VERSION 5.7 ;
  NOWIREEXTENSIONATPIN ON ;
  DIVIDERCHAR "/" ;
  BUSBITCHARS "[]" ;
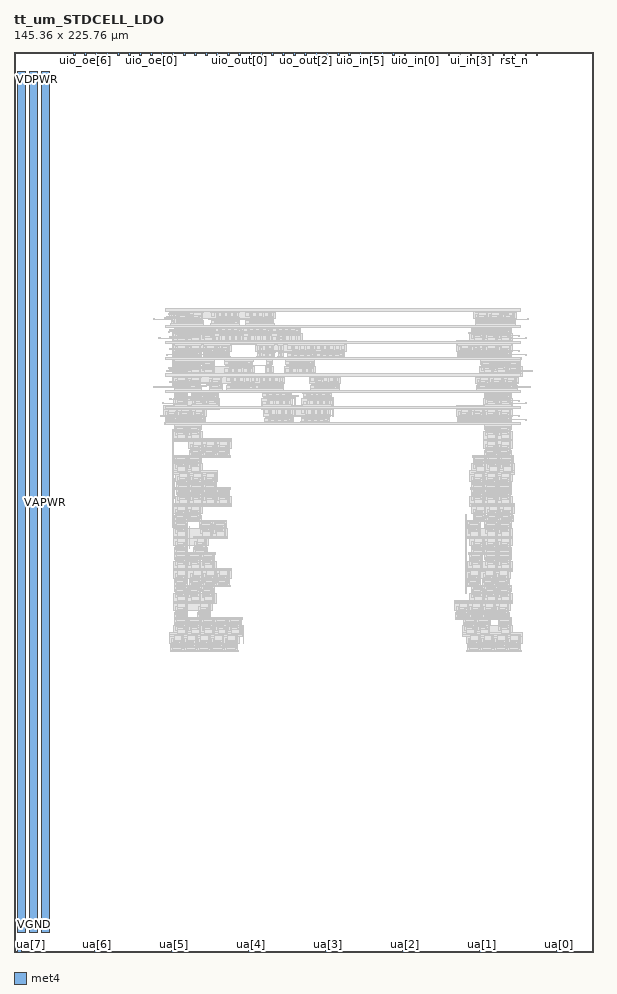
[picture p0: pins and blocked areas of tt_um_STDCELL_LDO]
MACRO tt_um_STDCELL_LDO
  CLASS BLOCK ;
  FOREIGN tt_um_STDCELL_LDO ;
  ORIGIN 0.000 0.000 ;
  SIZE 145.360 BY 225.760 ;
  PIN clk
    DIRECTION INPUT ;
    USE SIGNAL ;
    PORT
      LAYER met4 ;
        RECT 128.190 224.760 128.490 225.760 ;
    END
  END clk
  PIN ena
    DIRECTION INPUT ;
    USE SIGNAL ;
    PORT
      LAYER met4 ;
        RECT 130.950 224.760 131.250 225.760 ;
    END
  END ena
  PIN rst_n
    DIRECTION INPUT ;
    USE SIGNAL ;
    PORT
      LAYER met4 ;
        RECT 125.430 224.760 125.730 225.760 ;
    END
  END rst_n
  PIN ua[0]
    DIRECTION INOUT ;
    USE SIGNAL ;
    ANTENNAGATEAREA 9.000000 ;
    PORT
      LAYER met4 ;
        RECT 136.170 0.000 137.070 1.000 ;
    END
  END ua[0]
  PIN ua[1]
    DIRECTION INOUT ;
    USE SIGNAL ;
    ANTENNAGATEAREA 18.000000 ;
    ANTENNADIFFAREA 1.282500 ;
    PORT
      LAYER met4 ;
        RECT 116.850 0.000 117.750 1.000 ;
    END
  END ua[1]
  PIN ua[2]
    DIRECTION INOUT ;
    USE SIGNAL ;
    ANTENNAGATEAREA 1.125000 ;
    PORT
      LAYER met4 ;
        RECT 97.530 0.000 98.430 1.000 ;
    END
  END ua[2]
  PIN ua[3]
    DIRECTION INOUT ;
    USE SIGNAL ;
    ANTENNAGATEAREA 9.000000 ;
    ANTENNADIFFAREA 82.079994 ;
    PORT
      LAYER met4 ;
        RECT 78.210 0.000 79.110 1.000 ;
    END
  END ua[3]
  PIN ua[4]
    DIRECTION INOUT ;
    USE SIGNAL ;
    PORT
      LAYER met4 ;
        RECT 58.890 0.000 59.790 1.000 ;
    END
  END ua[4]
  PIN ua[5]
    DIRECTION INOUT ;
    USE SIGNAL ;
    PORT
      LAYER met4 ;
        RECT 39.570 0.000 40.470 1.000 ;
    END
  END ua[5]
  PIN ua[6]
    DIRECTION INOUT ;
    USE SIGNAL ;
    PORT
      LAYER met4 ;
        RECT 20.250 0.000 21.150 1.000 ;
    END
  END ua[6]
  PIN ua[7]
    DIRECTION INOUT ;
    USE SIGNAL ;
    PORT
      LAYER met4 ;
        RECT 0.930 0.000 1.830 1.000 ;
    END
  END ua[7]
  PIN ui_in[0]
    DIRECTION INPUT ;
    USE SIGNAL ;
    PORT
      LAYER met4 ;
        RECT 122.670 224.760 122.970 225.760 ;
    END
  END ui_in[0]
  PIN ui_in[1]
    DIRECTION INPUT ;
    USE SIGNAL ;
    PORT
      LAYER met4 ;
        RECT 119.910 224.760 120.210 225.760 ;
    END
  END ui_in[1]
  PIN ui_in[2]
    DIRECTION INPUT ;
    USE SIGNAL ;
    PORT
      LAYER met4 ;
        RECT 117.150 224.760 117.450 225.760 ;
    END
  END ui_in[2]
  PIN ui_in[3]
    DIRECTION INPUT ;
    USE SIGNAL ;
    PORT
      LAYER met4 ;
        RECT 114.390 224.760 114.690 225.760 ;
    END
  END ui_in[3]
  PIN ui_in[4]
    DIRECTION INPUT ;
    USE SIGNAL ;
    PORT
      LAYER met4 ;
        RECT 111.630 224.760 111.930 225.760 ;
    END
  END ui_in[4]
  PIN ui_in[5]
    DIRECTION INPUT ;
    USE SIGNAL ;
    PORT
      LAYER met4 ;
        RECT 108.870 224.760 109.170 225.760 ;
    END
  END ui_in[5]
  PIN ui_in[6]
    DIRECTION INPUT ;
    USE SIGNAL ;
    PORT
      LAYER met4 ;
        RECT 106.110 224.760 106.410 225.760 ;
    END
  END ui_in[6]
  PIN ui_in[7]
    DIRECTION INPUT ;
    USE SIGNAL ;
    PORT
      LAYER met4 ;
        RECT 103.350 224.760 103.650 225.760 ;
    END
  END ui_in[7]
  PIN uio_in[0]
    DIRECTION INPUT ;
    USE SIGNAL ;
    PORT
      LAYER met4 ;
        RECT 100.590 224.760 100.890 225.760 ;
    END
  END uio_in[0]
  PIN uio_in[1]
    DIRECTION INPUT ;
    USE SIGNAL ;
    PORT
      LAYER met4 ;
        RECT 97.830 224.760 98.130 225.760 ;
    END
  END uio_in[1]
  PIN uio_in[2]
    DIRECTION INPUT ;
    USE SIGNAL ;
    PORT
      LAYER met4 ;
        RECT 95.070 224.760 95.370 225.760 ;
    END
  END uio_in[2]
  PIN uio_in[3]
    DIRECTION INPUT ;
    USE SIGNAL ;
    PORT
      LAYER met4 ;
        RECT 92.310 224.760 92.610 225.760 ;
    END
  END uio_in[3]
  PIN uio_in[4]
    DIRECTION INPUT ;
    USE SIGNAL ;
    PORT
      LAYER met4 ;
        RECT 89.550 224.760 89.850 225.760 ;
    END
  END uio_in[4]
  PIN uio_in[5]
    DIRECTION INPUT ;
    USE SIGNAL ;
    PORT
      LAYER met4 ;
        RECT 86.790 224.760 87.090 225.760 ;
    END
  END uio_in[5]
  PIN uio_in[6]
    DIRECTION INPUT ;
    USE SIGNAL ;
    PORT
      LAYER met4 ;
        RECT 84.030 224.760 84.330 225.760 ;
    END
  END uio_in[6]
  PIN uio_in[7]
    DIRECTION INPUT ;
    USE SIGNAL ;
    PORT
      LAYER met4 ;
        RECT 81.270 224.760 81.570 225.760 ;
    END
  END uio_in[7]
  PIN uio_oe[0]
    DIRECTION OUTPUT ;
    USE SIGNAL ;
    PORT
      LAYER met4 ;
        RECT 34.350 224.760 34.650 225.760 ;
    END
  END uio_oe[0]
  PIN uio_oe[1]
    DIRECTION OUTPUT ;
    USE SIGNAL ;
    PORT
      LAYER met4 ;
        RECT 31.590 224.760 31.890 225.760 ;
    END
  END uio_oe[1]
  PIN uio_oe[2]
    DIRECTION OUTPUT ;
    USE SIGNAL ;
    PORT
      LAYER met4 ;
        RECT 28.830 224.760 29.130 225.760 ;
    END
  END uio_oe[2]
  PIN uio_oe[3]
    DIRECTION OUTPUT ;
    USE SIGNAL ;
    PORT
      LAYER met4 ;
        RECT 26.070 224.760 26.370 225.760 ;
    END
  END uio_oe[3]
  PIN uio_oe[4]
    DIRECTION OUTPUT ;
    USE SIGNAL ;
    PORT
      LAYER met4 ;
        RECT 23.310 224.760 23.610 225.760 ;
    END
  END uio_oe[4]
  PIN uio_oe[5]
    DIRECTION OUTPUT ;
    USE SIGNAL ;
    PORT
      LAYER met4 ;
        RECT 20.550 224.760 20.850 225.760 ;
    END
  END uio_oe[5]
  PIN uio_oe[6]
    DIRECTION OUTPUT ;
    USE SIGNAL ;
    PORT
      LAYER met4 ;
        RECT 17.790 224.760 18.090 225.760 ;
    END
  END uio_oe[6]
  PIN uio_oe[7]
    DIRECTION OUTPUT ;
    USE SIGNAL ;
    PORT
      LAYER met4 ;
        RECT 15.030 224.760 15.330 225.760 ;
    END
  END uio_oe[7]
  PIN uio_out[0]
    DIRECTION OUTPUT ;
    USE SIGNAL ;
    PORT
      LAYER met4 ;
        RECT 56.430 224.760 56.730 225.760 ;
    END
  END uio_out[0]
  PIN uio_out[1]
    DIRECTION OUTPUT ;
    USE SIGNAL ;
    PORT
      LAYER met4 ;
        RECT 53.670 224.760 53.970 225.760 ;
    END
  END uio_out[1]
  PIN uio_out[2]
    DIRECTION OUTPUT ;
    USE SIGNAL ;
    PORT
      LAYER met4 ;
        RECT 50.910 224.760 51.210 225.760 ;
    END
  END uio_out[2]
  PIN uio_out[3]
    DIRECTION OUTPUT ;
    USE SIGNAL ;
    PORT
      LAYER met4 ;
        RECT 48.150 224.760 48.450 225.760 ;
    END
  END uio_out[3]
  PIN uio_out[4]
    DIRECTION OUTPUT ;
    USE SIGNAL ;
    PORT
      LAYER met4 ;
        RECT 45.390 224.760 45.690 225.760 ;
    END
  END uio_out[4]
  PIN uio_out[5]
    DIRECTION OUTPUT ;
    USE SIGNAL ;
    PORT
      LAYER met4 ;
        RECT 42.630 224.760 42.930 225.760 ;
    END
  END uio_out[5]
  PIN uio_out[6]
    DIRECTION OUTPUT ;
    USE SIGNAL ;
    PORT
      LAYER met4 ;
        RECT 39.870 224.760 40.170 225.760 ;
    END
  END uio_out[6]
  PIN uio_out[7]
    DIRECTION OUTPUT ;
    USE SIGNAL ;
    PORT
      LAYER met4 ;
        RECT 37.110 224.760 37.410 225.760 ;
    END
  END uio_out[7]
  PIN uo_out[0]
    DIRECTION OUTPUT ;
    USE SIGNAL ;
    PORT
      LAYER met4 ;
        RECT 78.510 224.760 78.810 225.760 ;
    END
  END uo_out[0]
  PIN uo_out[1]
    DIRECTION OUTPUT ;
    USE SIGNAL ;
    PORT
      LAYER met4 ;
        RECT 75.750 224.760 76.050 225.760 ;
    END
  END uo_out[1]
  PIN uo_out[2]
    DIRECTION OUTPUT ;
    USE SIGNAL ;
    PORT
      LAYER met4 ;
        RECT 72.990 224.760 73.290 225.760 ;
    END
  END uo_out[2]
  PIN uo_out[3]
    DIRECTION OUTPUT ;
    USE SIGNAL ;
    PORT
      LAYER met4 ;
        RECT 70.230 224.760 70.530 225.760 ;
    END
  END uo_out[3]
  PIN uo_out[4]
    DIRECTION OUTPUT ;
    USE SIGNAL ;
    PORT
      LAYER met4 ;
        RECT 67.470 224.760 67.770 225.760 ;
    END
  END uo_out[4]
  PIN uo_out[5]
    DIRECTION OUTPUT ;
    USE SIGNAL ;
    PORT
      LAYER met4 ;
        RECT 64.710 224.760 65.010 225.760 ;
    END
  END uo_out[5]
  PIN uo_out[6]
    DIRECTION OUTPUT ;
    USE SIGNAL ;
    PORT
      LAYER met4 ;
        RECT 61.950 224.760 62.250 225.760 ;
    END
  END uo_out[6]
  PIN uo_out[7]
    DIRECTION OUTPUT ;
    USE SIGNAL ;
    PORT
      LAYER met4 ;
        RECT 59.190 224.760 59.490 225.760 ;
    END
  END uo_out[7]
  PIN VDPWR
    DIRECTION INOUT ;
    USE POWER ;
    PORT
      LAYER met4 ;
        RECT 1.000 5.000 3.000 220.760 ;
    END
  END VDPWR
  PIN VGND
    DIRECTION INOUT ;
    USE GROUND ;
    PORT
      LAYER met4 ;
        RECT 4.000 5.000 6.000 220.760 ;
    END
  END VGND
  PIN VAPWR
    DIRECTION INOUT ;
    USE POWER ;
    PORT
      LAYER met4 ;
        RECT 7.000 5.000 9.000 220.760 ;
    END
  END VAPWR
  OBS
      LAYER nwell ;
        RECT 38.990 158.825 65.570 161.425 ;
        RECT 115.310 158.825 126.050 161.425 ;
      LAYER pwell ;
        RECT 39.410 157.155 40.740 158.355 ;
        RECT 40.780 157.155 44.100 158.435 ;
        RECT 44.140 157.155 47.460 158.435 ;
        RECT 49.665 157.155 56.565 158.525 ;
        RECT 58.305 157.155 65.205 158.525 ;
        RECT 115.660 157.155 118.980 158.435 ;
        RECT 119.020 157.155 122.340 158.435 ;
        RECT 122.380 157.155 125.700 158.435 ;
        RECT 39.190 156.725 72.090 157.155 ;
        RECT 114.550 156.725 125.850 157.155 ;
        RECT 40.300 155.445 43.620 156.725 ;
        RECT 43.660 155.445 46.980 156.725 ;
        RECT 47.020 155.445 50.340 156.725 ;
        RECT 50.625 155.355 57.525 156.725 ;
        RECT 57.825 155.355 64.725 156.725 ;
        RECT 65.025 155.355 71.925 156.725 ;
        RECT 114.700 155.445 118.020 156.725 ;
        RECT 118.060 155.445 121.380 156.725 ;
        RECT 121.420 155.445 124.740 156.725 ;
      LAYER nwell ;
        RECT 39.950 153.285 72.290 155.055 ;
        RECT 114.350 153.285 125.090 155.055 ;
        RECT 39.950 152.455 83.330 153.285 ;
        RECT 39.950 150.685 54.530 152.455 ;
        RECT 60.590 150.685 83.330 152.455 ;
        RECT 110.990 150.685 125.090 153.285 ;
      LAYER pwell ;
        RECT 40.300 149.015 43.620 150.295 ;
        RECT 43.660 149.015 46.980 150.295 ;
        RECT 47.500 149.015 50.820 150.295 ;
        RECT 50.860 149.015 54.180 150.295 ;
        RECT 61.010 149.015 62.340 150.215 ;
        RECT 62.450 149.015 63.780 150.215 ;
        RECT 63.890 149.015 65.220 150.215 ;
        RECT 66.290 149.015 67.620 150.215 ;
        RECT 68.865 149.015 75.765 150.385 ;
        RECT 76.065 149.015 82.965 150.385 ;
        RECT 111.340 149.015 114.660 150.295 ;
        RECT 114.700 149.015 118.020 150.295 ;
        RECT 118.060 149.015 121.380 150.295 ;
        RECT 121.420 149.015 124.740 150.295 ;
        RECT 40.150 148.585 60.090 149.015 ;
        RECT 60.790 148.585 65.370 149.015 ;
        RECT 66.070 148.585 67.770 149.015 ;
        RECT 67.990 148.585 83.130 149.015 ;
        RECT 111.190 148.585 127.290 149.015 ;
        RECT 40.300 147.305 43.620 148.585 ;
        RECT 43.660 147.305 46.980 148.585 ;
        RECT 47.020 147.305 50.340 148.585 ;
        RECT 53.025 147.215 59.925 148.585 ;
        RECT 63.410 147.385 64.740 148.585 ;
        RECT 68.385 147.215 75.285 148.585 ;
        RECT 117.100 147.305 120.420 148.585 ;
        RECT 120.460 147.305 123.780 148.585 ;
        RECT 123.820 147.305 127.140 148.585 ;
      LAYER nwell ;
        RECT 39.950 145.145 60.290 146.915 ;
        RECT 62.990 145.145 65.090 146.915 ;
        RECT 67.790 145.145 75.650 146.915 ;
        RECT 116.750 145.145 127.490 146.915 ;
        RECT 39.950 144.315 81.890 145.145 ;
        RECT 39.950 142.545 67.970 144.315 ;
        RECT 74.030 142.545 81.890 144.315 ;
        RECT 115.790 144.315 127.490 145.145 ;
        RECT 115.790 142.545 126.530 144.315 ;
      LAYER pwell ;
        RECT 40.300 140.875 43.620 142.155 ;
        RECT 43.660 140.875 46.980 142.155 ;
        RECT 48.940 140.875 52.260 142.155 ;
        RECT 53.505 140.875 60.405 142.245 ;
        RECT 60.705 140.875 67.605 142.245 ;
        RECT 74.625 140.875 81.525 142.245 ;
        RECT 116.140 140.875 119.460 142.155 ;
        RECT 119.500 140.875 122.820 142.155 ;
        RECT 122.860 140.875 126.180 142.155 ;
        RECT 40.150 140.445 52.410 140.875 ;
        RECT 53.110 140.445 69.690 140.875 ;
        RECT 72.310 140.445 81.690 140.875 ;
        RECT 115.990 140.445 126.330 140.875 ;
        RECT 40.300 139.165 43.620 140.445 ;
        RECT 44.620 139.165 47.940 140.445 ;
        RECT 47.980 139.165 51.300 140.445 ;
        RECT 62.625 139.075 69.525 140.445 ;
        RECT 72.705 139.075 79.605 140.445 ;
        RECT 118.060 139.165 121.380 140.445 ;
        RECT 121.420 139.165 124.740 140.445 ;
      LAYER nwell ;
        RECT 39.950 137.005 51.650 138.775 ;
        RECT 37.550 136.175 51.650 137.005 ;
        RECT 62.030 137.005 69.890 138.775 ;
        RECT 72.110 137.005 79.970 138.775 ;
        RECT 117.710 137.005 125.090 138.775 ;
        RECT 62.030 136.175 79.970 137.005 ;
        RECT 37.550 134.405 48.290 136.175 ;
        RECT 62.510 134.405 79.490 136.175 ;
        RECT 110.990 134.405 125.090 137.005 ;
      LAYER pwell ;
        RECT 37.900 132.735 41.220 134.015 ;
        RECT 41.260 132.735 44.580 134.015 ;
        RECT 44.620 132.735 47.940 134.015 ;
        RECT 63.105 132.735 70.005 134.105 ;
        RECT 72.225 132.735 79.125 134.105 ;
        RECT 111.340 132.735 114.660 134.015 ;
        RECT 114.700 132.735 118.020 134.015 ;
        RECT 118.060 132.735 121.380 134.015 ;
        RECT 121.420 132.735 124.740 134.015 ;
        RECT 37.750 132.305 48.090 132.735 ;
        RECT 62.710 132.305 70.170 132.735 ;
        RECT 71.830 132.305 79.290 132.735 ;
        RECT 111.190 132.305 124.890 132.735 ;
        RECT 40.300 131.025 43.620 132.305 ;
        RECT 43.660 131.025 46.980 132.305 ;
        RECT 118.060 131.025 121.380 132.305 ;
        RECT 121.420 131.025 124.740 132.305 ;
      LAYER nwell ;
        RECT 39.950 128.865 47.330 130.635 ;
        RECT 39.950 128.035 54.530 128.865 ;
        RECT 43.790 126.265 54.530 128.035 ;
        RECT 117.710 126.265 125.090 130.635 ;
      LAYER pwell ;
        RECT 44.140 124.595 47.460 125.875 ;
        RECT 47.500 124.595 50.820 125.875 ;
        RECT 50.860 124.595 54.180 125.875 ;
        RECT 118.060 124.595 121.380 125.875 ;
        RECT 121.420 124.595 124.740 125.875 ;
        RECT 40.150 124.165 54.330 124.595 ;
        RECT 115.030 124.165 125.370 124.595 ;
        RECT 40.300 122.885 43.620 124.165 ;
        RECT 43.660 122.885 46.980 124.165 ;
        RECT 115.180 122.885 118.500 124.165 ;
        RECT 118.540 122.885 121.860 124.165 ;
        RECT 121.900 122.885 125.220 124.165 ;
      LAYER nwell ;
        RECT 39.950 120.725 47.330 122.495 ;
        RECT 114.830 120.725 125.570 122.495 ;
        RECT 39.950 119.895 51.170 120.725 ;
        RECT 40.430 118.125 51.170 119.895 ;
        RECT 114.350 119.895 125.570 120.725 ;
        RECT 114.350 118.125 125.090 119.895 ;
      LAYER pwell ;
        RECT 40.780 116.455 44.100 117.735 ;
        RECT 44.140 116.455 47.460 117.735 ;
        RECT 47.500 116.455 50.820 117.735 ;
        RECT 114.700 116.455 118.020 117.735 ;
        RECT 118.060 116.455 121.380 117.735 ;
        RECT 121.420 116.455 124.740 117.735 ;
        RECT 40.630 116.025 54.330 116.455 ;
        RECT 114.550 116.025 124.890 116.455 ;
        RECT 40.780 114.745 44.100 116.025 ;
        RECT 44.140 114.745 47.460 116.025 ;
        RECT 47.500 114.745 50.820 116.025 ;
        RECT 50.860 114.745 54.180 116.025 ;
        RECT 114.700 114.745 118.020 116.025 ;
        RECT 118.060 114.745 121.380 116.025 ;
        RECT 121.420 114.745 124.740 116.025 ;
      LAYER nwell ;
        RECT 40.430 112.585 54.530 114.355 ;
        RECT 39.950 111.755 54.530 112.585 ;
        RECT 114.350 112.585 125.090 114.355 ;
        RECT 114.350 111.755 125.570 112.585 ;
        RECT 39.950 109.985 47.330 111.755 ;
        RECT 114.830 109.985 125.570 111.755 ;
      LAYER pwell ;
        RECT 40.300 108.315 43.620 109.595 ;
        RECT 43.660 108.315 46.980 109.595 ;
        RECT 115.180 108.315 118.500 109.595 ;
        RECT 118.540 108.315 121.860 109.595 ;
        RECT 121.900 108.315 125.220 109.595 ;
        RECT 40.150 107.885 53.370 108.315 ;
        RECT 113.590 107.885 125.370 108.315 ;
        RECT 40.300 106.605 43.620 107.885 ;
        RECT 46.540 106.605 49.860 107.885 ;
        RECT 49.900 106.605 53.220 107.885 ;
        RECT 113.740 106.605 117.060 107.885 ;
        RECT 118.060 106.605 121.380 107.885 ;
        RECT 121.420 106.605 124.740 107.885 ;
      LAYER nwell ;
        RECT 39.950 103.615 53.570 106.215 ;
        RECT 113.390 103.615 125.090 106.215 ;
        RECT 39.950 101.845 48.770 103.615 ;
        RECT 114.350 101.845 125.090 103.615 ;
      LAYER pwell ;
        RECT 40.300 100.175 43.620 101.455 ;
        RECT 45.100 100.175 48.420 101.455 ;
        RECT 114.700 100.175 118.020 101.455 ;
        RECT 118.060 100.175 121.380 101.455 ;
        RECT 121.420 100.175 124.740 101.455 ;
        RECT 40.150 99.745 50.490 100.175 ;
        RECT 114.070 99.745 124.890 100.175 ;
        RECT 40.300 98.465 43.620 99.745 ;
        RECT 43.660 98.465 46.980 99.745 ;
        RECT 47.020 98.465 50.340 99.745 ;
        RECT 114.220 98.465 117.540 99.745 ;
        RECT 118.060 98.465 121.380 99.745 ;
        RECT 121.420 98.465 124.740 99.745 ;
      LAYER nwell ;
        RECT 39.950 96.305 50.690 98.075 ;
        RECT 113.870 96.305 125.090 98.075 ;
        RECT 39.950 93.705 54.530 96.305 ;
        RECT 113.390 95.475 125.090 96.305 ;
        RECT 113.390 93.705 124.610 95.475 ;
      LAYER pwell ;
        RECT 40.300 92.035 43.620 93.315 ;
        RECT 44.140 92.035 47.460 93.315 ;
        RECT 47.500 92.035 50.820 93.315 ;
        RECT 50.860 92.035 54.180 93.315 ;
        RECT 113.740 92.035 117.060 93.315 ;
        RECT 117.580 92.035 120.900 93.315 ;
        RECT 120.940 92.035 124.260 93.315 ;
        RECT 40.150 91.605 54.330 92.035 ;
        RECT 113.590 91.605 124.890 92.035 ;
        RECT 40.300 90.325 43.620 91.605 ;
        RECT 43.660 90.325 46.980 91.605 ;
        RECT 47.020 90.325 50.340 91.605 ;
        RECT 114.700 90.325 118.020 91.605 ;
        RECT 118.060 90.325 121.380 91.605 ;
        RECT 121.420 90.325 124.740 91.605 ;
      LAYER nwell ;
        RECT 39.950 87.335 50.690 89.935 ;
        RECT 114.350 88.165 125.090 89.935 ;
        RECT 110.510 87.335 125.090 88.165 ;
        RECT 39.950 85.565 49.730 87.335 ;
        RECT 110.510 85.565 124.610 87.335 ;
      LAYER pwell ;
        RECT 40.300 83.895 43.620 85.175 ;
        RECT 46.060 83.895 49.380 85.175 ;
        RECT 110.860 83.895 114.180 85.175 ;
        RECT 114.220 83.895 117.540 85.175 ;
        RECT 117.580 83.895 120.900 85.175 ;
        RECT 120.940 83.895 124.260 85.175 ;
        RECT 40.150 83.465 57.210 83.895 ;
        RECT 110.710 83.465 124.890 83.895 ;
        RECT 40.300 82.185 43.620 83.465 ;
        RECT 43.660 82.185 46.980 83.465 ;
        RECT 47.020 82.185 50.340 83.465 ;
        RECT 50.380 82.185 53.700 83.465 ;
        RECT 53.740 82.185 57.060 83.465 ;
        RECT 112.780 82.185 116.100 83.465 ;
        RECT 116.140 82.185 119.460 83.465 ;
        RECT 121.420 82.185 124.740 83.465 ;
      LAYER nwell ;
        RECT 39.950 80.025 57.410 81.795 ;
        RECT 38.990 79.195 57.410 80.025 ;
        RECT 112.430 80.025 125.090 81.795 ;
        RECT 112.430 79.195 127.490 80.025 ;
        RECT 38.990 77.425 56.450 79.195 ;
        RECT 113.390 77.425 127.490 79.195 ;
      LAYER pwell ;
        RECT 39.340 75.755 42.660 77.035 ;
        RECT 42.700 75.755 46.020 77.035 ;
        RECT 46.060 75.755 49.380 77.035 ;
        RECT 49.420 75.755 52.740 77.035 ;
        RECT 52.780 75.755 56.100 77.035 ;
        RECT 113.740 75.755 117.060 77.035 ;
        RECT 117.100 75.755 120.420 77.035 ;
        RECT 120.460 75.755 123.780 77.035 ;
        RECT 123.820 75.755 127.140 77.035 ;
        RECT 39.190 75.325 56.250 75.755 ;
        RECT 113.590 75.325 127.290 75.755 ;
      LAYER li1 ;
        RECT 39.320 160.925 47.480 161.095 ;
        RECT 49.400 160.925 56.600 161.095 ;
        RECT 58.040 160.925 65.240 161.095 ;
        RECT 115.640 160.925 125.720 161.095 ;
        RECT 39.410 159.115 40.000 160.695 ;
        RECT 40.280 160.135 40.665 160.695 ;
        RECT 40.280 159.965 40.675 160.135 ;
        RECT 40.280 159.115 40.665 159.965 ;
        RECT 39.445 158.490 40.155 158.875 ;
        RECT 39.410 157.305 40.000 158.265 ;
        RECT 40.335 157.435 40.665 159.115 ;
        RECT 40.935 159.040 41.410 159.945 ;
        RECT 41.590 159.650 43.560 160.695 ;
        RECT 43.740 160.135 43.995 160.695 ;
        RECT 43.740 159.965 44.075 160.135 ;
        RECT 41.590 159.220 43.035 159.650 ;
        RECT 40.935 158.870 42.825 159.040 ;
        RECT 43.205 158.895 43.570 159.480 ;
        RECT 43.740 159.065 43.995 159.965 ;
        RECT 40.935 158.275 41.105 158.870 ;
        RECT 41.275 158.445 42.065 158.690 ;
        RECT 42.235 158.665 42.825 158.870 ;
        RECT 43.035 158.565 43.625 158.895 ;
        RECT 40.935 157.845 41.140 158.275 ;
        RECT 41.310 157.930 43.035 158.275 ;
        RECT 43.205 158.100 43.570 158.565 ;
        RECT 43.795 158.395 43.995 159.065 ;
        RECT 41.310 157.675 43.560 157.930 ;
        RECT 41.230 157.305 43.560 157.675 ;
        RECT 43.740 157.515 43.995 158.395 ;
        RECT 44.295 159.040 44.770 159.945 ;
        RECT 44.950 159.650 46.920 160.695 ;
        RECT 44.950 159.220 46.395 159.650 ;
        RECT 44.295 158.870 46.185 159.040 ;
        RECT 46.565 158.895 46.930 159.480 ;
        RECT 47.100 159.065 47.355 160.695 ;
        RECT 49.495 160.565 56.425 160.735 ;
        RECT 49.495 159.385 50.385 160.565 ;
        RECT 44.295 158.275 44.465 158.870 ;
        RECT 44.635 158.445 45.425 158.690 ;
        RECT 45.595 158.665 46.185 158.870 ;
        RECT 46.395 158.565 46.985 158.895 ;
        RECT 44.295 157.845 44.500 158.275 ;
        RECT 44.670 157.930 46.395 158.275 ;
        RECT 46.565 158.100 46.930 158.565 ;
        RECT 47.155 158.395 47.355 159.065 ;
        RECT 50.675 159.145 51.005 160.385 ;
        RECT 51.175 159.325 52.065 160.565 ;
        RECT 52.235 159.145 52.565 160.385 ;
        RECT 52.735 159.325 53.625 160.565 ;
        RECT 53.795 159.145 54.125 160.385 ;
        RECT 54.295 159.325 55.185 160.565 ;
        RECT 55.355 159.145 55.685 160.385 ;
        RECT 55.855 159.325 56.425 160.565 ;
        RECT 58.135 160.565 65.065 160.735 ;
        RECT 58.135 159.385 59.025 160.565 ;
        RECT 59.315 159.145 59.645 160.385 ;
        RECT 59.815 159.325 60.705 160.565 ;
        RECT 60.875 159.145 61.205 160.385 ;
        RECT 61.375 159.325 62.265 160.565 ;
        RECT 62.435 159.145 62.765 160.385 ;
        RECT 62.935 159.325 63.825 160.565 ;
        RECT 63.995 159.145 64.325 160.385 ;
        RECT 64.495 159.325 65.065 160.565 ;
        RECT 50.675 158.975 56.510 159.145 ;
        RECT 59.315 158.975 65.150 159.145 ;
        RECT 52.065 158.945 52.235 158.975 ;
        RECT 49.685 158.755 49.855 158.775 ;
        RECT 49.685 158.605 56.160 158.755 ;
        RECT 49.710 158.520 56.160 158.605 ;
        RECT 44.670 157.675 46.920 157.930 ;
        RECT 44.590 157.305 46.920 157.675 ;
        RECT 47.100 157.515 47.355 158.395 ;
        RECT 50.595 158.335 55.625 158.340 ;
        RECT 56.340 158.335 56.510 158.975 ;
        RECT 58.525 158.755 58.695 158.775 ;
        RECT 58.350 158.520 64.800 158.755 ;
        RECT 49.495 157.490 50.385 158.325 ;
        RECT 50.595 158.170 56.510 158.335 ;
        RECT 59.235 158.335 64.265 158.340 ;
        RECT 64.980 158.335 65.150 158.975 ;
        RECT 50.595 157.670 50.805 158.170 ;
        RECT 50.975 157.490 51.985 157.985 ;
        RECT 52.155 157.670 52.365 158.170 ;
        RECT 52.535 157.490 53.545 157.985 ;
        RECT 53.715 157.670 53.925 158.170 ;
        RECT 55.315 158.165 56.510 158.170 ;
        RECT 54.095 157.490 55.145 157.985 ;
        RECT 55.315 157.670 55.965 158.165 ;
        RECT 56.135 157.490 56.505 157.985 ;
        RECT 49.495 157.320 56.505 157.490 ;
        RECT 58.135 157.490 59.025 158.325 ;
        RECT 59.235 158.170 65.150 158.335 ;
        RECT 59.235 157.670 59.445 158.170 ;
        RECT 59.615 157.490 60.625 157.985 ;
        RECT 60.795 157.670 61.005 158.170 ;
        RECT 61.175 157.490 62.185 157.985 ;
        RECT 62.355 157.670 62.565 158.170 ;
        RECT 63.955 158.165 65.150 158.170 ;
        RECT 115.815 159.040 116.290 159.945 ;
        RECT 116.470 159.650 118.440 160.695 ;
        RECT 116.470 159.220 117.915 159.650 ;
        RECT 115.815 158.870 117.705 159.040 ;
        RECT 118.085 158.895 118.450 159.480 ;
        RECT 118.620 159.065 118.875 160.695 ;
        RECT 115.815 158.275 115.985 158.870 ;
        RECT 116.155 158.445 116.945 158.690 ;
        RECT 117.115 158.665 117.705 158.870 ;
        RECT 117.915 158.565 118.505 158.895 ;
        RECT 62.735 157.490 63.785 157.985 ;
        RECT 63.955 157.670 64.605 158.165 ;
        RECT 64.775 157.490 65.145 157.985 ;
        RECT 115.815 157.845 116.020 158.275 ;
        RECT 116.190 157.930 117.915 158.275 ;
        RECT 118.085 158.100 118.450 158.565 ;
        RECT 118.675 158.395 118.875 159.065 ;
        RECT 116.190 157.675 118.440 157.930 ;
        RECT 58.135 157.320 65.145 157.490 ;
        RECT 116.110 157.305 118.440 157.675 ;
        RECT 118.620 157.515 118.875 158.395 ;
        RECT 119.175 159.040 119.650 159.945 ;
        RECT 119.830 159.650 121.800 160.695 ;
        RECT 121.980 160.135 122.235 160.695 ;
        RECT 121.980 159.965 122.275 160.135 ;
        RECT 119.830 159.220 121.275 159.650 ;
        RECT 119.175 158.870 121.065 159.040 ;
        RECT 121.445 158.895 121.810 159.480 ;
        RECT 121.980 159.065 122.235 159.965 ;
        RECT 119.175 158.275 119.345 158.870 ;
        RECT 119.515 158.445 120.305 158.690 ;
        RECT 120.475 158.665 121.065 158.870 ;
        RECT 121.275 158.565 121.865 158.895 ;
        RECT 119.175 157.845 119.380 158.275 ;
        RECT 119.550 157.930 121.275 158.275 ;
        RECT 121.445 158.100 121.810 158.565 ;
        RECT 122.035 158.395 122.235 159.065 ;
        RECT 119.550 157.675 121.800 157.930 ;
        RECT 119.470 157.305 121.800 157.675 ;
        RECT 121.980 157.515 122.235 158.395 ;
        RECT 122.535 159.040 123.010 159.945 ;
        RECT 123.190 159.650 125.160 160.695 ;
        RECT 123.190 159.220 124.635 159.650 ;
        RECT 122.535 158.870 124.425 159.040 ;
        RECT 124.805 158.895 125.170 159.480 ;
        RECT 125.340 159.065 125.595 160.695 ;
        RECT 122.535 158.275 122.705 158.870 ;
        RECT 122.875 158.445 123.665 158.690 ;
        RECT 123.835 158.665 124.425 158.870 ;
        RECT 124.635 158.565 125.225 158.895 ;
        RECT 125.395 158.775 125.595 159.065 ;
        RECT 125.395 158.605 125.675 158.775 ;
        RECT 122.535 157.845 122.740 158.275 ;
        RECT 122.910 157.930 124.635 158.275 ;
        RECT 124.805 158.100 125.170 158.565 ;
        RECT 125.395 158.395 125.595 158.605 ;
        RECT 122.910 157.675 125.160 157.930 ;
        RECT 122.830 157.305 125.160 157.675 ;
        RECT 125.340 157.515 125.595 158.395 ;
        RECT 39.320 156.855 71.960 157.025 ;
        RECT 114.680 156.855 125.720 157.025 ;
        RECT 40.750 156.205 43.080 156.575 ;
        RECT 40.455 155.605 40.660 156.035 ;
        RECT 40.830 155.950 43.080 156.205 ;
        RECT 40.830 155.605 42.555 155.950 ;
        RECT 39.825 142.200 39.995 155.375 ;
        RECT 40.455 155.010 40.625 155.605 ;
        RECT 40.795 155.190 41.585 155.435 ;
        RECT 42.725 155.315 43.090 155.780 ;
        RECT 43.260 155.485 43.515 156.365 ;
        RECT 44.110 156.205 46.440 156.575 ;
        RECT 41.755 155.010 42.345 155.215 ;
        RECT 40.455 154.840 42.345 155.010 ;
        RECT 42.555 154.985 43.145 155.315 ;
        RECT 40.455 153.935 40.930 154.840 ;
        RECT 41.110 154.230 42.555 154.660 ;
        RECT 42.725 154.400 43.090 154.985 ;
        RECT 43.315 154.815 43.515 155.485 ;
        RECT 41.110 153.185 43.080 154.230 ;
        RECT 43.260 154.015 43.515 154.815 ;
        RECT 43.815 155.605 44.020 156.035 ;
        RECT 44.190 155.950 46.440 156.205 ;
        RECT 44.190 155.605 45.915 155.950 ;
        RECT 43.815 155.010 43.985 155.605 ;
        RECT 44.155 155.190 44.945 155.435 ;
        RECT 46.085 155.315 46.450 155.780 ;
        RECT 46.620 155.485 46.875 156.365 ;
        RECT 47.470 156.205 49.800 156.575 ;
        RECT 50.455 156.390 57.465 156.560 ;
        RECT 45.115 155.010 45.705 155.215 ;
        RECT 43.815 154.840 45.705 155.010 ;
        RECT 45.915 154.985 46.505 155.315 ;
        RECT 46.085 154.865 46.455 154.985 ;
        RECT 43.260 153.845 43.565 154.015 ;
        RECT 43.815 153.935 44.290 154.840 ;
        RECT 44.470 154.230 45.915 154.660 ;
        RECT 46.085 154.400 46.450 154.865 ;
        RECT 46.675 154.815 46.875 155.485 ;
        RECT 43.260 153.185 43.515 153.845 ;
        RECT 44.470 153.185 46.440 154.230 ;
        RECT 46.620 153.185 46.875 154.815 ;
        RECT 47.175 155.605 47.380 156.035 ;
        RECT 47.550 155.950 49.800 156.205 ;
        RECT 47.550 155.605 49.275 155.950 ;
        RECT 47.175 155.010 47.345 155.605 ;
        RECT 47.515 155.190 48.305 155.435 ;
        RECT 49.445 155.375 49.810 155.780 ;
        RECT 49.980 155.485 50.235 156.365 ;
        RECT 50.455 155.555 51.345 156.390 ;
        RECT 51.555 155.710 51.765 156.210 ;
        RECT 51.935 155.895 52.945 156.390 ;
        RECT 52.065 155.710 52.235 155.715 ;
        RECT 53.115 155.710 53.325 156.210 ;
        RECT 53.495 155.895 54.505 156.390 ;
        RECT 54.675 155.710 54.885 156.210 ;
        RECT 55.055 155.895 56.105 156.390 ;
        RECT 56.275 155.715 56.925 156.210 ;
        RECT 57.095 155.895 57.465 156.390 ;
        RECT 57.655 156.390 64.665 156.560 ;
        RECT 56.275 155.710 57.470 155.715 ;
        RECT 51.555 155.545 57.470 155.710 ;
        RECT 57.655 155.555 58.545 156.390 ;
        RECT 58.755 155.710 58.965 156.210 ;
        RECT 59.135 155.895 60.145 156.390 ;
        RECT 60.315 155.710 60.525 156.210 ;
        RECT 60.695 155.895 61.705 156.390 ;
        RECT 61.875 155.710 62.085 156.210 ;
        RECT 62.255 155.895 63.305 156.390 ;
        RECT 63.475 155.715 64.125 156.210 ;
        RECT 64.295 155.895 64.665 156.390 ;
        RECT 64.855 156.390 71.865 156.560 ;
        RECT 63.475 155.710 64.670 155.715 ;
        RECT 51.555 155.540 56.585 155.545 ;
        RECT 49.345 155.315 49.810 155.375 ;
        RECT 48.475 155.010 49.065 155.215 ;
        RECT 47.175 154.840 49.065 155.010 ;
        RECT 49.275 154.985 49.865 155.315 ;
        RECT 47.175 153.935 47.650 154.840 ;
        RECT 47.830 154.230 49.275 154.660 ;
        RECT 49.445 154.400 49.810 154.985 ;
        RECT 50.035 154.815 50.235 155.485 ;
        RECT 50.705 155.360 50.875 155.375 ;
        RECT 50.670 155.125 57.120 155.360 ;
        RECT 57.300 154.905 57.470 155.545 ;
        RECT 58.755 155.545 64.670 155.710 ;
        RECT 64.855 155.555 65.745 156.390 ;
        RECT 65.955 155.710 66.165 156.210 ;
        RECT 66.335 155.895 67.345 156.390 ;
        RECT 67.515 155.710 67.725 156.210 ;
        RECT 67.895 155.895 68.905 156.390 ;
        RECT 69.075 155.710 69.285 156.210 ;
        RECT 69.455 155.895 70.505 156.390 ;
        RECT 70.675 155.715 71.325 156.210 ;
        RECT 71.495 155.895 71.865 156.390 ;
        RECT 115.150 156.205 117.480 156.575 ;
        RECT 70.675 155.710 71.870 155.715 ;
        RECT 58.755 155.540 63.785 155.545 ;
        RECT 57.845 155.360 58.015 155.375 ;
        RECT 57.845 155.205 64.320 155.360 ;
        RECT 57.870 155.125 64.320 155.205 ;
        RECT 64.500 154.905 64.670 155.545 ;
        RECT 65.955 155.545 71.870 155.710 ;
        RECT 65.955 155.540 70.985 155.545 ;
        RECT 64.985 155.360 65.155 155.375 ;
        RECT 64.985 155.205 71.520 155.360 ;
        RECT 65.070 155.125 71.520 155.205 ;
        RECT 71.700 154.905 71.870 155.545 ;
        RECT 47.830 153.185 49.800 154.230 ;
        RECT 49.980 153.185 50.235 154.815 ;
        RECT 51.635 154.735 57.470 154.905 ;
        RECT 58.835 154.735 64.670 154.905 ;
        RECT 66.035 154.735 71.870 154.905 ;
        RECT 114.855 155.605 115.060 156.035 ;
        RECT 115.230 155.950 117.480 156.205 ;
        RECT 115.230 155.605 116.955 155.950 ;
        RECT 114.855 155.010 115.025 155.605 ;
        RECT 115.195 155.190 115.985 155.435 ;
        RECT 117.125 155.375 117.490 155.780 ;
        RECT 117.660 155.485 117.915 156.365 ;
        RECT 118.510 156.205 120.840 156.575 ;
        RECT 117.005 155.315 117.490 155.375 ;
        RECT 116.155 155.010 116.745 155.215 ;
        RECT 114.855 154.840 116.745 155.010 ;
        RECT 116.955 154.985 117.545 155.315 ;
        RECT 50.455 153.315 51.345 154.495 ;
        RECT 51.635 153.495 51.965 154.735 ;
        RECT 52.135 153.315 53.025 154.555 ;
        RECT 53.195 153.495 53.525 154.735 ;
        RECT 53.695 153.315 54.585 154.555 ;
        RECT 54.755 153.495 55.085 154.735 ;
        RECT 55.255 153.315 56.145 154.555 ;
        RECT 56.315 153.495 56.645 154.735 ;
        RECT 56.815 153.315 57.385 154.555 ;
        RECT 50.455 153.145 57.385 153.315 ;
        RECT 57.655 153.315 58.545 154.495 ;
        RECT 58.835 153.495 59.165 154.735 ;
        RECT 59.335 153.315 60.225 154.555 ;
        RECT 60.395 153.495 60.725 154.735 ;
        RECT 60.895 153.315 61.785 154.555 ;
        RECT 61.955 153.495 62.285 154.735 ;
        RECT 62.455 153.315 63.345 154.555 ;
        RECT 63.515 153.495 63.845 154.735 ;
        RECT 64.015 153.315 64.585 154.555 ;
        RECT 57.655 153.145 64.585 153.315 ;
        RECT 64.855 153.315 65.745 154.495 ;
        RECT 66.035 154.015 66.365 154.735 ;
        RECT 66.005 153.845 66.365 154.015 ;
        RECT 66.035 153.495 66.365 153.845 ;
        RECT 66.535 153.315 67.425 154.555 ;
        RECT 67.595 153.495 67.925 154.735 ;
        RECT 68.095 153.315 68.985 154.555 ;
        RECT 69.155 153.495 69.485 154.735 ;
        RECT 69.655 153.315 70.545 154.555 ;
        RECT 70.715 153.495 71.045 154.735 ;
        RECT 71.215 153.315 71.785 154.555 ;
        RECT 114.855 153.935 115.330 154.840 ;
        RECT 115.510 154.230 116.955 154.660 ;
        RECT 117.125 154.400 117.490 154.985 ;
        RECT 117.715 154.815 117.915 155.485 ;
        RECT 64.855 153.145 71.785 153.315 ;
        RECT 115.510 153.185 117.480 154.230 ;
        RECT 117.660 153.185 117.915 154.815 ;
        RECT 118.215 155.605 118.420 156.035 ;
        RECT 118.590 155.950 120.840 156.205 ;
        RECT 118.590 155.605 120.315 155.950 ;
        RECT 118.215 155.010 118.385 155.605 ;
        RECT 118.555 155.190 119.345 155.435 ;
        RECT 120.485 155.315 120.850 155.780 ;
        RECT 121.020 155.485 121.275 156.365 ;
        RECT 121.870 156.205 124.200 156.575 ;
        RECT 119.515 155.010 120.105 155.215 ;
        RECT 118.215 154.840 120.105 155.010 ;
        RECT 120.315 154.985 120.905 155.315 ;
        RECT 120.405 154.865 120.850 154.985 ;
        RECT 118.215 153.935 118.690 154.840 ;
        RECT 118.870 154.230 120.315 154.660 ;
        RECT 120.485 154.400 120.850 154.865 ;
        RECT 121.075 154.815 121.275 155.485 ;
        RECT 118.870 153.185 120.840 154.230 ;
        RECT 121.020 153.185 121.275 154.815 ;
        RECT 121.575 155.605 121.780 156.035 ;
        RECT 121.950 155.950 124.200 156.205 ;
        RECT 121.950 155.605 123.675 155.950 ;
        RECT 121.575 155.010 121.745 155.605 ;
        RECT 121.915 155.190 122.705 155.435 ;
        RECT 123.845 155.315 124.210 155.780 ;
        RECT 124.380 155.485 124.635 156.365 ;
        RECT 122.875 155.010 123.465 155.215 ;
        RECT 121.575 154.840 123.465 155.010 ;
        RECT 123.675 154.985 124.265 155.315 ;
        RECT 123.805 154.865 124.210 154.985 ;
        RECT 121.575 153.935 122.050 154.840 ;
        RECT 122.230 154.230 123.675 154.660 ;
        RECT 123.845 154.400 124.210 154.865 ;
        RECT 124.435 154.815 124.635 155.485 ;
        RECT 122.230 153.185 124.200 154.230 ;
        RECT 124.380 154.015 124.635 154.815 ;
        RECT 124.380 153.845 124.655 154.015 ;
        RECT 124.380 153.185 124.635 153.845 ;
        RECT 40.280 152.785 83.000 152.955 ;
        RECT 111.320 152.785 124.760 152.955 ;
        RECT 40.455 150.900 40.930 151.805 ;
        RECT 41.110 151.510 43.080 152.555 ;
        RECT 41.110 151.080 42.555 151.510 ;
        RECT 40.455 150.730 42.345 150.900 ;
        RECT 42.725 150.755 43.090 151.340 ;
        RECT 43.260 150.925 43.515 152.555 ;
        RECT 40.455 150.135 40.625 150.730 ;
        RECT 40.795 150.305 41.585 150.550 ;
        RECT 41.755 150.525 42.345 150.730 ;
        RECT 42.555 150.425 43.145 150.755 ;
        RECT 40.455 149.705 40.660 150.135 ;
        RECT 40.830 149.790 42.555 150.135 ;
        RECT 42.725 149.960 43.090 150.425 ;
        RECT 43.315 150.255 43.515 150.925 ;
        RECT 43.260 149.935 43.515 150.255 ;
        RECT 43.815 150.900 44.290 151.805 ;
        RECT 44.470 151.510 46.440 152.555 ;
        RECT 44.470 151.080 45.915 151.510 ;
        RECT 43.815 150.730 45.705 150.900 ;
        RECT 46.085 150.755 46.450 151.340 ;
        RECT 46.620 150.925 46.875 152.555 ;
        RECT 43.815 150.135 43.985 150.730 ;
        RECT 44.155 150.305 44.945 150.550 ;
        RECT 45.115 150.525 45.705 150.730 ;
        RECT 45.915 150.425 46.505 150.755 ;
        RECT 40.830 149.535 43.080 149.790 ;
        RECT 40.750 149.165 43.080 149.535 ;
        RECT 43.260 149.765 43.565 149.935 ;
        RECT 43.260 149.375 43.515 149.765 ;
        RECT 43.815 149.705 44.020 150.135 ;
        RECT 44.190 149.790 45.915 150.135 ;
        RECT 46.085 149.960 46.450 150.425 ;
        RECT 46.675 150.255 46.875 150.925 ;
        RECT 44.190 149.535 46.440 149.790 ;
        RECT 44.110 149.165 46.440 149.535 ;
        RECT 46.620 149.375 46.875 150.255 ;
        RECT 47.655 150.900 48.130 151.805 ;
        RECT 48.310 151.510 50.280 152.555 ;
        RECT 48.310 151.080 49.755 151.510 ;
        RECT 47.655 150.730 49.545 150.900 ;
        RECT 49.925 150.755 50.290 151.340 ;
        RECT 50.460 150.925 50.715 152.555 ;
        RECT 47.655 150.135 47.825 150.730 ;
        RECT 47.995 150.305 48.785 150.550 ;
        RECT 48.955 150.525 49.545 150.730 ;
        RECT 49.755 150.425 50.345 150.755 ;
        RECT 47.655 149.705 47.860 150.135 ;
        RECT 48.030 149.790 49.755 150.135 ;
        RECT 49.925 149.960 50.290 150.425 ;
        RECT 50.515 150.255 50.715 150.925 ;
        RECT 48.030 149.535 50.280 149.790 ;
        RECT 47.950 149.165 50.280 149.535 ;
        RECT 50.460 149.375 50.715 150.255 ;
        RECT 51.015 150.900 51.490 151.805 ;
        RECT 51.670 151.510 53.640 152.555 ;
        RECT 53.820 151.975 54.075 152.555 ;
        RECT 53.820 151.805 54.105 151.975 ;
        RECT 51.670 151.080 53.115 151.510 ;
        RECT 51.015 150.730 52.905 150.900 ;
        RECT 53.285 150.755 53.650 151.340 ;
        RECT 53.820 150.925 54.075 151.805 ;
        RECT 61.010 150.975 61.600 152.555 ;
        RECT 61.880 150.975 62.265 152.555 ;
        RECT 62.450 150.975 63.040 152.555 ;
        RECT 63.320 151.295 63.705 152.555 ;
        RECT 63.285 151.125 63.705 151.295 ;
        RECT 63.320 150.975 63.705 151.125 ;
        RECT 63.890 150.975 64.480 152.555 ;
        RECT 64.760 151.295 65.145 152.555 ;
        RECT 64.760 151.125 65.155 151.295 ;
        RECT 64.760 150.975 65.145 151.125 ;
        RECT 66.290 150.975 66.880 152.555 ;
        RECT 67.160 150.975 67.545 152.555 ;
        RECT 68.695 152.425 75.625 152.595 ;
        RECT 68.695 151.245 69.585 152.425 ;
        RECT 51.015 150.135 51.185 150.730 ;
        RECT 51.355 150.305 52.145 150.550 ;
        RECT 52.315 150.525 52.905 150.730 ;
        RECT 53.115 150.425 53.705 150.755 ;
        RECT 51.015 149.705 51.220 150.135 ;
        RECT 51.390 149.790 53.115 150.135 ;
        RECT 53.285 149.960 53.650 150.425 ;
        RECT 53.875 150.255 54.075 150.925 ;
        RECT 61.045 150.350 61.755 150.735 ;
        RECT 51.390 149.535 53.640 149.790 ;
        RECT 51.310 149.165 53.640 149.535 ;
        RECT 53.820 149.375 54.075 150.255 ;
        RECT 61.010 149.165 61.600 150.125 ;
        RECT 61.935 149.295 62.265 150.975 ;
        RECT 62.485 150.350 63.195 150.735 ;
        RECT 62.450 149.165 63.040 150.125 ;
        RECT 63.375 149.295 63.705 150.975 ;
        RECT 63.925 150.350 64.635 150.735 ;
        RECT 63.890 149.165 64.480 150.125 ;
        RECT 64.815 149.295 65.145 150.975 ;
        RECT 66.325 150.350 67.035 150.735 ;
        RECT 66.290 149.165 66.880 150.125 ;
        RECT 67.215 149.295 67.545 150.975 ;
        RECT 69.875 151.005 70.205 152.245 ;
        RECT 70.375 151.185 71.265 152.425 ;
        RECT 71.435 151.005 71.765 152.245 ;
        RECT 71.935 151.185 72.825 152.425 ;
        RECT 72.995 151.005 73.325 152.245 ;
        RECT 73.495 151.185 74.385 152.425 ;
        RECT 74.555 151.005 74.885 152.245 ;
        RECT 75.055 151.185 75.625 152.425 ;
        RECT 75.895 152.425 82.825 152.595 ;
        RECT 75.895 151.245 76.785 152.425 ;
        RECT 77.075 151.005 77.405 152.245 ;
        RECT 77.575 151.185 78.465 152.425 ;
        RECT 78.635 151.005 78.965 152.245 ;
        RECT 79.135 151.185 80.025 152.425 ;
        RECT 80.195 151.005 80.525 152.245 ;
        RECT 80.695 151.185 81.585 152.425 ;
        RECT 81.755 151.005 82.085 152.245 ;
        RECT 82.255 151.185 82.825 152.425 ;
        RECT 69.875 150.835 75.710 151.005 ;
        RECT 77.075 150.835 82.910 151.005 ;
        RECT 68.910 150.380 75.360 150.615 ;
        RECT 75.540 150.275 75.710 150.835 ;
        RECT 76.110 150.380 82.560 150.615 ;
        RECT 69.795 150.195 74.825 150.200 ;
        RECT 75.525 150.195 75.710 150.275 ;
        RECT 68.695 149.350 69.585 150.185 ;
        RECT 69.795 150.030 75.710 150.195 ;
        RECT 76.995 150.195 82.025 150.200 ;
        RECT 82.740 150.195 82.910 150.835 ;
        RECT 69.795 149.530 70.005 150.030 ;
        RECT 70.175 149.350 71.185 149.845 ;
        RECT 71.355 149.530 71.565 150.030 ;
        RECT 71.735 149.350 72.745 149.845 ;
        RECT 72.915 149.530 73.125 150.030 ;
        RECT 74.515 150.025 75.710 150.030 ;
        RECT 73.295 149.350 74.345 149.845 ;
        RECT 74.515 149.530 75.165 150.025 ;
        RECT 75.335 149.350 75.705 149.845 ;
        RECT 68.695 149.180 75.705 149.350 ;
        RECT 75.895 149.350 76.785 150.185 ;
        RECT 76.995 150.030 82.910 150.195 ;
        RECT 76.995 149.530 77.205 150.030 ;
        RECT 77.375 149.350 78.385 149.845 ;
        RECT 78.555 149.530 78.765 150.030 ;
        RECT 78.935 149.350 79.945 149.845 ;
        RECT 80.115 149.530 80.325 150.030 ;
        RECT 81.715 150.025 82.910 150.030 ;
        RECT 111.495 150.900 111.970 151.805 ;
        RECT 112.150 151.510 114.120 152.555 ;
        RECT 114.300 151.975 114.555 152.555 ;
        RECT 114.300 151.805 114.625 151.975 ;
        RECT 112.150 151.080 113.595 151.510 ;
        RECT 111.495 150.730 113.385 150.900 ;
        RECT 113.765 150.755 114.130 151.340 ;
        RECT 114.300 150.925 114.555 151.805 ;
        RECT 111.495 150.135 111.665 150.730 ;
        RECT 111.835 150.305 112.625 150.550 ;
        RECT 112.795 150.525 113.385 150.730 ;
        RECT 113.595 150.425 114.185 150.755 ;
        RECT 80.495 149.350 81.545 149.845 ;
        RECT 81.715 149.530 82.365 150.025 ;
        RECT 82.535 149.350 82.905 149.845 ;
        RECT 111.495 149.705 111.700 150.135 ;
        RECT 111.870 149.790 113.595 150.135 ;
        RECT 113.765 149.960 114.130 150.425 ;
        RECT 114.355 150.255 114.555 150.925 ;
        RECT 111.870 149.535 114.120 149.790 ;
        RECT 75.895 149.180 82.905 149.350 ;
        RECT 111.790 149.165 114.120 149.535 ;
        RECT 114.300 149.375 114.555 150.255 ;
        RECT 114.855 150.900 115.330 151.805 ;
        RECT 115.510 151.510 117.480 152.555 ;
        RECT 115.510 151.080 116.955 151.510 ;
        RECT 114.855 150.730 116.745 150.900 ;
        RECT 117.125 150.755 117.490 151.340 ;
        RECT 117.660 150.925 117.915 152.555 ;
        RECT 114.855 150.135 115.025 150.730 ;
        RECT 115.195 150.305 115.985 150.550 ;
        RECT 116.155 150.525 116.745 150.730 ;
        RECT 116.955 150.425 117.545 150.755 ;
        RECT 114.855 149.705 115.060 150.135 ;
        RECT 115.230 149.790 116.955 150.135 ;
        RECT 117.125 149.960 117.490 150.425 ;
        RECT 117.715 150.255 117.915 150.925 ;
        RECT 115.230 149.535 117.480 149.790 ;
        RECT 115.150 149.165 117.480 149.535 ;
        RECT 117.660 149.375 117.915 150.255 ;
        RECT 118.215 150.900 118.690 151.805 ;
        RECT 118.870 151.510 120.840 152.555 ;
        RECT 118.870 151.080 120.315 151.510 ;
        RECT 118.215 150.730 120.105 150.900 ;
        RECT 120.485 150.755 120.850 151.340 ;
        RECT 121.020 150.925 121.275 152.555 ;
        RECT 118.215 150.135 118.385 150.730 ;
        RECT 118.555 150.305 119.345 150.550 ;
        RECT 119.515 150.525 120.105 150.730 ;
        RECT 120.315 150.425 120.905 150.755 ;
        RECT 118.215 149.705 118.420 150.135 ;
        RECT 118.590 149.790 120.315 150.135 ;
        RECT 120.485 149.960 120.850 150.425 ;
        RECT 121.075 150.255 121.275 150.925 ;
        RECT 118.590 149.535 120.840 149.790 ;
        RECT 118.510 149.165 120.840 149.535 ;
        RECT 121.020 149.375 121.275 150.255 ;
        RECT 121.575 150.900 122.050 151.805 ;
        RECT 122.230 151.510 124.200 152.555 ;
        RECT 122.230 151.080 123.675 151.510 ;
        RECT 121.575 150.730 123.465 150.900 ;
        RECT 123.845 150.755 124.210 151.340 ;
        RECT 124.380 150.925 124.635 152.555 ;
        RECT 121.575 150.135 121.745 150.730 ;
        RECT 121.915 150.305 122.705 150.550 ;
        RECT 122.875 150.525 123.465 150.730 ;
        RECT 123.675 150.425 124.265 150.755 ;
        RECT 121.575 149.705 121.780 150.135 ;
        RECT 121.950 149.790 123.675 150.135 ;
        RECT 123.845 149.960 124.210 150.425 ;
        RECT 124.435 150.255 124.635 150.925 ;
        RECT 124.380 149.935 124.635 150.255 ;
        RECT 121.950 149.535 124.200 149.790 ;
        RECT 121.870 149.165 124.200 149.535 ;
        RECT 124.380 149.765 124.655 149.935 ;
        RECT 124.380 149.375 124.635 149.765 ;
        RECT 40.280 148.715 59.960 148.885 ;
        RECT 60.920 148.715 65.240 148.885 ;
        RECT 66.200 148.715 67.640 148.885 ;
        RECT 68.120 148.715 83.000 148.885 ;
        RECT 111.320 148.715 127.160 148.885 ;
        RECT 40.750 148.065 43.080 148.435 ;
        RECT 40.455 147.465 40.660 147.895 ;
        RECT 40.830 147.810 43.080 148.065 ;
        RECT 40.830 147.465 42.555 147.810 ;
        RECT 40.455 146.870 40.625 147.465 ;
        RECT 40.795 147.050 41.585 147.295 ;
        RECT 42.725 147.175 43.090 147.640 ;
        RECT 43.260 147.345 43.515 148.225 ;
        RECT 44.110 148.065 46.440 148.435 ;
        RECT 40.845 147.045 41.015 147.050 ;
        RECT 41.755 146.870 42.345 147.075 ;
        RECT 40.455 146.700 42.345 146.870 ;
        RECT 42.555 146.845 43.145 147.175 ;
        RECT 40.455 145.795 40.930 146.700 ;
        RECT 41.110 146.090 42.555 146.520 ;
        RECT 42.725 146.260 43.090 146.845 ;
        RECT 43.315 146.675 43.515 147.345 ;
        RECT 41.110 145.045 43.080 146.090 ;
        RECT 43.260 145.855 43.515 146.675 ;
        RECT 43.815 147.465 44.020 147.895 ;
        RECT 44.190 147.810 46.440 148.065 ;
        RECT 44.190 147.465 45.915 147.810 ;
        RECT 43.815 146.870 43.985 147.465 ;
        RECT 44.155 147.050 44.945 147.295 ;
        RECT 46.085 147.215 46.450 147.640 ;
        RECT 46.620 147.345 46.875 148.225 ;
        RECT 47.470 148.065 49.800 148.435 ;
        RECT 52.855 148.250 59.865 148.420 ;
        RECT 46.085 147.175 46.455 147.215 ;
        RECT 44.245 147.045 44.415 147.050 ;
        RECT 45.115 146.870 45.705 147.075 ;
        RECT 43.815 146.700 45.705 146.870 ;
        RECT 45.915 146.845 46.505 147.175 ;
        RECT 43.260 145.685 43.565 145.855 ;
        RECT 43.815 145.795 44.290 146.700 ;
        RECT 44.470 146.090 45.915 146.520 ;
        RECT 46.085 146.260 46.450 146.845 ;
        RECT 46.675 146.675 46.875 147.345 ;
        RECT 43.260 145.045 43.515 145.685 ;
        RECT 44.470 145.045 46.440 146.090 ;
        RECT 46.620 145.045 46.875 146.675 ;
        RECT 47.175 147.465 47.380 147.895 ;
        RECT 47.550 147.810 49.800 148.065 ;
        RECT 47.550 147.465 49.275 147.810 ;
        RECT 47.175 146.870 47.345 147.465 ;
        RECT 47.515 147.050 48.305 147.295 ;
        RECT 49.445 147.215 49.810 147.640 ;
        RECT 49.980 147.345 50.235 148.225 ;
        RECT 52.855 147.415 53.745 148.250 ;
        RECT 53.955 147.570 54.165 148.070 ;
        RECT 54.335 147.755 55.345 148.250 ;
        RECT 55.515 147.570 55.725 148.070 ;
        RECT 55.895 147.755 56.905 148.250 ;
        RECT 57.075 147.570 57.285 148.070 ;
        RECT 57.455 147.755 58.505 148.250 ;
        RECT 58.675 147.575 59.325 148.070 ;
        RECT 59.495 147.755 59.865 148.250 ;
        RECT 58.675 147.570 59.870 147.575 ;
        RECT 53.955 147.405 59.870 147.570 ;
        RECT 63.410 147.475 64.000 148.435 ;
        RECT 64.335 147.895 64.665 148.305 ;
        RECT 64.305 147.725 64.665 147.895 ;
        RECT 53.955 147.400 58.985 147.405 ;
        RECT 49.345 147.175 49.810 147.215 ;
        RECT 47.645 147.045 47.815 147.050 ;
        RECT 48.475 146.870 49.065 147.075 ;
        RECT 47.175 146.700 49.065 146.870 ;
        RECT 49.275 146.845 49.865 147.175 ;
        RECT 47.175 145.795 47.650 146.700 ;
        RECT 47.830 146.090 49.275 146.520 ;
        RECT 49.445 146.260 49.810 146.845 ;
        RECT 50.035 146.675 50.235 147.345 ;
        RECT 53.070 146.985 59.520 147.220 ;
        RECT 59.700 146.765 59.870 147.405 ;
        RECT 63.445 146.865 64.155 147.250 ;
        RECT 47.830 145.045 49.800 146.090 ;
        RECT 49.980 145.045 50.235 146.675 ;
        RECT 54.035 146.595 59.870 146.765 ;
        RECT 64.335 146.625 64.665 147.725 ;
        RECT 68.215 148.250 75.225 148.420 ;
        RECT 68.215 147.415 69.105 148.250 ;
        RECT 69.315 147.570 69.525 148.070 ;
        RECT 69.695 147.755 70.705 148.250 ;
        RECT 70.875 147.570 71.085 148.070 ;
        RECT 71.255 147.755 72.265 148.250 ;
        RECT 72.435 147.570 72.645 148.070 ;
        RECT 72.815 147.755 73.865 148.250 ;
        RECT 74.035 147.575 74.685 148.070 ;
        RECT 74.855 147.755 75.225 148.250 ;
        RECT 117.550 148.065 119.880 148.435 ;
        RECT 74.035 147.570 75.230 147.575 ;
        RECT 69.315 147.405 75.230 147.570 ;
        RECT 69.315 147.400 74.345 147.405 ;
        RECT 68.430 146.985 74.880 147.220 ;
        RECT 75.060 146.765 75.230 147.405 ;
        RECT 52.855 145.175 53.745 146.355 ;
        RECT 54.035 145.355 54.365 146.595 ;
        RECT 54.535 145.175 55.425 146.415 ;
        RECT 55.595 145.355 55.925 146.595 ;
        RECT 56.095 145.175 56.985 146.415 ;
        RECT 57.155 145.355 57.485 146.595 ;
        RECT 57.655 145.175 58.545 146.415 ;
        RECT 58.715 145.355 59.045 146.595 ;
        RECT 59.215 145.175 59.785 146.415 ;
        RECT 52.855 145.005 59.785 145.175 ;
        RECT 63.410 145.045 64.000 146.625 ;
        RECT 64.280 145.045 64.665 146.625 ;
        RECT 69.395 146.595 75.230 146.765 ;
        RECT 117.255 147.465 117.460 147.895 ;
        RECT 117.630 147.810 119.880 148.065 ;
        RECT 117.630 147.465 119.355 147.810 ;
        RECT 117.255 146.870 117.425 147.465 ;
        RECT 117.595 147.050 118.385 147.295 ;
        RECT 119.525 147.215 119.890 147.640 ;
        RECT 120.060 147.345 120.315 148.225 ;
        RECT 120.910 148.065 123.240 148.435 ;
        RECT 119.525 147.175 119.895 147.215 ;
        RECT 118.025 147.045 118.195 147.050 ;
        RECT 118.555 146.870 119.145 147.075 ;
        RECT 117.255 146.700 119.145 146.870 ;
        RECT 119.355 146.845 119.945 147.175 ;
        RECT 68.215 145.175 69.105 146.355 ;
        RECT 69.395 145.355 69.725 146.595 ;
        RECT 69.895 145.175 70.785 146.415 ;
        RECT 70.955 145.355 71.285 146.595 ;
        RECT 71.455 145.175 72.345 146.415 ;
        RECT 72.515 145.355 72.845 146.595 ;
        RECT 73.015 145.175 73.905 146.415 ;
        RECT 74.075 145.355 74.405 146.595 ;
        RECT 74.575 145.175 75.145 146.415 ;
        RECT 117.255 145.795 117.730 146.700 ;
        RECT 117.910 146.090 119.355 146.520 ;
        RECT 119.525 146.260 119.890 146.845 ;
        RECT 120.115 146.675 120.315 147.345 ;
        RECT 68.215 145.005 75.145 145.175 ;
        RECT 117.910 145.045 119.880 146.090 ;
        RECT 120.060 145.045 120.315 146.675 ;
        RECT 120.615 147.465 120.820 147.895 ;
        RECT 120.990 147.810 123.240 148.065 ;
        RECT 120.990 147.465 122.715 147.810 ;
        RECT 120.615 146.870 120.785 147.465 ;
        RECT 120.955 147.050 121.745 147.295 ;
        RECT 122.885 147.215 123.250 147.640 ;
        RECT 123.420 147.345 123.675 148.225 ;
        RECT 124.270 148.065 126.600 148.435 ;
        RECT 122.785 147.175 123.250 147.215 ;
        RECT 121.085 147.045 121.255 147.050 ;
        RECT 121.915 146.870 122.505 147.075 ;
        RECT 120.615 146.700 122.505 146.870 ;
        RECT 122.715 146.845 123.305 147.175 ;
        RECT 120.615 145.795 121.090 146.700 ;
        RECT 121.270 146.090 122.715 146.520 ;
        RECT 122.885 146.260 123.250 146.845 ;
        RECT 123.475 146.675 123.675 147.345 ;
        RECT 121.270 145.045 123.240 146.090 ;
        RECT 123.420 145.045 123.675 146.675 ;
        RECT 123.975 147.465 124.180 147.895 ;
        RECT 124.350 147.810 126.600 148.065 ;
        RECT 124.350 147.465 126.075 147.810 ;
        RECT 123.975 146.870 124.145 147.465 ;
        RECT 124.315 147.050 125.105 147.295 ;
        RECT 126.245 147.175 126.610 147.640 ;
        RECT 126.780 147.345 127.035 148.225 ;
        RECT 124.485 147.045 124.655 147.050 ;
        RECT 125.275 146.870 125.865 147.075 ;
        RECT 123.975 146.700 125.865 146.870 ;
        RECT 126.075 146.845 126.665 147.175 ;
        RECT 126.185 146.705 126.610 146.845 ;
        RECT 123.975 145.795 124.450 146.700 ;
        RECT 124.630 146.090 126.075 146.520 ;
        RECT 126.245 146.260 126.610 146.705 ;
        RECT 126.835 146.675 127.035 147.345 ;
        RECT 124.630 145.045 126.600 146.090 ;
        RECT 126.780 145.045 127.035 146.675 ;
        RECT 40.280 144.645 52.280 144.815 ;
        RECT 52.760 144.645 67.640 144.815 ;
        RECT 68.120 144.645 81.560 144.815 ;
        RECT 116.120 144.645 127.160 144.815 ;
        RECT 40.455 142.760 40.930 143.665 ;
        RECT 41.110 143.370 43.080 144.415 ;
        RECT 41.110 142.940 42.555 143.370 ;
        RECT 40.455 142.590 42.345 142.760 ;
        RECT 42.725 142.615 43.090 143.200 ;
        RECT 43.260 142.785 43.515 144.415 ;
        RECT 40.455 141.995 40.625 142.590 ;
        RECT 40.795 142.165 41.585 142.410 ;
        RECT 41.755 142.385 42.345 142.590 ;
        RECT 42.555 142.285 43.145 142.615 ;
        RECT 40.455 141.565 40.660 141.995 ;
        RECT 40.830 141.650 42.555 141.995 ;
        RECT 42.725 141.820 43.090 142.285 ;
        RECT 43.315 142.115 43.515 142.785 ;
        RECT 43.260 141.775 43.515 142.115 ;
        RECT 43.815 142.760 44.290 143.665 ;
        RECT 44.470 143.370 46.440 144.415 ;
        RECT 44.470 142.940 45.915 143.370 ;
        RECT 43.815 142.590 45.705 142.760 ;
        RECT 46.085 142.615 46.450 143.200 ;
        RECT 46.620 142.785 46.875 144.415 ;
        RECT 43.815 141.995 43.985 142.590 ;
        RECT 44.155 142.165 44.945 142.410 ;
        RECT 45.115 142.385 45.705 142.590 ;
        RECT 45.915 142.285 46.505 142.615 ;
        RECT 40.830 141.395 43.080 141.650 ;
        RECT 40.750 141.025 43.080 141.395 ;
        RECT 43.260 141.605 43.565 141.775 ;
        RECT 43.260 141.235 43.515 141.605 ;
        RECT 43.815 141.565 44.020 141.995 ;
        RECT 44.190 141.650 45.915 141.995 ;
        RECT 46.085 141.820 46.450 142.285 ;
        RECT 46.675 142.115 46.875 142.785 ;
        RECT 44.190 141.395 46.440 141.650 ;
        RECT 44.110 141.025 46.440 141.395 ;
        RECT 46.620 141.235 46.875 142.115 ;
        RECT 49.095 142.760 49.570 143.665 ;
        RECT 49.750 143.370 51.720 144.415 ;
        RECT 49.750 142.940 51.195 143.370 ;
        RECT 49.095 142.590 50.985 142.760 ;
        RECT 51.365 142.615 51.730 143.200 ;
        RECT 51.900 142.785 52.155 144.415 ;
        RECT 53.335 144.285 60.265 144.455 ;
        RECT 53.335 143.105 54.225 144.285 ;
        RECT 49.095 141.995 49.265 142.590 ;
        RECT 49.435 142.165 50.225 142.410 ;
        RECT 50.395 142.385 50.985 142.590 ;
        RECT 51.195 142.285 51.785 142.615 ;
        RECT 51.955 142.455 52.155 142.785 ;
        RECT 54.515 142.865 54.845 144.105 ;
        RECT 55.015 143.045 55.905 144.285 ;
        RECT 56.075 142.865 56.405 144.105 ;
        RECT 56.575 143.045 57.465 144.285 ;
        RECT 57.635 142.865 57.965 144.105 ;
        RECT 58.135 143.045 59.025 144.285 ;
        RECT 59.195 142.865 59.525 144.105 ;
        RECT 59.695 143.045 60.265 144.285 ;
        RECT 60.535 144.285 67.465 144.455 ;
        RECT 60.535 143.105 61.425 144.285 ;
        RECT 61.715 142.865 62.045 144.105 ;
        RECT 62.215 143.045 63.105 144.285 ;
        RECT 63.275 142.865 63.605 144.105 ;
        RECT 63.775 143.045 64.665 144.285 ;
        RECT 64.835 142.865 65.165 144.105 ;
        RECT 65.335 143.045 66.225 144.285 ;
        RECT 66.395 142.865 66.725 144.105 ;
        RECT 66.895 143.045 67.465 144.285 ;
        RECT 74.455 144.285 81.385 144.455 ;
        RECT 74.455 143.105 75.345 144.285 ;
        RECT 75.635 142.865 75.965 144.105 ;
        RECT 76.135 143.045 77.025 144.285 ;
        RECT 77.195 142.865 77.525 144.105 ;
        RECT 77.695 143.045 78.585 144.285 ;
        RECT 78.755 142.865 79.085 144.105 ;
        RECT 79.255 143.045 80.145 144.285 ;
        RECT 80.315 142.865 80.645 144.105 ;
        RECT 80.815 143.045 81.385 144.285 ;
        RECT 54.515 142.695 60.350 142.865 ;
        RECT 61.715 142.695 67.550 142.865 ;
        RECT 75.635 142.695 81.470 142.865 ;
        RECT 51.955 142.285 52.235 142.455 ;
        RECT 49.095 141.565 49.300 141.995 ;
        RECT 49.470 141.650 51.195 141.995 ;
        RECT 51.365 141.820 51.730 142.285 ;
        RECT 51.955 142.115 52.155 142.285 ;
        RECT 53.550 142.240 60.000 142.475 ;
        RECT 60.180 142.455 60.350 142.695 ;
        RECT 60.180 142.285 60.395 142.455 ;
        RECT 49.470 141.395 51.720 141.650 ;
        RECT 49.390 141.025 51.720 141.395 ;
        RECT 51.900 141.235 52.155 142.115 ;
        RECT 54.435 142.055 59.465 142.060 ;
        RECT 60.180 142.055 60.350 142.285 ;
        RECT 60.750 142.240 67.200 142.475 ;
        RECT 53.335 141.210 54.225 142.045 ;
        RECT 54.435 141.890 60.350 142.055 ;
        RECT 61.635 142.055 66.665 142.060 ;
        RECT 67.380 142.055 67.550 142.695 ;
        RECT 74.670 142.240 81.120 142.475 ;
        RECT 54.435 141.390 54.645 141.890 ;
        RECT 54.815 141.210 55.825 141.705 ;
        RECT 55.995 141.390 56.205 141.890 ;
        RECT 56.375 141.210 57.385 141.705 ;
        RECT 57.555 141.390 57.765 141.890 ;
        RECT 59.155 141.885 60.350 141.890 ;
        RECT 57.935 141.210 58.985 141.705 ;
        RECT 59.155 141.390 59.805 141.885 ;
        RECT 59.975 141.210 60.345 141.705 ;
        RECT 53.335 141.040 60.345 141.210 ;
        RECT 60.535 141.210 61.425 142.045 ;
        RECT 61.635 141.890 67.550 142.055 ;
        RECT 75.555 142.055 80.585 142.060 ;
        RECT 81.300 142.055 81.470 142.695 ;
        RECT 61.635 141.390 61.845 141.890 ;
        RECT 62.015 141.210 63.025 141.705 ;
        RECT 63.195 141.390 63.405 141.890 ;
        RECT 63.575 141.210 64.585 141.705 ;
        RECT 64.755 141.390 64.965 141.890 ;
        RECT 66.355 141.885 67.550 141.890 ;
        RECT 65.135 141.210 66.185 141.705 ;
        RECT 66.355 141.390 67.005 141.885 ;
        RECT 67.175 141.210 67.545 141.705 ;
        RECT 60.535 141.040 67.545 141.210 ;
        RECT 74.455 141.210 75.345 142.045 ;
        RECT 75.555 141.890 81.470 142.055 ;
        RECT 75.555 141.390 75.765 141.890 ;
        RECT 75.935 141.210 76.945 141.705 ;
        RECT 77.115 141.390 77.325 141.890 ;
        RECT 77.495 141.210 78.505 141.705 ;
        RECT 78.675 141.390 78.885 141.890 ;
        RECT 80.275 141.885 81.470 141.890 ;
        RECT 116.295 142.760 116.770 143.665 ;
        RECT 116.950 143.370 118.920 144.415 ;
        RECT 116.950 142.940 118.395 143.370 ;
        RECT 116.295 142.590 118.185 142.760 ;
        RECT 118.565 142.615 118.930 143.200 ;
        RECT 119.100 142.795 119.355 144.415 ;
        RECT 119.100 142.785 119.385 142.795 ;
        RECT 119.155 142.625 119.385 142.785 ;
        RECT 119.655 142.760 120.130 143.665 ;
        RECT 120.310 143.370 122.280 144.415 ;
        RECT 120.310 142.940 121.755 143.370 ;
        RECT 116.295 141.995 116.465 142.590 ;
        RECT 116.635 142.165 117.425 142.410 ;
        RECT 117.595 142.385 118.185 142.590 ;
        RECT 118.395 142.285 118.985 142.615 ;
        RECT 79.055 141.210 80.105 141.705 ;
        RECT 80.275 141.390 80.925 141.885 ;
        RECT 81.095 141.210 81.465 141.705 ;
        RECT 116.295 141.565 116.500 141.995 ;
        RECT 116.670 141.650 118.395 141.995 ;
        RECT 118.565 141.820 118.930 142.285 ;
        RECT 119.155 142.115 119.355 142.625 ;
        RECT 116.670 141.395 118.920 141.650 ;
        RECT 74.455 141.040 81.465 141.210 ;
        RECT 116.590 141.025 118.920 141.395 ;
        RECT 119.100 141.235 119.355 142.115 ;
        RECT 119.655 142.590 121.545 142.760 ;
        RECT 121.925 142.615 122.290 143.200 ;
        RECT 122.460 142.785 122.715 144.415 ;
        RECT 119.655 141.995 119.825 142.590 ;
        RECT 119.995 142.165 120.785 142.410 ;
        RECT 120.955 142.385 121.545 142.590 ;
        RECT 121.755 142.285 122.345 142.615 ;
        RECT 119.655 141.565 119.860 141.995 ;
        RECT 120.030 141.650 121.755 141.995 ;
        RECT 121.925 141.820 122.290 142.285 ;
        RECT 122.515 142.115 122.715 142.785 ;
        RECT 122.460 141.775 122.715 142.115 ;
        RECT 123.015 142.760 123.490 143.665 ;
        RECT 123.670 143.370 125.640 144.415 ;
        RECT 123.670 142.940 125.115 143.370 ;
        RECT 123.015 142.590 124.905 142.760 ;
        RECT 125.285 142.615 125.650 143.200 ;
        RECT 125.820 142.785 126.075 144.415 ;
        RECT 123.015 141.995 123.185 142.590 ;
        RECT 123.355 142.165 124.145 142.410 ;
        RECT 124.315 142.385 124.905 142.590 ;
        RECT 125.115 142.285 125.705 142.615 ;
        RECT 120.030 141.395 122.280 141.650 ;
        RECT 119.950 141.025 122.280 141.395 ;
        RECT 122.460 141.605 122.785 141.775 ;
        RECT 122.460 141.235 122.715 141.605 ;
        RECT 123.015 141.565 123.220 141.995 ;
        RECT 123.390 141.650 125.115 141.995 ;
        RECT 125.285 141.820 125.650 142.285 ;
        RECT 125.875 142.115 126.075 142.785 ;
        RECT 123.390 141.395 125.640 141.650 ;
        RECT 123.310 141.025 125.640 141.395 ;
        RECT 125.820 141.235 126.075 142.115 ;
        RECT 40.280 140.575 52.280 140.745 ;
        RECT 53.240 140.575 69.560 140.745 ;
        RECT 72.440 140.575 81.560 140.745 ;
        RECT 116.120 140.575 126.200 140.745 ;
        RECT 40.750 139.925 43.080 140.295 ;
        RECT 40.455 139.325 40.660 139.755 ;
        RECT 40.830 139.670 43.080 139.925 ;
        RECT 40.830 139.325 42.555 139.670 ;
        RECT 40.455 138.730 40.625 139.325 ;
        RECT 40.795 138.910 41.585 139.155 ;
        RECT 42.725 139.035 43.090 139.500 ;
        RECT 43.260 139.205 43.515 140.085 ;
        RECT 45.070 139.925 47.400 140.295 ;
        RECT 41.755 138.730 42.345 138.935 ;
        RECT 40.455 138.560 42.345 138.730 ;
        RECT 42.555 138.705 43.145 139.035 ;
        RECT 40.455 137.655 40.930 138.560 ;
        RECT 41.110 137.950 42.555 138.380 ;
        RECT 42.725 138.120 43.090 138.705 ;
        RECT 43.315 138.535 43.515 139.205 ;
        RECT 44.245 138.545 44.415 139.395 ;
        RECT 44.775 139.325 44.980 139.755 ;
        RECT 45.150 139.670 47.400 139.925 ;
        RECT 45.150 139.325 46.875 139.670 ;
        RECT 44.775 138.730 44.945 139.325 ;
        RECT 45.115 138.910 45.905 139.155 ;
        RECT 47.045 139.035 47.410 139.500 ;
        RECT 47.580 139.205 47.835 140.085 ;
        RECT 48.430 139.925 50.760 140.295 ;
        RECT 62.455 140.110 69.465 140.280 ;
        RECT 46.075 138.730 46.665 138.935 ;
        RECT 44.775 138.560 46.665 138.730 ;
        RECT 46.875 138.705 47.465 139.035 ;
        RECT 41.110 136.905 43.080 137.950 ;
        RECT 43.260 137.695 43.515 138.535 ;
        RECT 43.260 137.525 43.565 137.695 ;
        RECT 44.775 137.655 45.250 138.560 ;
        RECT 46.965 138.545 47.410 138.705 ;
        RECT 45.430 137.950 46.875 138.380 ;
        RECT 47.045 138.120 47.410 138.545 ;
        RECT 47.635 138.535 47.835 139.205 ;
        RECT 43.260 136.905 43.515 137.525 ;
        RECT 45.430 136.905 47.400 137.950 ;
        RECT 47.580 136.905 47.835 138.535 ;
        RECT 48.135 139.325 48.340 139.755 ;
        RECT 48.510 139.670 50.760 139.925 ;
        RECT 48.510 139.325 50.235 139.670 ;
        RECT 48.135 138.730 48.305 139.325 ;
        RECT 48.475 138.910 49.265 139.155 ;
        RECT 50.405 139.035 50.770 139.500 ;
        RECT 50.940 139.205 51.195 140.085 ;
        RECT 62.455 139.275 63.345 140.110 ;
        RECT 63.555 139.430 63.765 139.930 ;
        RECT 63.935 139.615 64.945 140.110 ;
        RECT 65.115 139.430 65.325 139.930 ;
        RECT 65.495 139.615 66.505 140.110 ;
        RECT 66.675 139.430 66.885 139.930 ;
        RECT 67.055 139.615 68.105 140.110 ;
        RECT 68.275 139.435 68.925 139.930 ;
        RECT 69.095 139.615 69.465 140.110 ;
        RECT 72.535 140.110 79.545 140.280 ;
        RECT 68.275 139.430 69.470 139.435 ;
        RECT 63.555 139.265 69.470 139.430 ;
        RECT 72.535 139.275 73.425 140.110 ;
        RECT 73.635 139.430 73.845 139.930 ;
        RECT 74.015 139.615 75.025 140.110 ;
        RECT 75.195 139.430 75.405 139.930 ;
        RECT 75.575 139.615 76.585 140.110 ;
        RECT 76.755 139.430 76.965 139.930 ;
        RECT 77.135 139.615 78.185 140.110 ;
        RECT 78.355 139.435 79.005 139.930 ;
        RECT 79.175 139.615 79.545 140.110 ;
        RECT 118.510 139.925 120.840 140.295 ;
        RECT 78.355 139.430 79.550 139.435 ;
        RECT 63.555 139.260 68.585 139.265 ;
        RECT 49.435 138.730 50.025 138.935 ;
        RECT 48.135 138.560 50.025 138.730 ;
        RECT 50.235 138.705 50.825 139.035 ;
        RECT 48.135 137.655 48.610 138.560 ;
        RECT 50.365 138.545 50.770 138.705 ;
        RECT 48.790 137.950 50.235 138.380 ;
        RECT 50.405 138.120 50.770 138.545 ;
        RECT 50.995 138.535 51.195 139.205 ;
        RECT 62.670 138.845 69.120 139.080 ;
        RECT 69.300 138.625 69.470 139.265 ;
        RECT 73.635 139.265 79.550 139.430 ;
        RECT 73.635 139.260 78.665 139.265 ;
        RECT 50.940 138.375 51.195 138.535 ;
        RECT 63.635 138.455 69.470 138.625 ;
        RECT 50.940 138.205 51.215 138.375 ;
        RECT 48.790 136.905 50.760 137.950 ;
        RECT 50.940 136.905 51.195 138.205 ;
        RECT 62.455 137.035 63.345 138.215 ;
        RECT 63.635 137.215 63.965 138.455 ;
        RECT 64.135 137.035 65.025 138.275 ;
        RECT 65.195 137.215 65.525 138.455 ;
        RECT 65.695 137.035 66.585 138.275 ;
        RECT 66.755 137.215 67.085 138.455 ;
        RECT 67.255 137.035 68.145 138.275 ;
        RECT 68.315 137.215 68.645 138.455 ;
        RECT 68.815 137.035 69.385 138.275 ;
        RECT 62.455 136.865 69.385 137.035 ;
        RECT 37.880 136.505 51.320 136.675 ;
        RECT 62.360 136.505 70.040 136.675 ;
        RECT 38.055 134.620 38.530 135.525 ;
        RECT 38.710 135.230 40.680 136.275 ;
        RECT 38.710 134.800 40.155 135.230 ;
        RECT 38.055 134.450 39.945 134.620 ;
        RECT 40.325 134.475 40.690 135.060 ;
        RECT 40.860 134.645 41.115 136.275 ;
        RECT 40.915 134.635 41.115 134.645 ;
        RECT 38.055 133.855 38.225 134.450 ;
        RECT 38.395 134.025 39.185 134.270 ;
        RECT 39.355 134.245 39.945 134.450 ;
        RECT 40.155 134.145 40.745 134.475 ;
        RECT 40.915 134.465 41.185 134.635 ;
        RECT 41.415 134.620 41.890 135.525 ;
        RECT 42.070 135.230 44.040 136.275 ;
        RECT 42.070 134.800 43.515 135.230 ;
        RECT 38.055 133.425 38.260 133.855 ;
        RECT 38.430 133.510 40.155 133.855 ;
        RECT 40.325 133.680 40.690 134.145 ;
        RECT 40.915 133.975 41.115 134.465 ;
        RECT 38.430 133.255 40.680 133.510 ;
        RECT 38.350 132.885 40.680 133.255 ;
        RECT 40.860 133.095 41.115 133.975 ;
        RECT 41.415 134.450 43.305 134.620 ;
        RECT 43.685 134.475 44.050 135.060 ;
        RECT 44.220 134.645 44.475 136.275 ;
        RECT 41.415 133.855 41.585 134.450 ;
        RECT 41.755 134.025 42.545 134.270 ;
        RECT 42.715 134.245 43.305 134.450 ;
        RECT 43.515 134.145 44.105 134.475 ;
        RECT 43.565 134.125 44.050 134.145 ;
        RECT 41.415 133.425 41.620 133.855 ;
        RECT 41.790 133.510 43.515 133.855 ;
        RECT 43.685 133.680 44.050 134.125 ;
        RECT 44.275 133.975 44.475 134.645 ;
        RECT 41.790 133.255 44.040 133.510 ;
        RECT 41.710 132.885 44.040 133.255 ;
        RECT 44.220 133.095 44.475 133.975 ;
        RECT 44.775 134.620 45.250 135.525 ;
        RECT 45.430 135.230 47.400 136.275 ;
        RECT 45.430 134.800 46.875 135.230 ;
        RECT 47.045 134.635 47.410 135.060 ;
        RECT 47.580 134.645 47.835 136.275 ;
        RECT 62.935 136.145 69.865 136.315 ;
        RECT 62.935 134.965 63.825 136.145 ;
        RECT 44.775 134.450 46.665 134.620 ;
        RECT 46.965 134.475 47.410 134.635 ;
        RECT 44.775 133.855 44.945 134.450 ;
        RECT 45.115 134.025 45.905 134.270 ;
        RECT 46.075 134.245 46.665 134.450 ;
        RECT 46.875 134.145 47.465 134.475 ;
        RECT 44.775 133.425 44.980 133.855 ;
        RECT 45.150 133.510 46.875 133.855 ;
        RECT 47.045 133.680 47.410 134.145 ;
        RECT 47.635 133.975 47.835 134.645 ;
        RECT 64.115 134.725 64.445 135.965 ;
        RECT 64.615 134.905 65.505 136.145 ;
        RECT 65.675 134.725 66.005 135.965 ;
        RECT 66.175 134.905 67.065 136.145 ;
        RECT 67.235 134.725 67.565 135.965 ;
        RECT 67.735 134.905 68.625 136.145 ;
        RECT 68.795 134.725 69.125 135.965 ;
        RECT 69.295 134.905 69.865 136.145 ;
        RECT 64.115 134.555 69.950 134.725 ;
        RECT 69.745 134.465 69.950 134.555 ;
        RECT 70.425 134.465 70.595 139.055 ;
        RECT 72.750 138.845 79.200 139.080 ;
        RECT 79.380 138.625 79.550 139.265 ;
        RECT 118.215 139.325 118.420 139.755 ;
        RECT 118.590 139.670 120.840 139.925 ;
        RECT 118.590 139.325 120.315 139.670 ;
        RECT 73.715 138.455 79.550 138.625 ;
        RECT 72.535 137.035 73.425 138.215 ;
        RECT 73.715 137.215 74.045 138.455 ;
        RECT 74.215 137.035 75.105 138.275 ;
        RECT 75.275 137.215 75.605 138.455 ;
        RECT 75.775 137.035 76.665 138.275 ;
        RECT 76.835 137.215 77.165 138.455 ;
        RECT 77.335 137.035 78.225 138.275 ;
        RECT 78.395 137.215 78.725 138.455 ;
        RECT 78.895 137.035 79.465 138.275 ;
        RECT 72.535 136.865 79.465 137.035 ;
        RECT 71.960 136.505 79.640 136.675 ;
        RECT 72.055 136.145 78.985 136.315 ;
        RECT 72.055 134.965 72.945 136.145 ;
        RECT 73.235 134.725 73.565 135.965 ;
        RECT 73.735 134.905 74.625 136.145 ;
        RECT 74.795 134.725 75.125 135.965 ;
        RECT 75.295 134.905 76.185 136.145 ;
        RECT 76.355 134.725 76.685 135.965 ;
        RECT 76.855 134.905 77.745 136.145 ;
        RECT 77.915 134.725 78.245 135.965 ;
        RECT 78.415 134.905 78.985 136.145 ;
        RECT 73.235 134.635 79.070 134.725 ;
        RECT 73.235 134.555 79.095 134.635 ;
        RECT 78.900 134.465 79.095 134.555 ;
        RECT 79.945 134.465 80.115 139.055 ;
        RECT 118.215 138.730 118.385 139.325 ;
        RECT 118.555 138.910 119.345 139.155 ;
        RECT 120.485 139.035 120.850 139.500 ;
        RECT 121.020 139.205 121.275 140.085 ;
        RECT 121.870 139.925 124.200 140.295 ;
        RECT 119.515 138.730 120.105 138.935 ;
        RECT 118.215 138.560 120.105 138.730 ;
        RECT 120.315 138.705 120.905 139.035 ;
        RECT 118.215 137.655 118.690 138.560 ;
        RECT 120.405 138.545 120.850 138.705 ;
        RECT 118.870 137.950 120.315 138.380 ;
        RECT 120.485 138.120 120.850 138.545 ;
        RECT 121.075 138.535 121.275 139.205 ;
        RECT 118.870 136.905 120.840 137.950 ;
        RECT 121.020 136.905 121.275 138.535 ;
        RECT 121.575 139.325 121.780 139.755 ;
        RECT 121.950 139.670 124.200 139.925 ;
        RECT 121.950 139.325 123.675 139.670 ;
        RECT 121.575 138.730 121.745 139.325 ;
        RECT 121.915 138.910 122.705 139.155 ;
        RECT 123.845 139.035 124.210 139.500 ;
        RECT 124.380 139.205 124.635 140.085 ;
        RECT 122.875 138.730 123.465 138.935 ;
        RECT 121.575 138.560 123.465 138.730 ;
        RECT 123.675 138.705 124.265 139.035 ;
        RECT 121.575 137.655 122.050 138.560 ;
        RECT 123.805 138.545 124.210 138.705 ;
        RECT 122.230 137.950 123.675 138.380 ;
        RECT 123.845 138.120 124.210 138.545 ;
        RECT 124.435 138.535 124.635 139.205 ;
        RECT 122.230 136.905 124.200 137.950 ;
        RECT 124.380 137.695 124.635 138.535 ;
        RECT 124.380 137.525 124.655 137.695 ;
        RECT 124.380 136.905 124.635 137.525 ;
        RECT 111.320 136.505 124.760 136.675 ;
        RECT 111.495 134.620 111.970 135.525 ;
        RECT 112.150 135.230 114.120 136.275 ;
        RECT 114.300 135.655 114.555 136.275 ;
        RECT 114.300 135.485 114.625 135.655 ;
        RECT 112.150 134.800 113.595 135.230 ;
        RECT 63.150 134.100 69.600 134.335 ;
        RECT 45.150 133.255 47.400 133.510 ;
        RECT 45.070 132.885 47.400 133.255 ;
        RECT 47.580 133.095 47.835 133.975 ;
        RECT 64.035 133.915 69.065 133.920 ;
        RECT 69.780 133.915 69.950 134.465 ;
        RECT 72.270 134.100 78.720 134.335 ;
        RECT 62.935 133.070 63.825 133.905 ;
        RECT 64.035 133.750 69.950 133.915 ;
        RECT 73.155 133.915 78.185 133.920 ;
        RECT 78.900 133.915 79.070 134.465 ;
        RECT 64.035 133.250 64.245 133.750 ;
        RECT 64.415 133.070 65.425 133.565 ;
        RECT 65.595 133.250 65.805 133.750 ;
        RECT 65.975 133.070 66.985 133.565 ;
        RECT 67.155 133.250 67.365 133.750 ;
        RECT 68.755 133.745 69.950 133.750 ;
        RECT 67.535 133.070 68.585 133.565 ;
        RECT 68.755 133.250 69.405 133.745 ;
        RECT 69.575 133.070 69.945 133.565 ;
        RECT 62.935 132.900 69.945 133.070 ;
        RECT 72.055 133.070 72.945 133.905 ;
        RECT 73.155 133.750 79.070 133.915 ;
        RECT 73.155 133.250 73.365 133.750 ;
        RECT 73.535 133.070 74.545 133.565 ;
        RECT 74.715 133.250 74.925 133.750 ;
        RECT 75.095 133.070 76.105 133.565 ;
        RECT 76.275 133.250 76.485 133.750 ;
        RECT 77.875 133.745 79.070 133.750 ;
        RECT 111.495 134.450 113.385 134.620 ;
        RECT 113.765 134.475 114.130 135.060 ;
        RECT 114.300 134.645 114.555 135.485 ;
        RECT 111.495 133.855 111.665 134.450 ;
        RECT 111.835 134.025 112.625 134.270 ;
        RECT 112.795 134.245 113.385 134.450 ;
        RECT 113.595 134.145 114.185 134.475 ;
        RECT 76.655 133.070 77.705 133.565 ;
        RECT 77.875 133.250 78.525 133.745 ;
        RECT 78.695 133.070 79.065 133.565 ;
        RECT 111.495 133.425 111.700 133.855 ;
        RECT 111.870 133.510 113.595 133.855 ;
        RECT 113.765 133.680 114.130 134.145 ;
        RECT 114.355 133.975 114.555 134.645 ;
        RECT 111.870 133.255 114.120 133.510 ;
        RECT 72.055 132.900 79.065 133.070 ;
        RECT 111.790 132.885 114.120 133.255 ;
        RECT 114.300 133.095 114.555 133.975 ;
        RECT 114.855 134.620 115.330 135.525 ;
        RECT 115.510 135.230 117.480 136.275 ;
        RECT 115.510 134.800 116.955 135.230 ;
        RECT 114.855 134.450 116.745 134.620 ;
        RECT 117.125 134.475 117.490 135.060 ;
        RECT 117.660 134.645 117.915 136.275 ;
        RECT 114.855 133.855 115.025 134.450 ;
        RECT 115.195 134.025 115.985 134.270 ;
        RECT 116.155 134.245 116.745 134.450 ;
        RECT 116.955 134.145 117.545 134.475 ;
        RECT 117.005 134.125 117.490 134.145 ;
        RECT 114.855 133.425 115.060 133.855 ;
        RECT 115.230 133.510 116.955 133.855 ;
        RECT 117.125 133.680 117.490 134.125 ;
        RECT 117.715 133.975 117.915 134.645 ;
        RECT 115.230 133.255 117.480 133.510 ;
        RECT 115.150 132.885 117.480 133.255 ;
        RECT 117.660 133.095 117.915 133.975 ;
        RECT 118.215 134.620 118.690 135.525 ;
        RECT 118.870 135.230 120.840 136.275 ;
        RECT 118.870 134.800 120.315 135.230 ;
        RECT 120.485 134.635 120.850 135.060 ;
        RECT 121.020 134.645 121.275 136.275 ;
        RECT 118.215 134.450 120.105 134.620 ;
        RECT 120.405 134.475 120.850 134.635 ;
        RECT 118.215 133.855 118.385 134.450 ;
        RECT 118.555 134.025 119.345 134.270 ;
        RECT 119.515 134.245 120.105 134.450 ;
        RECT 120.315 134.145 120.905 134.475 ;
        RECT 118.215 133.425 118.420 133.855 ;
        RECT 118.590 133.510 120.315 133.855 ;
        RECT 120.485 133.680 120.850 134.145 ;
        RECT 121.075 133.975 121.275 134.645 ;
        RECT 118.590 133.255 120.840 133.510 ;
        RECT 118.510 132.885 120.840 133.255 ;
        RECT 121.020 133.095 121.275 133.975 ;
        RECT 121.575 134.620 122.050 135.525 ;
        RECT 122.230 135.230 124.200 136.275 ;
        RECT 122.230 134.800 123.675 135.230 ;
        RECT 121.575 134.450 123.465 134.620 ;
        RECT 123.845 134.475 124.210 135.060 ;
        RECT 124.380 134.645 124.635 136.275 ;
        RECT 121.575 133.855 121.745 134.450 ;
        RECT 121.915 134.025 122.705 134.270 ;
        RECT 122.875 134.245 123.465 134.450 ;
        RECT 123.675 134.145 124.265 134.475 ;
        RECT 123.805 134.125 124.210 134.145 ;
        RECT 121.575 133.425 121.780 133.855 ;
        RECT 121.950 133.510 123.675 133.855 ;
        RECT 123.845 133.680 124.210 134.125 ;
        RECT 124.435 133.975 124.635 134.645 ;
        RECT 124.380 133.615 124.635 133.975 ;
        RECT 121.950 133.255 124.200 133.510 ;
        RECT 121.870 132.885 124.200 133.255 ;
        RECT 124.380 133.445 124.655 133.615 ;
        RECT 124.380 133.095 124.635 133.445 ;
        RECT 37.880 132.435 47.960 132.605 ;
        RECT 62.840 132.435 70.040 132.605 ;
        RECT 71.960 132.435 79.160 132.605 ;
        RECT 111.320 132.435 124.760 132.605 ;
        RECT 40.750 131.785 43.080 132.155 ;
        RECT 40.455 131.185 40.660 131.615 ;
        RECT 40.830 131.530 43.080 131.785 ;
        RECT 40.830 131.185 42.555 131.530 ;
        RECT 39.825 106.415 39.995 130.975 ;
        RECT 40.455 130.590 40.625 131.185 ;
        RECT 40.795 130.770 41.585 131.015 ;
        RECT 42.725 130.895 43.090 131.360 ;
        RECT 43.260 131.065 43.515 131.945 ;
        RECT 44.110 131.785 46.440 132.155 ;
        RECT 41.755 130.590 42.345 130.795 ;
        RECT 40.455 130.420 42.345 130.590 ;
        RECT 42.555 130.565 43.145 130.895 ;
        RECT 40.455 129.515 40.930 130.420 ;
        RECT 41.110 129.810 42.555 130.240 ;
        RECT 42.725 129.980 43.090 130.565 ;
        RECT 43.315 130.395 43.515 131.065 ;
        RECT 41.110 128.765 43.080 129.810 ;
        RECT 43.260 129.535 43.515 130.395 ;
        RECT 43.815 131.185 44.020 131.615 ;
        RECT 44.190 131.530 46.440 131.785 ;
        RECT 44.190 131.185 45.915 131.530 ;
        RECT 43.815 130.590 43.985 131.185 ;
        RECT 44.155 130.770 44.945 131.015 ;
        RECT 46.085 130.895 46.450 131.360 ;
        RECT 46.620 131.065 46.875 131.945 ;
        RECT 118.510 131.785 120.840 132.155 ;
        RECT 45.115 130.590 45.705 130.795 ;
        RECT 43.815 130.420 45.705 130.590 ;
        RECT 45.915 130.565 46.505 130.895 ;
        RECT 43.260 129.365 43.565 129.535 ;
        RECT 43.815 129.515 44.290 130.420 ;
        RECT 44.470 129.810 45.915 130.240 ;
        RECT 46.085 129.980 46.450 130.565 ;
        RECT 46.675 130.395 46.875 131.065 ;
        RECT 43.260 128.765 43.515 129.365 ;
        RECT 44.470 128.765 46.440 129.810 ;
        RECT 46.620 128.765 46.875 130.395 ;
        RECT 118.215 131.185 118.420 131.615 ;
        RECT 118.590 131.530 120.840 131.785 ;
        RECT 118.590 131.185 120.315 131.530 ;
        RECT 118.215 130.590 118.385 131.185 ;
        RECT 118.555 130.770 119.345 131.015 ;
        RECT 120.485 130.895 120.850 131.360 ;
        RECT 121.020 131.065 121.275 131.945 ;
        RECT 121.870 131.785 124.200 132.155 ;
        RECT 119.515 130.590 120.105 130.795 ;
        RECT 118.215 130.420 120.105 130.590 ;
        RECT 120.315 130.565 120.905 130.895 ;
        RECT 118.215 129.515 118.690 130.420 ;
        RECT 118.870 129.810 120.315 130.240 ;
        RECT 120.485 129.980 120.850 130.565 ;
        RECT 121.075 130.395 121.275 131.065 ;
        RECT 118.870 128.765 120.840 129.810 ;
        RECT 121.020 128.765 121.275 130.395 ;
        RECT 121.575 131.185 121.780 131.615 ;
        RECT 121.950 131.530 124.200 131.785 ;
        RECT 121.950 131.185 123.675 131.530 ;
        RECT 121.575 130.590 121.745 131.185 ;
        RECT 121.915 130.770 122.705 131.015 ;
        RECT 123.845 130.895 124.210 131.360 ;
        RECT 124.380 131.065 124.635 131.945 ;
        RECT 122.875 130.590 123.465 130.795 ;
        RECT 121.575 130.420 123.465 130.590 ;
        RECT 123.675 130.565 124.265 130.895 ;
        RECT 121.575 129.515 122.050 130.420 ;
        RECT 122.230 129.810 123.675 130.240 ;
        RECT 123.845 129.980 124.210 130.565 ;
        RECT 124.435 130.395 124.635 131.065 ;
        RECT 122.230 128.765 124.200 129.810 ;
        RECT 124.380 129.535 124.635 130.395 ;
        RECT 124.380 129.365 124.655 129.535 ;
        RECT 124.380 128.765 124.635 129.365 ;
        RECT 40.280 128.365 54.200 128.535 ;
        RECT 118.040 128.365 124.760 128.535 ;
        RECT 44.295 126.480 44.770 127.385 ;
        RECT 44.950 127.090 46.920 128.135 ;
        RECT 44.950 126.660 46.395 127.090 ;
        RECT 44.295 126.310 46.185 126.480 ;
        RECT 46.565 126.335 46.930 126.920 ;
        RECT 47.100 126.505 47.355 128.135 ;
        RECT 44.295 125.715 44.465 126.310 ;
        RECT 44.925 126.130 45.095 126.135 ;
        RECT 44.635 125.885 45.425 126.130 ;
        RECT 45.595 126.105 46.185 126.310 ;
        RECT 46.395 126.005 46.985 126.335 ;
        RECT 44.295 125.285 44.500 125.715 ;
        RECT 44.670 125.370 46.395 125.715 ;
        RECT 46.565 125.540 46.930 126.005 ;
        RECT 47.155 125.835 47.355 126.505 ;
        RECT 44.670 125.115 46.920 125.370 ;
        RECT 44.590 124.745 46.920 125.115 ;
        RECT 47.100 124.955 47.355 125.835 ;
        RECT 47.655 126.480 48.130 127.385 ;
        RECT 48.310 127.090 50.280 128.135 ;
        RECT 48.310 126.660 49.755 127.090 ;
        RECT 47.655 126.310 49.545 126.480 ;
        RECT 49.925 126.335 50.290 126.920 ;
        RECT 50.460 126.505 50.715 128.135 ;
        RECT 47.655 125.715 47.825 126.310 ;
        RECT 48.325 126.130 48.495 126.135 ;
        RECT 47.995 125.885 48.785 126.130 ;
        RECT 48.955 126.105 49.545 126.310 ;
        RECT 49.755 126.005 50.345 126.335 ;
        RECT 47.655 125.285 47.860 125.715 ;
        RECT 48.030 125.370 49.755 125.715 ;
        RECT 49.925 125.540 50.290 126.005 ;
        RECT 50.515 125.835 50.715 126.505 ;
        RECT 48.030 125.115 50.280 125.370 ;
        RECT 47.950 124.745 50.280 125.115 ;
        RECT 50.460 124.955 50.715 125.835 ;
        RECT 51.015 126.480 51.490 127.385 ;
        RECT 51.670 127.090 53.640 128.135 ;
        RECT 51.670 126.660 53.115 127.090 ;
        RECT 51.015 126.310 52.905 126.480 ;
        RECT 53.285 126.335 53.650 126.920 ;
        RECT 53.820 126.505 54.075 128.135 ;
        RECT 53.875 126.475 54.075 126.505 ;
        RECT 118.215 126.480 118.690 127.385 ;
        RECT 118.870 127.090 120.840 128.135 ;
        RECT 118.870 126.660 120.315 127.090 ;
        RECT 51.015 125.715 51.185 126.310 ;
        RECT 51.385 126.130 51.555 126.135 ;
        RECT 51.355 125.885 52.145 126.130 ;
        RECT 52.315 126.105 52.905 126.310 ;
        RECT 53.115 126.005 53.705 126.335 ;
        RECT 53.875 126.305 54.105 126.475 ;
        RECT 118.215 126.310 120.105 126.480 ;
        RECT 120.485 126.335 120.850 126.920 ;
        RECT 121.020 126.505 121.275 128.135 ;
        RECT 51.015 125.285 51.220 125.715 ;
        RECT 51.390 125.370 53.115 125.715 ;
        RECT 53.285 125.540 53.650 126.005 ;
        RECT 53.875 125.835 54.075 126.305 ;
        RECT 51.390 125.115 53.640 125.370 ;
        RECT 51.310 124.745 53.640 125.115 ;
        RECT 53.820 124.955 54.075 125.835 ;
        RECT 118.215 125.715 118.385 126.310 ;
        RECT 118.705 126.130 118.875 126.135 ;
        RECT 118.555 125.885 119.345 126.130 ;
        RECT 119.515 126.105 120.105 126.310 ;
        RECT 120.315 126.005 120.905 126.335 ;
        RECT 120.405 125.965 120.850 126.005 ;
        RECT 118.215 125.285 118.420 125.715 ;
        RECT 118.590 125.370 120.315 125.715 ;
        RECT 120.485 125.540 120.850 125.965 ;
        RECT 121.075 125.835 121.275 126.505 ;
        RECT 118.590 125.115 120.840 125.370 ;
        RECT 118.510 124.745 120.840 125.115 ;
        RECT 121.020 124.955 121.275 125.835 ;
        RECT 121.575 126.480 122.050 127.385 ;
        RECT 122.230 127.090 124.200 128.135 ;
        RECT 124.380 127.495 124.635 128.135 ;
        RECT 124.380 127.325 124.655 127.495 ;
        RECT 122.230 126.660 123.675 127.090 ;
        RECT 121.575 126.310 123.465 126.480 ;
        RECT 123.845 126.335 124.210 126.920 ;
        RECT 124.380 126.505 124.635 127.325 ;
        RECT 121.575 125.715 121.745 126.310 ;
        RECT 122.105 126.130 122.275 126.135 ;
        RECT 121.915 125.885 122.705 126.130 ;
        RECT 122.875 126.105 123.465 126.310 ;
        RECT 123.675 126.005 124.265 126.335 ;
        RECT 123.805 125.965 124.210 126.005 ;
        RECT 121.575 125.285 121.780 125.715 ;
        RECT 121.950 125.370 123.675 125.715 ;
        RECT 123.845 125.540 124.210 125.965 ;
        RECT 124.435 125.835 124.635 126.505 ;
        RECT 121.950 125.115 124.200 125.370 ;
        RECT 121.870 124.745 124.200 125.115 ;
        RECT 124.380 124.955 124.635 125.835 ;
        RECT 40.280 124.295 54.200 124.465 ;
        RECT 115.160 124.295 125.240 124.465 ;
        RECT 40.750 123.645 43.080 124.015 ;
        RECT 40.455 123.045 40.660 123.475 ;
        RECT 40.830 123.390 43.080 123.645 ;
        RECT 43.260 123.415 43.515 123.805 ;
        RECT 44.110 123.645 46.440 124.015 ;
        RECT 40.830 123.045 42.555 123.390 ;
        RECT 43.260 123.245 43.565 123.415 ;
        RECT 40.455 122.450 40.625 123.045 ;
        RECT 40.795 122.630 41.585 122.875 ;
        RECT 42.725 122.755 43.090 123.220 ;
        RECT 43.260 122.925 43.515 123.245 ;
        RECT 41.755 122.450 42.345 122.655 ;
        RECT 40.455 122.280 42.345 122.450 ;
        RECT 42.555 122.425 43.145 122.755 ;
        RECT 40.455 121.375 40.930 122.280 ;
        RECT 41.110 121.670 42.555 122.100 ;
        RECT 42.725 121.840 43.090 122.425 ;
        RECT 43.315 122.255 43.515 122.925 ;
        RECT 41.110 120.625 43.080 121.670 ;
        RECT 43.260 120.625 43.515 122.255 ;
        RECT 43.815 123.045 44.020 123.475 ;
        RECT 44.190 123.390 46.440 123.645 ;
        RECT 44.190 123.045 45.915 123.390 ;
        RECT 43.815 122.450 43.985 123.045 ;
        RECT 44.155 122.630 44.945 122.875 ;
        RECT 46.085 122.755 46.450 123.220 ;
        RECT 46.620 122.925 46.875 123.805 ;
        RECT 115.630 123.645 117.960 124.015 ;
        RECT 45.115 122.450 45.705 122.655 ;
        RECT 43.815 122.280 45.705 122.450 ;
        RECT 45.915 122.425 46.505 122.755 ;
        RECT 43.815 121.375 44.290 122.280 ;
        RECT 44.470 121.670 45.915 122.100 ;
        RECT 46.085 121.840 46.450 122.425 ;
        RECT 46.675 122.255 46.875 122.925 ;
        RECT 44.470 120.625 46.440 121.670 ;
        RECT 46.620 120.625 46.875 122.255 ;
        RECT 115.335 123.045 115.540 123.475 ;
        RECT 115.710 123.390 117.960 123.645 ;
        RECT 115.710 123.045 117.435 123.390 ;
        RECT 115.335 122.450 115.505 123.045 ;
        RECT 115.675 122.630 116.465 122.875 ;
        RECT 117.605 122.755 117.970 123.220 ;
        RECT 118.140 122.925 118.395 123.805 ;
        RECT 118.990 123.645 121.320 124.015 ;
        RECT 116.635 122.450 117.225 122.655 ;
        RECT 115.335 122.280 117.225 122.450 ;
        RECT 117.435 122.425 118.025 122.755 ;
        RECT 115.335 121.375 115.810 122.280 ;
        RECT 115.990 121.670 117.435 122.100 ;
        RECT 117.605 121.840 117.970 122.425 ;
        RECT 118.195 122.255 118.395 122.925 ;
        RECT 115.990 120.625 117.960 121.670 ;
        RECT 118.140 120.625 118.395 122.255 ;
        RECT 118.695 123.045 118.900 123.475 ;
        RECT 119.070 123.390 121.320 123.645 ;
        RECT 119.070 123.045 120.795 123.390 ;
        RECT 118.695 122.450 118.865 123.045 ;
        RECT 119.035 122.630 119.825 122.875 ;
        RECT 120.965 122.755 121.330 123.220 ;
        RECT 121.500 122.925 121.755 123.805 ;
        RECT 122.350 123.645 124.680 124.015 ;
        RECT 119.995 122.450 120.585 122.655 ;
        RECT 118.695 122.280 120.585 122.450 ;
        RECT 120.795 122.425 121.385 122.755 ;
        RECT 118.695 121.375 119.170 122.280 ;
        RECT 119.350 121.670 120.795 122.100 ;
        RECT 120.965 121.840 121.330 122.425 ;
        RECT 121.555 122.255 121.755 122.925 ;
        RECT 119.350 120.625 121.320 121.670 ;
        RECT 121.500 121.375 121.755 122.255 ;
        RECT 122.055 123.045 122.260 123.475 ;
        RECT 122.430 123.390 124.680 123.645 ;
        RECT 124.860 123.415 125.115 123.805 ;
        RECT 122.430 123.045 124.155 123.390 ;
        RECT 124.860 123.245 125.165 123.415 ;
        RECT 122.055 122.450 122.225 123.045 ;
        RECT 122.395 122.630 123.185 122.875 ;
        RECT 124.325 122.755 124.690 123.220 ;
        RECT 124.860 122.925 125.115 123.245 ;
        RECT 123.355 122.450 123.945 122.655 ;
        RECT 122.055 122.280 123.945 122.450 ;
        RECT 124.155 122.425 124.745 122.755 ;
        RECT 122.055 121.375 122.530 122.280 ;
        RECT 122.710 121.670 124.155 122.100 ;
        RECT 124.325 121.840 124.690 122.425 ;
        RECT 124.915 122.255 125.115 122.925 ;
        RECT 121.500 121.205 121.765 121.375 ;
        RECT 121.500 120.625 121.755 121.205 ;
        RECT 122.710 120.625 124.680 121.670 ;
        RECT 124.860 120.625 125.115 122.255 ;
        RECT 40.280 120.225 50.840 120.395 ;
        RECT 114.680 120.225 125.240 120.395 ;
        RECT 40.165 113.725 40.335 118.655 ;
        RECT 40.935 118.340 41.410 119.245 ;
        RECT 41.590 118.950 43.560 119.995 ;
        RECT 41.590 118.520 43.035 118.950 ;
        RECT 40.935 118.170 42.825 118.340 ;
        RECT 43.205 118.195 43.570 118.780 ;
        RECT 43.740 118.365 43.995 119.995 ;
        RECT 40.935 117.575 41.105 118.170 ;
        RECT 41.275 117.745 42.065 117.990 ;
        RECT 42.235 117.965 42.825 118.170 ;
        RECT 43.035 117.865 43.625 118.195 ;
        RECT 40.935 117.145 41.140 117.575 ;
        RECT 41.310 117.230 43.035 117.575 ;
        RECT 43.205 117.400 43.570 117.865 ;
        RECT 43.795 117.695 43.995 118.365 ;
        RECT 43.740 117.295 43.995 117.695 ;
        RECT 44.295 118.340 44.770 119.245 ;
        RECT 44.950 118.950 46.920 119.995 ;
        RECT 44.950 118.520 46.395 118.950 ;
        RECT 44.295 118.170 46.185 118.340 ;
        RECT 46.565 118.195 46.930 118.780 ;
        RECT 47.100 118.365 47.355 119.995 ;
        RECT 44.295 117.575 44.465 118.170 ;
        RECT 44.635 117.745 45.425 117.990 ;
        RECT 45.595 117.965 46.185 118.170 ;
        RECT 46.395 117.865 46.985 118.195 ;
        RECT 41.310 116.975 43.560 117.230 ;
        RECT 41.230 116.605 43.560 116.975 ;
        RECT 43.740 117.125 44.075 117.295 ;
        RECT 44.295 117.145 44.500 117.575 ;
        RECT 44.670 117.230 46.395 117.575 ;
        RECT 46.565 117.400 46.930 117.865 ;
        RECT 47.155 117.695 47.355 118.365 ;
        RECT 43.740 116.815 43.995 117.125 ;
        RECT 44.670 116.975 46.920 117.230 ;
        RECT 44.590 116.605 46.920 116.975 ;
        RECT 47.100 116.815 47.355 117.695 ;
        RECT 47.655 118.340 48.130 119.245 ;
        RECT 48.310 118.950 50.280 119.995 ;
        RECT 48.310 118.520 49.755 118.950 ;
        RECT 47.655 118.170 49.545 118.340 ;
        RECT 49.925 118.195 50.290 118.780 ;
        RECT 50.460 118.365 50.715 119.995 ;
        RECT 47.655 117.575 47.825 118.170 ;
        RECT 47.995 117.745 48.785 117.990 ;
        RECT 48.955 117.965 49.545 118.170 ;
        RECT 49.755 117.865 50.345 118.195 ;
        RECT 47.655 117.145 47.860 117.575 ;
        RECT 48.030 117.230 49.755 117.575 ;
        RECT 49.925 117.400 50.290 117.865 ;
        RECT 50.515 117.695 50.715 118.365 ;
        RECT 48.030 116.975 50.280 117.230 ;
        RECT 47.950 116.605 50.280 116.975 ;
        RECT 50.460 116.815 50.715 117.695 ;
        RECT 114.855 118.340 115.330 119.245 ;
        RECT 115.510 118.950 117.480 119.995 ;
        RECT 115.510 118.520 116.955 118.950 ;
        RECT 114.855 118.170 116.745 118.340 ;
        RECT 117.125 118.195 117.490 118.780 ;
        RECT 117.660 118.365 117.915 119.995 ;
        RECT 114.855 117.575 115.025 118.170 ;
        RECT 115.195 117.745 115.985 117.990 ;
        RECT 116.155 117.965 116.745 118.170 ;
        RECT 116.955 117.865 117.545 118.195 ;
        RECT 117.005 117.805 117.490 117.865 ;
        RECT 114.855 117.145 115.060 117.575 ;
        RECT 115.230 117.230 116.955 117.575 ;
        RECT 117.125 117.400 117.490 117.805 ;
        RECT 117.715 117.695 117.915 118.365 ;
        RECT 115.230 116.975 117.480 117.230 ;
        RECT 115.150 116.605 117.480 116.975 ;
        RECT 117.660 116.815 117.915 117.695 ;
        RECT 118.215 118.340 118.690 119.245 ;
        RECT 118.870 118.950 120.840 119.995 ;
        RECT 118.870 118.520 120.315 118.950 ;
        RECT 118.215 118.170 120.105 118.340 ;
        RECT 120.485 118.195 120.850 118.780 ;
        RECT 121.020 118.365 121.275 119.995 ;
        RECT 118.215 117.575 118.385 118.170 ;
        RECT 118.555 117.745 119.345 117.990 ;
        RECT 119.515 117.965 120.105 118.170 ;
        RECT 120.315 117.865 120.905 118.195 ;
        RECT 118.215 117.145 118.420 117.575 ;
        RECT 118.590 117.230 120.315 117.575 ;
        RECT 120.485 117.400 120.850 117.865 ;
        RECT 121.075 117.695 121.275 118.365 ;
        RECT 118.590 116.975 120.840 117.230 ;
        RECT 118.510 116.605 120.840 116.975 ;
        RECT 121.020 116.815 121.275 117.695 ;
        RECT 121.575 118.340 122.050 119.245 ;
        RECT 122.230 118.950 124.200 119.995 ;
        RECT 122.230 118.520 123.675 118.950 ;
        RECT 121.575 118.170 123.465 118.340 ;
        RECT 123.845 118.195 124.210 118.780 ;
        RECT 124.380 118.365 124.635 119.995 ;
        RECT 121.575 117.575 121.745 118.170 ;
        RECT 121.915 117.745 122.705 117.990 ;
        RECT 122.875 117.965 123.465 118.170 ;
        RECT 123.675 117.865 124.265 118.195 ;
        RECT 123.805 117.805 124.210 117.865 ;
        RECT 121.575 117.145 121.780 117.575 ;
        RECT 121.950 117.230 123.675 117.575 ;
        RECT 123.845 117.400 124.210 117.805 ;
        RECT 124.435 117.695 124.635 118.365 ;
        RECT 124.380 117.295 124.635 117.695 ;
        RECT 121.950 116.975 124.200 117.230 ;
        RECT 121.870 116.605 124.200 116.975 ;
        RECT 124.380 117.125 124.655 117.295 ;
        RECT 124.380 116.815 124.635 117.125 ;
        RECT 40.760 116.155 54.200 116.325 ;
        RECT 114.680 116.155 124.760 116.325 ;
        RECT 41.230 115.505 43.560 115.875 ;
        RECT 40.935 114.905 41.140 115.335 ;
        RECT 41.310 115.250 43.560 115.505 ;
        RECT 43.740 115.255 43.995 115.665 ;
        RECT 44.590 115.505 46.920 115.875 ;
        RECT 41.310 114.905 43.035 115.250 ;
        RECT 43.740 115.085 44.075 115.255 ;
        RECT 40.935 114.310 41.105 114.905 ;
        RECT 41.275 114.490 42.065 114.735 ;
        RECT 43.205 114.615 43.570 115.080 ;
        RECT 43.740 114.785 43.995 115.085 ;
        RECT 42.235 114.310 42.825 114.515 ;
        RECT 40.935 114.140 42.825 114.310 ;
        RECT 43.035 114.285 43.625 114.615 ;
        RECT 40.935 113.235 41.410 114.140 ;
        RECT 41.590 113.530 43.035 113.960 ;
        RECT 43.205 113.700 43.570 114.285 ;
        RECT 43.795 114.115 43.995 114.785 ;
        RECT 41.590 112.485 43.560 113.530 ;
        RECT 43.740 112.485 43.995 114.115 ;
        RECT 44.295 114.905 44.500 115.335 ;
        RECT 44.670 115.250 46.920 115.505 ;
        RECT 44.670 114.905 46.395 115.250 ;
        RECT 44.295 114.310 44.465 114.905 ;
        RECT 44.635 114.490 45.425 114.735 ;
        RECT 46.565 114.615 46.930 115.080 ;
        RECT 47.100 114.785 47.355 115.665 ;
        RECT 47.950 115.505 50.280 115.875 ;
        RECT 45.595 114.310 46.185 114.515 ;
        RECT 44.295 114.140 46.185 114.310 ;
        RECT 46.395 114.285 46.985 114.615 ;
        RECT 44.295 113.235 44.770 114.140 ;
        RECT 44.950 113.530 46.395 113.960 ;
        RECT 46.565 113.700 46.930 114.285 ;
        RECT 47.155 114.115 47.355 114.785 ;
        RECT 44.950 112.485 46.920 113.530 ;
        RECT 47.100 112.485 47.355 114.115 ;
        RECT 47.655 114.905 47.860 115.335 ;
        RECT 48.030 115.250 50.280 115.505 ;
        RECT 48.030 114.905 49.755 115.250 ;
        RECT 47.655 114.310 47.825 114.905 ;
        RECT 47.995 114.490 48.785 114.735 ;
        RECT 49.925 114.615 50.290 115.080 ;
        RECT 50.460 114.785 50.715 115.665 ;
        RECT 51.310 115.505 53.640 115.875 ;
        RECT 48.955 114.310 49.545 114.515 ;
        RECT 47.655 114.140 49.545 114.310 ;
        RECT 49.755 114.285 50.345 114.615 ;
        RECT 47.655 113.235 48.130 114.140 ;
        RECT 48.310 113.530 49.755 113.960 ;
        RECT 49.925 113.700 50.290 114.285 ;
        RECT 50.515 114.115 50.715 114.785 ;
        RECT 48.310 112.485 50.280 113.530 ;
        RECT 50.460 112.485 50.715 114.115 ;
        RECT 51.015 114.905 51.220 115.335 ;
        RECT 51.390 115.250 53.640 115.505 ;
        RECT 51.390 114.905 53.115 115.250 ;
        RECT 51.015 114.310 51.185 114.905 ;
        RECT 51.355 114.490 52.145 114.735 ;
        RECT 53.285 114.615 53.650 115.080 ;
        RECT 53.820 114.785 54.075 115.665 ;
        RECT 115.150 115.505 117.480 115.875 ;
        RECT 52.315 114.310 52.905 114.515 ;
        RECT 51.015 114.140 52.905 114.310 ;
        RECT 53.115 114.285 53.705 114.615 ;
        RECT 51.015 113.235 51.490 114.140 ;
        RECT 51.670 113.530 53.115 113.960 ;
        RECT 53.285 113.700 53.650 114.285 ;
        RECT 53.875 114.235 54.075 114.785 ;
        RECT 114.855 114.905 115.060 115.335 ;
        RECT 115.230 115.250 117.480 115.505 ;
        RECT 115.230 114.905 116.955 115.250 ;
        RECT 114.855 114.310 115.025 114.905 ;
        RECT 115.195 114.490 115.985 114.735 ;
        RECT 117.125 114.615 117.490 115.080 ;
        RECT 117.660 114.785 117.915 115.665 ;
        RECT 118.510 115.505 120.840 115.875 ;
        RECT 116.155 114.310 116.745 114.515 ;
        RECT 53.875 114.115 54.105 114.235 ;
        RECT 53.820 114.065 54.105 114.115 ;
        RECT 114.855 114.140 116.745 114.310 ;
        RECT 116.955 114.285 117.545 114.615 ;
        RECT 51.670 112.485 53.640 113.530 ;
        RECT 53.820 112.485 54.075 114.065 ;
        RECT 114.855 113.235 115.330 114.140 ;
        RECT 115.510 113.530 116.955 113.960 ;
        RECT 117.125 113.700 117.490 114.285 ;
        RECT 117.715 114.115 117.915 114.785 ;
        RECT 115.510 112.485 117.480 113.530 ;
        RECT 117.660 112.485 117.915 114.115 ;
        RECT 118.215 114.905 118.420 115.335 ;
        RECT 118.590 115.250 120.840 115.505 ;
        RECT 118.590 114.905 120.315 115.250 ;
        RECT 118.215 114.310 118.385 114.905 ;
        RECT 118.555 114.490 119.345 114.735 ;
        RECT 120.485 114.615 120.850 115.080 ;
        RECT 121.020 114.785 121.275 115.665 ;
        RECT 121.870 115.505 124.200 115.875 ;
        RECT 119.515 114.310 120.105 114.515 ;
        RECT 118.215 114.140 120.105 114.310 ;
        RECT 120.315 114.285 120.905 114.615 ;
        RECT 118.215 113.235 118.690 114.140 ;
        RECT 118.870 113.530 120.315 113.960 ;
        RECT 120.485 113.700 120.850 114.285 ;
        RECT 121.075 114.115 121.275 114.785 ;
        RECT 118.870 112.485 120.840 113.530 ;
        RECT 121.020 112.485 121.275 114.115 ;
        RECT 121.575 114.905 121.780 115.335 ;
        RECT 121.950 115.250 124.200 115.505 ;
        RECT 124.380 115.255 124.635 115.665 ;
        RECT 121.950 114.905 123.675 115.250 ;
        RECT 124.380 115.085 124.655 115.255 ;
        RECT 121.575 114.310 121.745 114.905 ;
        RECT 121.915 114.490 122.705 114.735 ;
        RECT 123.845 114.615 124.210 115.080 ;
        RECT 124.380 114.785 124.635 115.085 ;
        RECT 122.875 114.310 123.465 114.515 ;
        RECT 121.575 114.140 123.465 114.310 ;
        RECT 123.675 114.285 124.265 114.615 ;
        RECT 121.575 113.235 122.050 114.140 ;
        RECT 122.230 113.530 123.675 113.960 ;
        RECT 123.845 113.700 124.210 114.285 ;
        RECT 124.435 114.115 124.635 114.785 ;
        RECT 122.230 112.485 124.200 113.530 ;
        RECT 124.380 112.485 124.635 114.115 ;
        RECT 40.280 112.085 54.200 112.255 ;
        RECT 114.680 112.085 125.240 112.255 ;
        RECT 40.455 110.200 40.930 111.105 ;
        RECT 41.110 110.810 43.080 111.855 ;
        RECT 41.110 110.380 42.555 110.810 ;
        RECT 40.455 110.030 42.345 110.200 ;
        RECT 42.725 110.055 43.090 110.640 ;
        RECT 43.260 110.495 43.515 111.855 ;
        RECT 43.260 110.325 43.565 110.495 ;
        RECT 43.260 110.225 43.515 110.325 ;
        RECT 40.455 109.435 40.625 110.030 ;
        RECT 40.795 109.605 41.585 109.850 ;
        RECT 41.755 109.825 42.345 110.030 ;
        RECT 42.555 109.725 43.145 110.055 ;
        RECT 40.455 109.005 40.660 109.435 ;
        RECT 40.830 109.090 42.555 109.435 ;
        RECT 42.725 109.260 43.090 109.725 ;
        RECT 43.315 109.555 43.515 110.225 ;
        RECT 40.830 108.835 43.080 109.090 ;
        RECT 40.750 108.465 43.080 108.835 ;
        RECT 43.260 108.675 43.515 109.555 ;
        RECT 43.815 110.200 44.290 111.105 ;
        RECT 44.470 110.810 46.440 111.855 ;
        RECT 44.470 110.380 45.915 110.810 ;
        RECT 43.815 110.030 45.705 110.200 ;
        RECT 46.085 110.155 46.450 110.640 ;
        RECT 46.620 110.225 46.875 111.855 ;
        RECT 46.085 110.055 46.455 110.155 ;
        RECT 43.815 109.435 43.985 110.030 ;
        RECT 44.155 109.605 44.945 109.850 ;
        RECT 45.115 109.825 45.705 110.030 ;
        RECT 45.915 109.725 46.505 110.055 ;
        RECT 43.815 109.005 44.020 109.435 ;
        RECT 44.190 109.090 45.915 109.435 ;
        RECT 46.085 109.260 46.450 109.725 ;
        RECT 46.675 109.555 46.875 110.225 ;
        RECT 115.335 110.200 115.810 111.105 ;
        RECT 115.990 110.810 117.960 111.855 ;
        RECT 115.990 110.380 117.435 110.810 ;
        RECT 115.335 110.030 117.225 110.200 ;
        RECT 117.605 110.055 117.970 110.640 ;
        RECT 118.140 110.225 118.395 111.855 ;
        RECT 44.190 108.835 46.440 109.090 ;
        RECT 44.110 108.465 46.440 108.835 ;
        RECT 46.620 108.675 46.875 109.555 ;
        RECT 40.280 108.015 53.240 108.185 ;
        RECT 40.750 107.365 43.080 107.735 ;
        RECT 40.455 106.765 40.660 107.195 ;
        RECT 40.830 107.110 43.080 107.365 ;
        RECT 40.830 106.765 42.555 107.110 ;
        RECT 43.260 107.095 43.515 107.525 ;
        RECT 46.990 107.365 49.320 107.735 ;
        RECT 40.455 106.170 40.625 106.765 ;
        RECT 40.795 106.350 41.585 106.595 ;
        RECT 42.725 106.475 43.090 106.940 ;
        RECT 43.260 106.925 43.565 107.095 ;
        RECT 43.260 106.645 43.515 106.925 ;
        RECT 46.695 106.765 46.900 107.195 ;
        RECT 47.070 107.110 49.320 107.365 ;
        RECT 47.070 106.765 48.795 107.110 ;
        RECT 41.755 106.170 42.345 106.375 ;
        RECT 40.455 106.000 42.345 106.170 ;
        RECT 42.555 106.145 43.145 106.475 ;
        RECT 40.455 105.095 40.930 106.000 ;
        RECT 41.110 105.390 42.555 105.820 ;
        RECT 42.725 105.560 43.090 106.145 ;
        RECT 43.315 105.975 43.515 106.645 ;
        RECT 41.110 104.345 43.080 105.390 ;
        RECT 43.260 104.345 43.515 105.975 ;
        RECT 40.280 103.945 43.640 104.115 ;
        RECT 40.455 102.060 40.930 102.965 ;
        RECT 41.110 102.670 43.080 103.715 ;
        RECT 43.260 103.015 43.515 103.715 ;
        RECT 43.260 102.845 43.565 103.015 ;
        RECT 41.110 102.240 42.555 102.670 ;
        RECT 40.455 101.890 42.345 102.060 ;
        RECT 42.725 101.915 43.090 102.500 ;
        RECT 43.260 102.085 43.515 102.845 ;
        RECT 40.455 101.295 40.625 101.890 ;
        RECT 40.795 101.465 41.585 101.710 ;
        RECT 41.755 101.685 42.345 101.890 ;
        RECT 42.555 101.585 43.145 101.915 ;
        RECT 40.455 100.865 40.660 101.295 ;
        RECT 40.830 100.950 42.555 101.295 ;
        RECT 42.725 101.120 43.090 101.585 ;
        RECT 43.315 101.415 43.515 102.085 ;
        RECT 40.830 100.695 43.080 100.950 ;
        RECT 40.750 100.325 43.080 100.695 ;
        RECT 43.260 100.535 43.515 101.415 ;
        RECT 43.905 101.145 44.075 106.755 ;
        RECT 46.695 106.170 46.865 106.765 ;
        RECT 47.035 106.350 47.825 106.595 ;
        RECT 48.965 106.475 49.330 106.940 ;
        RECT 49.500 106.645 49.755 107.525 ;
        RECT 50.350 107.365 52.680 107.735 ;
        RECT 47.995 106.170 48.585 106.375 ;
        RECT 46.695 106.000 48.585 106.170 ;
        RECT 48.795 106.145 49.385 106.475 ;
        RECT 46.695 105.095 47.170 106.000 ;
        RECT 47.350 105.390 48.795 105.820 ;
        RECT 48.965 105.560 49.330 106.145 ;
        RECT 49.555 105.975 49.755 106.645 ;
        RECT 47.350 104.345 49.320 105.390 ;
        RECT 49.500 104.345 49.755 105.975 ;
        RECT 50.055 106.765 50.260 107.195 ;
        RECT 50.430 107.110 52.680 107.365 ;
        RECT 50.430 106.765 52.155 107.110 ;
        RECT 50.055 106.170 50.225 106.765 ;
        RECT 50.395 106.350 51.185 106.595 ;
        RECT 52.325 106.475 52.690 106.940 ;
        RECT 52.860 106.645 53.115 107.525 ;
        RECT 51.355 106.170 51.945 106.375 ;
        RECT 50.055 106.000 51.945 106.170 ;
        RECT 52.155 106.145 52.745 106.475 ;
        RECT 50.055 105.095 50.530 106.000 ;
        RECT 50.710 105.390 52.155 105.820 ;
        RECT 52.325 105.560 52.690 106.145 ;
        RECT 52.915 105.975 53.115 106.645 ;
        RECT 50.710 104.345 52.680 105.390 ;
        RECT 52.860 104.345 53.115 105.975 ;
        RECT 45.080 103.945 53.240 104.115 ;
        RECT 45.255 102.060 45.730 102.965 ;
        RECT 45.910 102.670 47.880 103.715 ;
        RECT 45.910 102.240 47.355 102.670 ;
        RECT 45.255 101.890 47.145 102.060 ;
        RECT 47.525 101.915 47.890 102.500 ;
        RECT 48.060 102.085 48.315 103.715 ;
        RECT 48.115 101.995 48.315 102.085 ;
        RECT 45.255 101.295 45.425 101.890 ;
        RECT 45.595 101.465 46.385 101.710 ;
        RECT 46.555 101.685 47.145 101.890 ;
        RECT 47.355 101.585 47.945 101.915 ;
        RECT 48.115 101.825 48.325 101.995 ;
        RECT 45.255 100.865 45.460 101.295 ;
        RECT 45.630 100.950 47.355 101.295 ;
        RECT 47.525 101.120 47.890 101.585 ;
        RECT 48.115 101.415 48.315 101.825 ;
        RECT 45.630 100.695 47.880 100.950 ;
        RECT 45.550 100.325 47.880 100.695 ;
        RECT 48.060 100.535 48.315 101.415 ;
        RECT 40.280 99.875 50.360 100.045 ;
        RECT 40.750 99.225 43.080 99.595 ;
        RECT 40.455 98.625 40.660 99.055 ;
        RECT 40.830 98.970 43.080 99.225 ;
        RECT 40.830 98.625 42.555 98.970 ;
        RECT 43.260 98.935 43.515 99.385 ;
        RECT 44.110 99.225 46.440 99.595 ;
        RECT 40.455 98.030 40.625 98.625 ;
        RECT 40.795 98.210 41.585 98.455 ;
        RECT 42.725 98.335 43.090 98.800 ;
        RECT 43.260 98.765 43.565 98.935 ;
        RECT 43.260 98.505 43.515 98.765 ;
        RECT 41.755 98.030 42.345 98.235 ;
        RECT 40.455 97.860 42.345 98.030 ;
        RECT 42.555 98.005 43.145 98.335 ;
        RECT 40.455 96.955 40.930 97.860 ;
        RECT 41.110 97.250 42.555 97.680 ;
        RECT 42.725 97.420 43.090 98.005 ;
        RECT 43.315 97.835 43.515 98.505 ;
        RECT 41.110 96.205 43.080 97.250 ;
        RECT 43.260 96.205 43.515 97.835 ;
        RECT 43.815 98.625 44.020 99.055 ;
        RECT 44.190 98.970 46.440 99.225 ;
        RECT 44.190 98.625 45.915 98.970 ;
        RECT 43.815 98.030 43.985 98.625 ;
        RECT 44.155 98.210 44.945 98.455 ;
        RECT 46.085 98.335 46.450 98.800 ;
        RECT 46.620 98.505 46.875 99.385 ;
        RECT 47.470 99.225 49.800 99.595 ;
        RECT 45.115 98.030 45.705 98.235 ;
        RECT 43.815 97.860 45.705 98.030 ;
        RECT 45.915 98.005 46.505 98.335 ;
        RECT 43.815 96.955 44.290 97.860 ;
        RECT 44.470 97.250 45.915 97.680 ;
        RECT 46.085 97.420 46.450 98.005 ;
        RECT 46.675 97.835 46.875 98.505 ;
        RECT 44.470 96.205 46.440 97.250 ;
        RECT 46.620 96.205 46.875 97.835 ;
        RECT 47.175 98.625 47.380 99.055 ;
        RECT 47.550 98.970 49.800 99.225 ;
        RECT 47.550 98.625 49.275 98.970 ;
        RECT 47.175 98.030 47.345 98.625 ;
        RECT 47.515 98.210 48.305 98.455 ;
        RECT 49.445 98.335 49.810 98.800 ;
        RECT 49.980 98.505 50.235 99.385 ;
        RECT 48.475 98.030 49.065 98.235 ;
        RECT 47.175 97.860 49.065 98.030 ;
        RECT 49.275 98.005 49.865 98.335 ;
        RECT 47.175 96.955 47.650 97.860 ;
        RECT 47.830 97.250 49.275 97.680 ;
        RECT 49.445 97.420 49.810 98.005 ;
        RECT 50.035 97.835 50.235 98.505 ;
        RECT 47.830 96.205 49.800 97.250 ;
        RECT 49.980 96.205 50.235 97.835 ;
        RECT 40.280 95.805 54.200 95.975 ;
        RECT 40.455 93.920 40.930 94.825 ;
        RECT 41.110 94.530 43.080 95.575 ;
        RECT 43.260 94.855 43.515 95.575 ;
        RECT 43.260 94.685 43.565 94.855 ;
        RECT 41.110 94.100 42.555 94.530 ;
        RECT 40.455 93.750 42.345 93.920 ;
        RECT 42.725 93.775 43.090 94.360 ;
        RECT 43.260 93.945 43.515 94.685 ;
        RECT 40.455 93.155 40.625 93.750 ;
        RECT 40.795 93.325 41.585 93.570 ;
        RECT 41.755 93.545 42.345 93.750 ;
        RECT 42.555 93.445 43.145 93.775 ;
        RECT 40.455 92.725 40.660 93.155 ;
        RECT 40.830 92.810 42.555 93.155 ;
        RECT 42.725 92.980 43.090 93.445 ;
        RECT 43.315 93.275 43.515 93.945 ;
        RECT 40.830 92.555 43.080 92.810 ;
        RECT 40.750 92.185 43.080 92.555 ;
        RECT 43.260 92.395 43.515 93.275 ;
        RECT 44.295 93.920 44.770 94.825 ;
        RECT 44.950 94.530 46.920 95.575 ;
        RECT 44.950 94.100 46.395 94.530 ;
        RECT 44.295 93.750 46.185 93.920 ;
        RECT 46.565 93.775 46.930 94.360 ;
        RECT 47.100 93.945 47.355 95.575 ;
        RECT 44.295 93.155 44.465 93.750 ;
        RECT 44.635 93.325 45.425 93.570 ;
        RECT 45.595 93.545 46.185 93.750 ;
        RECT 46.395 93.445 46.985 93.775 ;
        RECT 44.295 92.725 44.500 93.155 ;
        RECT 44.670 92.810 46.395 93.155 ;
        RECT 46.565 92.980 46.930 93.445 ;
        RECT 47.155 93.275 47.355 93.945 ;
        RECT 44.670 92.555 46.920 92.810 ;
        RECT 44.590 92.185 46.920 92.555 ;
        RECT 47.100 92.395 47.355 93.275 ;
        RECT 47.655 93.920 48.130 94.825 ;
        RECT 48.310 94.530 50.280 95.575 ;
        RECT 48.310 94.100 49.755 94.530 ;
        RECT 47.655 93.750 49.545 93.920 ;
        RECT 49.925 93.775 50.290 94.360 ;
        RECT 50.460 93.945 50.715 95.575 ;
        RECT 47.655 93.155 47.825 93.750 ;
        RECT 47.995 93.325 48.785 93.570 ;
        RECT 48.955 93.545 49.545 93.750 ;
        RECT 49.755 93.445 50.345 93.775 ;
        RECT 47.655 92.725 47.860 93.155 ;
        RECT 48.030 92.810 49.755 93.155 ;
        RECT 49.925 92.980 50.290 93.445 ;
        RECT 50.515 93.275 50.715 93.945 ;
        RECT 48.030 92.555 50.280 92.810 ;
        RECT 47.950 92.185 50.280 92.555 ;
        RECT 50.460 92.395 50.715 93.275 ;
        RECT 51.015 93.920 51.490 94.825 ;
        RECT 51.670 94.530 53.640 95.575 ;
        RECT 51.670 94.100 53.115 94.530 ;
        RECT 51.015 93.750 52.905 93.920 ;
        RECT 53.285 93.775 53.650 94.360 ;
        RECT 53.820 93.945 54.075 95.575 ;
        RECT 53.875 93.835 54.075 93.945 ;
        RECT 51.015 93.155 51.185 93.750 ;
        RECT 51.355 93.325 52.145 93.570 ;
        RECT 52.315 93.545 52.905 93.750 ;
        RECT 53.115 93.445 53.705 93.775 ;
        RECT 53.875 93.665 54.105 93.835 ;
        RECT 51.015 92.725 51.220 93.155 ;
        RECT 51.390 92.810 53.115 93.155 ;
        RECT 53.285 92.980 53.650 93.445 ;
        RECT 53.875 93.275 54.075 93.665 ;
        RECT 51.390 92.555 53.640 92.810 ;
        RECT 51.310 92.185 53.640 92.555 ;
        RECT 53.820 92.395 54.075 93.275 ;
        RECT 40.280 91.735 54.200 91.905 ;
        RECT 40.750 91.085 43.080 91.455 ;
        RECT 40.455 90.485 40.660 90.915 ;
        RECT 40.830 90.830 43.080 91.085 ;
        RECT 40.830 90.485 42.555 90.830 ;
        RECT 40.455 89.890 40.625 90.485 ;
        RECT 40.795 90.070 41.585 90.315 ;
        RECT 42.725 90.195 43.090 90.660 ;
        RECT 43.260 90.365 43.515 91.245 ;
        RECT 44.110 91.085 46.440 91.455 ;
        RECT 41.755 89.890 42.345 90.095 ;
        RECT 40.455 89.720 42.345 89.890 ;
        RECT 42.555 89.865 43.145 90.195 ;
        RECT 40.455 88.815 40.930 89.720 ;
        RECT 41.110 89.110 42.555 89.540 ;
        RECT 42.725 89.280 43.090 89.865 ;
        RECT 43.315 89.695 43.515 90.365 ;
        RECT 41.110 88.065 43.080 89.110 ;
        RECT 43.260 88.735 43.515 89.695 ;
        RECT 43.815 90.485 44.020 90.915 ;
        RECT 44.190 90.830 46.440 91.085 ;
        RECT 44.190 90.485 45.915 90.830 ;
        RECT 43.815 89.890 43.985 90.485 ;
        RECT 44.155 90.070 44.945 90.315 ;
        RECT 46.085 90.195 46.450 90.660 ;
        RECT 46.620 90.365 46.875 91.245 ;
        RECT 47.470 91.085 49.800 91.455 ;
        RECT 45.115 89.890 45.705 90.095 ;
        RECT 43.815 89.720 45.705 89.890 ;
        RECT 45.915 89.865 46.505 90.195 ;
        RECT 43.815 88.815 44.290 89.720 ;
        RECT 44.470 89.110 45.915 89.540 ;
        RECT 46.085 89.280 46.450 89.865 ;
        RECT 46.675 89.695 46.875 90.365 ;
        RECT 43.260 88.565 43.565 88.735 ;
        RECT 43.260 88.065 43.515 88.565 ;
        RECT 44.470 88.065 46.440 89.110 ;
        RECT 46.620 88.065 46.875 89.695 ;
        RECT 47.175 90.485 47.380 90.915 ;
        RECT 47.550 90.830 49.800 91.085 ;
        RECT 47.550 90.485 49.275 90.830 ;
        RECT 47.175 89.890 47.345 90.485 ;
        RECT 47.515 90.070 48.305 90.315 ;
        RECT 49.445 90.195 49.810 90.660 ;
        RECT 49.980 90.365 50.235 91.245 ;
        RECT 48.475 89.890 49.065 90.095 ;
        RECT 47.175 89.720 49.065 89.890 ;
        RECT 49.275 89.865 49.865 90.195 ;
        RECT 47.175 88.815 47.650 89.720 ;
        RECT 47.830 89.110 49.275 89.540 ;
        RECT 49.445 89.280 49.810 89.865 ;
        RECT 50.035 89.695 50.235 90.365 ;
        RECT 113.265 89.925 113.435 109.815 ;
        RECT 115.335 109.435 115.505 110.030 ;
        RECT 115.675 109.605 116.465 109.850 ;
        RECT 116.635 109.825 117.225 110.030 ;
        RECT 117.435 109.725 118.025 110.055 ;
        RECT 115.335 109.005 115.540 109.435 ;
        RECT 115.710 109.090 117.435 109.435 ;
        RECT 117.605 109.260 117.970 109.725 ;
        RECT 118.195 109.555 118.395 110.225 ;
        RECT 115.710 108.835 117.960 109.090 ;
        RECT 115.630 108.465 117.960 108.835 ;
        RECT 118.140 108.675 118.395 109.555 ;
        RECT 118.695 110.200 119.170 111.105 ;
        RECT 119.350 110.810 121.320 111.855 ;
        RECT 119.350 110.380 120.795 110.810 ;
        RECT 118.695 110.030 120.585 110.200 ;
        RECT 120.965 110.055 121.330 110.640 ;
        RECT 121.500 110.225 121.755 111.855 ;
        RECT 118.695 109.435 118.865 110.030 ;
        RECT 119.035 109.605 119.825 109.850 ;
        RECT 119.995 109.825 120.585 110.030 ;
        RECT 120.795 109.725 121.385 110.055 ;
        RECT 118.695 109.005 118.900 109.435 ;
        RECT 119.070 109.090 120.795 109.435 ;
        RECT 120.965 109.260 121.330 109.725 ;
        RECT 121.555 109.555 121.755 110.225 ;
        RECT 121.500 109.135 121.755 109.555 ;
        RECT 122.055 110.200 122.530 111.105 ;
        RECT 122.710 110.810 124.680 111.855 ;
        RECT 122.710 110.380 124.155 110.810 ;
        RECT 122.055 110.030 123.945 110.200 ;
        RECT 124.325 110.055 124.690 110.640 ;
        RECT 124.860 110.495 125.115 111.855 ;
        RECT 124.860 110.325 125.165 110.495 ;
        RECT 124.860 110.225 125.115 110.325 ;
        RECT 122.055 109.435 122.225 110.030 ;
        RECT 122.395 109.605 123.185 109.850 ;
        RECT 123.355 109.825 123.945 110.030 ;
        RECT 124.155 109.725 124.745 110.055 ;
        RECT 119.070 108.835 121.320 109.090 ;
        RECT 118.990 108.465 121.320 108.835 ;
        RECT 121.500 108.965 121.765 109.135 ;
        RECT 122.055 109.005 122.260 109.435 ;
        RECT 122.430 109.090 124.155 109.435 ;
        RECT 124.325 109.260 124.690 109.725 ;
        RECT 124.915 109.555 125.115 110.225 ;
        RECT 121.500 108.675 121.755 108.965 ;
        RECT 122.430 108.835 124.680 109.090 ;
        RECT 122.350 108.465 124.680 108.835 ;
        RECT 124.860 108.675 125.115 109.555 ;
        RECT 113.720 108.015 125.240 108.185 ;
        RECT 114.190 107.365 116.520 107.735 ;
        RECT 113.895 106.765 114.100 107.195 ;
        RECT 114.270 107.110 116.520 107.365 ;
        RECT 114.270 106.765 115.995 107.110 ;
        RECT 116.700 107.095 116.955 107.525 ;
        RECT 118.510 107.365 120.840 107.735 ;
        RECT 113.895 106.170 114.065 106.765 ;
        RECT 114.235 106.350 115.025 106.595 ;
        RECT 116.165 106.475 116.530 106.940 ;
        RECT 116.700 106.925 117.005 107.095 ;
        RECT 116.700 106.645 116.955 106.925 ;
        RECT 115.195 106.170 115.785 106.375 ;
        RECT 113.895 106.000 115.785 106.170 ;
        RECT 115.995 106.145 116.585 106.475 ;
        RECT 113.895 105.095 114.370 106.000 ;
        RECT 114.550 105.390 115.995 105.820 ;
        RECT 116.165 105.560 116.530 106.145 ;
        RECT 116.755 105.975 116.955 106.645 ;
        RECT 114.550 104.345 116.520 105.390 ;
        RECT 116.700 104.345 116.955 105.975 ;
        RECT 118.215 106.765 118.420 107.195 ;
        RECT 118.590 107.110 120.840 107.365 ;
        RECT 118.590 106.765 120.315 107.110 ;
        RECT 118.215 106.170 118.385 106.765 ;
        RECT 118.555 106.350 119.345 106.595 ;
        RECT 120.485 106.475 120.850 106.940 ;
        RECT 121.020 106.645 121.275 107.525 ;
        RECT 121.870 107.365 124.200 107.735 ;
        RECT 119.515 106.170 120.105 106.375 ;
        RECT 118.215 106.000 120.105 106.170 ;
        RECT 120.315 106.145 120.905 106.475 ;
        RECT 118.215 105.095 118.690 106.000 ;
        RECT 118.870 105.390 120.315 105.820 ;
        RECT 120.485 105.560 120.850 106.145 ;
        RECT 121.075 105.975 121.275 106.645 ;
        RECT 118.870 104.345 120.840 105.390 ;
        RECT 121.020 104.345 121.275 105.975 ;
        RECT 121.575 106.765 121.780 107.195 ;
        RECT 121.950 107.110 124.200 107.365 ;
        RECT 121.950 106.765 123.675 107.110 ;
        RECT 124.380 107.095 124.635 107.525 ;
        RECT 121.575 106.170 121.745 106.765 ;
        RECT 121.915 106.350 122.705 106.595 ;
        RECT 123.845 106.475 124.210 106.940 ;
        RECT 124.380 106.925 124.655 107.095 ;
        RECT 124.380 106.645 124.635 106.925 ;
        RECT 122.875 106.170 123.465 106.375 ;
        RECT 121.575 106.000 123.465 106.170 ;
        RECT 123.675 106.145 124.265 106.475 ;
        RECT 121.575 105.095 122.050 106.000 ;
        RECT 122.230 105.390 123.675 105.820 ;
        RECT 123.845 105.560 124.210 106.145 ;
        RECT 124.435 105.975 124.635 106.645 ;
        RECT 122.230 104.345 124.200 105.390 ;
        RECT 124.380 104.345 124.635 105.975 ;
        RECT 113.720 103.945 124.760 104.115 ;
        RECT 114.855 102.060 115.330 102.965 ;
        RECT 115.510 102.670 117.480 103.715 ;
        RECT 115.510 102.240 116.955 102.670 ;
        RECT 114.855 101.890 116.745 102.060 ;
        RECT 117.125 101.995 117.490 102.500 ;
        RECT 117.660 102.085 117.915 103.715 ;
        RECT 117.005 101.915 117.490 101.995 ;
        RECT 114.855 101.295 115.025 101.890 ;
        RECT 115.195 101.465 115.985 101.710 ;
        RECT 116.155 101.685 116.745 101.890 ;
        RECT 116.955 101.585 117.545 101.915 ;
        RECT 114.855 100.865 115.060 101.295 ;
        RECT 115.230 100.950 116.955 101.295 ;
        RECT 117.125 101.120 117.490 101.585 ;
        RECT 117.715 101.415 117.915 102.085 ;
        RECT 115.230 100.695 117.480 100.950 ;
        RECT 115.150 100.325 117.480 100.695 ;
        RECT 117.660 100.535 117.915 101.415 ;
        RECT 118.215 102.060 118.690 102.965 ;
        RECT 118.870 102.670 120.840 103.715 ;
        RECT 118.870 102.240 120.315 102.670 ;
        RECT 118.215 101.890 120.105 102.060 ;
        RECT 120.485 101.995 120.850 102.500 ;
        RECT 121.020 102.085 121.275 103.715 ;
        RECT 120.405 101.915 120.850 101.995 ;
        RECT 118.215 101.295 118.385 101.890 ;
        RECT 118.555 101.465 119.345 101.710 ;
        RECT 119.515 101.685 120.105 101.890 ;
        RECT 120.315 101.585 120.905 101.915 ;
        RECT 118.215 100.865 118.420 101.295 ;
        RECT 118.590 100.950 120.315 101.295 ;
        RECT 120.485 101.120 120.850 101.585 ;
        RECT 121.075 101.415 121.275 102.085 ;
        RECT 118.590 100.695 120.840 100.950 ;
        RECT 118.510 100.325 120.840 100.695 ;
        RECT 121.020 100.535 121.275 101.415 ;
        RECT 121.575 102.060 122.050 102.965 ;
        RECT 122.230 102.670 124.200 103.715 ;
        RECT 124.380 103.015 124.635 103.715 ;
        RECT 124.380 102.845 124.655 103.015 ;
        RECT 122.230 102.240 123.675 102.670 ;
        RECT 121.575 101.890 123.465 102.060 ;
        RECT 123.845 101.995 124.210 102.500 ;
        RECT 124.380 102.085 124.635 102.845 ;
        RECT 123.805 101.915 124.210 101.995 ;
        RECT 121.575 101.295 121.745 101.890 ;
        RECT 121.915 101.465 122.705 101.710 ;
        RECT 122.875 101.685 123.465 101.890 ;
        RECT 123.675 101.585 124.265 101.915 ;
        RECT 121.575 100.865 121.780 101.295 ;
        RECT 121.950 100.950 123.675 101.295 ;
        RECT 123.845 101.120 124.210 101.585 ;
        RECT 124.435 101.415 124.635 102.085 ;
        RECT 121.950 100.695 124.200 100.950 ;
        RECT 121.870 100.325 124.200 100.695 ;
        RECT 124.380 100.535 124.635 101.415 ;
        RECT 114.200 99.875 124.760 100.045 ;
        RECT 114.670 99.225 117.000 99.595 ;
        RECT 114.375 98.625 114.580 99.055 ;
        RECT 114.750 98.970 117.000 99.225 ;
        RECT 114.750 98.625 116.475 98.970 ;
        RECT 114.375 98.030 114.545 98.625 ;
        RECT 114.715 98.210 115.505 98.455 ;
        RECT 116.645 98.335 117.010 98.800 ;
        RECT 117.180 98.505 117.435 99.385 ;
        RECT 118.510 99.225 120.840 99.595 ;
        RECT 115.675 98.030 116.265 98.235 ;
        RECT 114.375 97.860 116.265 98.030 ;
        RECT 116.475 98.005 117.065 98.335 ;
        RECT 114.375 96.955 114.850 97.860 ;
        RECT 115.030 97.250 116.475 97.680 ;
        RECT 116.645 97.420 117.010 98.005 ;
        RECT 117.235 97.835 117.435 98.505 ;
        RECT 115.030 96.205 117.000 97.250 ;
        RECT 117.180 96.895 117.435 97.835 ;
        RECT 118.215 98.625 118.420 99.055 ;
        RECT 118.590 98.970 120.840 99.225 ;
        RECT 118.590 98.625 120.315 98.970 ;
        RECT 118.215 98.030 118.385 98.625 ;
        RECT 118.555 98.210 119.345 98.455 ;
        RECT 120.485 98.335 120.850 98.800 ;
        RECT 121.020 98.505 121.275 99.385 ;
        RECT 121.870 99.225 124.200 99.595 ;
        RECT 119.515 98.030 120.105 98.235 ;
        RECT 118.215 97.860 120.105 98.030 ;
        RECT 120.315 98.005 120.905 98.335 ;
        RECT 118.215 96.955 118.690 97.860 ;
        RECT 118.870 97.250 120.315 97.680 ;
        RECT 120.485 97.420 120.850 98.005 ;
        RECT 121.075 97.835 121.275 98.505 ;
        RECT 117.180 96.725 117.515 96.895 ;
        RECT 117.180 96.205 117.435 96.725 ;
        RECT 118.870 96.205 120.840 97.250 ;
        RECT 121.020 96.205 121.275 97.835 ;
        RECT 121.575 98.625 121.780 99.055 ;
        RECT 121.950 98.970 124.200 99.225 ;
        RECT 121.950 98.625 123.675 98.970 ;
        RECT 124.380 98.935 124.635 99.385 ;
        RECT 121.575 98.030 121.745 98.625 ;
        RECT 121.915 98.210 122.705 98.455 ;
        RECT 123.845 98.335 124.210 98.800 ;
        RECT 124.380 98.765 124.655 98.935 ;
        RECT 124.380 98.505 124.635 98.765 ;
        RECT 122.875 98.030 123.465 98.235 ;
        RECT 121.575 97.860 123.465 98.030 ;
        RECT 123.675 98.005 124.265 98.335 ;
        RECT 121.575 96.955 122.050 97.860 ;
        RECT 122.230 97.250 123.675 97.680 ;
        RECT 123.845 97.420 124.210 98.005 ;
        RECT 124.435 97.835 124.635 98.505 ;
        RECT 122.230 96.205 124.200 97.250 ;
        RECT 124.380 96.205 124.635 97.835 ;
        RECT 113.720 95.805 124.760 95.975 ;
        RECT 113.895 93.920 114.370 94.825 ;
        RECT 114.550 94.530 116.520 95.575 ;
        RECT 116.700 94.855 116.955 95.575 ;
        RECT 116.700 94.685 117.005 94.855 ;
        RECT 114.550 94.100 115.995 94.530 ;
        RECT 113.895 93.750 115.785 93.920 ;
        RECT 116.165 93.775 116.530 94.360 ;
        RECT 116.700 93.945 116.955 94.685 ;
        RECT 113.895 93.155 114.065 93.750 ;
        RECT 114.235 93.325 115.025 93.570 ;
        RECT 115.195 93.545 115.785 93.750 ;
        RECT 115.995 93.445 116.585 93.775 ;
        RECT 113.895 92.725 114.100 93.155 ;
        RECT 114.270 92.810 115.995 93.155 ;
        RECT 116.165 92.980 116.530 93.445 ;
        RECT 116.755 93.275 116.955 93.945 ;
        RECT 114.270 92.555 116.520 92.810 ;
        RECT 114.190 92.185 116.520 92.555 ;
        RECT 116.700 92.395 116.955 93.275 ;
        RECT 117.735 93.920 118.210 94.825 ;
        RECT 118.390 94.530 120.360 95.575 ;
        RECT 118.390 94.100 119.835 94.530 ;
        RECT 117.735 93.750 119.625 93.920 ;
        RECT 120.005 93.775 120.370 94.360 ;
        RECT 120.540 93.945 120.795 95.575 ;
        RECT 117.735 93.155 117.905 93.750 ;
        RECT 118.075 93.325 118.865 93.570 ;
        RECT 119.035 93.545 119.625 93.750 ;
        RECT 119.835 93.445 120.425 93.775 ;
        RECT 117.735 92.725 117.940 93.155 ;
        RECT 118.110 92.810 119.835 93.155 ;
        RECT 120.005 92.980 120.370 93.445 ;
        RECT 120.595 93.275 120.795 93.945 ;
        RECT 118.110 92.555 120.360 92.810 ;
        RECT 118.030 92.185 120.360 92.555 ;
        RECT 120.540 92.395 120.795 93.275 ;
        RECT 121.095 93.920 121.570 94.825 ;
        RECT 121.750 94.530 123.720 95.575 ;
        RECT 121.750 94.100 123.195 94.530 ;
        RECT 121.095 93.750 122.985 93.920 ;
        RECT 123.365 93.775 123.730 94.360 ;
        RECT 123.900 93.945 124.155 95.575 ;
        RECT 121.095 93.155 121.265 93.750 ;
        RECT 121.435 93.325 122.225 93.570 ;
        RECT 122.395 93.545 122.985 93.750 ;
        RECT 123.195 93.445 123.785 93.775 ;
        RECT 121.095 92.725 121.300 93.155 ;
        RECT 121.470 92.810 123.195 93.155 ;
        RECT 123.365 92.980 123.730 93.445 ;
        RECT 123.955 93.275 124.155 93.945 ;
        RECT 121.470 92.555 123.720 92.810 ;
        RECT 121.390 92.185 123.720 92.555 ;
        RECT 123.900 92.395 124.155 93.275 ;
        RECT 113.720 91.735 124.760 91.905 ;
        RECT 115.150 91.085 117.480 91.455 ;
        RECT 114.855 90.485 115.060 90.915 ;
        RECT 115.230 90.830 117.480 91.085 ;
        RECT 115.230 90.485 116.955 90.830 ;
        RECT 47.830 88.065 49.800 89.110 ;
        RECT 49.980 88.065 50.235 89.695 ;
        RECT 114.855 89.890 115.025 90.485 ;
        RECT 115.195 90.070 115.985 90.315 ;
        RECT 117.125 90.195 117.490 90.660 ;
        RECT 117.660 90.365 117.915 91.245 ;
        RECT 118.510 91.085 120.840 91.455 ;
        RECT 116.155 89.890 116.745 90.095 ;
        RECT 114.855 89.720 116.745 89.890 ;
        RECT 116.955 89.865 117.545 90.195 ;
        RECT 114.855 88.815 115.330 89.720 ;
        RECT 115.510 89.110 116.955 89.540 ;
        RECT 117.125 89.280 117.490 89.865 ;
        RECT 117.715 89.695 117.915 90.365 ;
        RECT 115.510 88.065 117.480 89.110 ;
        RECT 117.660 88.065 117.915 89.695 ;
        RECT 118.215 90.485 118.420 90.915 ;
        RECT 118.590 90.830 120.840 91.085 ;
        RECT 118.590 90.485 120.315 90.830 ;
        RECT 118.215 89.890 118.385 90.485 ;
        RECT 118.555 90.070 119.345 90.315 ;
        RECT 120.485 90.195 120.850 90.660 ;
        RECT 121.020 90.365 121.275 91.245 ;
        RECT 121.870 91.085 124.200 91.455 ;
        RECT 119.515 89.890 120.105 90.095 ;
        RECT 118.215 89.720 120.105 89.890 ;
        RECT 120.315 89.865 120.905 90.195 ;
        RECT 118.215 88.815 118.690 89.720 ;
        RECT 118.870 89.110 120.315 89.540 ;
        RECT 120.485 89.280 120.850 89.865 ;
        RECT 121.075 89.695 121.275 90.365 ;
        RECT 118.870 88.065 120.840 89.110 ;
        RECT 121.020 88.065 121.275 89.695 ;
        RECT 121.575 90.485 121.780 90.915 ;
        RECT 121.950 90.830 124.200 91.085 ;
        RECT 121.950 90.485 123.675 90.830 ;
        RECT 121.575 89.890 121.745 90.485 ;
        RECT 121.915 90.070 122.705 90.315 ;
        RECT 123.845 90.195 124.210 90.660 ;
        RECT 124.380 90.365 124.635 91.245 ;
        RECT 122.875 89.890 123.465 90.095 ;
        RECT 121.575 89.720 123.465 89.890 ;
        RECT 123.675 89.865 124.265 90.195 ;
        RECT 121.575 88.815 122.050 89.720 ;
        RECT 122.230 89.110 123.675 89.540 ;
        RECT 123.845 89.280 124.210 89.865 ;
        RECT 124.435 89.695 124.635 90.365 ;
        RECT 122.230 88.065 124.200 89.110 ;
        RECT 124.380 89.075 124.635 89.695 ;
        RECT 124.380 88.905 124.655 89.075 ;
        RECT 124.380 88.065 124.635 88.905 ;
        RECT 40.280 87.665 50.360 87.835 ;
        RECT 110.840 87.665 124.760 87.835 ;
        RECT 40.455 85.780 40.930 86.685 ;
        RECT 41.110 86.390 43.080 87.435 ;
        RECT 43.260 86.695 43.515 87.435 ;
        RECT 43.260 86.525 43.565 86.695 ;
        RECT 41.110 85.960 42.555 86.390 ;
        RECT 40.455 85.610 42.345 85.780 ;
        RECT 42.725 85.635 43.090 86.220 ;
        RECT 43.260 85.805 43.515 86.525 ;
        RECT 40.455 85.015 40.625 85.610 ;
        RECT 40.795 85.185 41.585 85.430 ;
        RECT 41.755 85.405 42.345 85.610 ;
        RECT 42.555 85.305 43.145 85.635 ;
        RECT 40.455 84.585 40.660 85.015 ;
        RECT 40.830 84.670 42.555 85.015 ;
        RECT 42.725 84.840 43.090 85.305 ;
        RECT 43.315 85.135 43.515 85.805 ;
        RECT 40.830 84.415 43.080 84.670 ;
        RECT 40.750 84.045 43.080 84.415 ;
        RECT 43.260 84.255 43.515 85.135 ;
        RECT 46.215 85.780 46.690 86.685 ;
        RECT 46.870 86.390 48.840 87.435 ;
        RECT 49.020 86.695 49.275 87.435 ;
        RECT 49.020 86.525 49.345 86.695 ;
        RECT 46.870 85.960 48.315 86.390 ;
        RECT 46.215 85.610 48.105 85.780 ;
        RECT 48.485 85.635 48.850 86.220 ;
        RECT 49.020 85.805 49.275 86.525 ;
        RECT 46.215 85.015 46.385 85.610 ;
        RECT 46.555 85.185 47.345 85.430 ;
        RECT 47.515 85.405 48.105 85.610 ;
        RECT 48.315 85.305 48.905 85.635 ;
        RECT 46.215 84.585 46.420 85.015 ;
        RECT 46.590 84.670 48.315 85.015 ;
        RECT 48.485 84.840 48.850 85.305 ;
        RECT 49.075 85.135 49.275 85.805 ;
        RECT 46.590 84.415 48.840 84.670 ;
        RECT 46.510 84.045 48.840 84.415 ;
        RECT 49.020 84.255 49.275 85.135 ;
        RECT 111.015 85.780 111.490 86.685 ;
        RECT 111.670 86.390 113.640 87.435 ;
        RECT 111.670 85.960 113.115 86.390 ;
        RECT 111.015 85.610 112.905 85.780 ;
        RECT 113.285 85.635 113.650 86.220 ;
        RECT 113.820 85.805 114.075 87.435 ;
        RECT 111.015 85.015 111.185 85.610 ;
        RECT 111.355 85.185 112.145 85.430 ;
        RECT 112.315 85.405 112.905 85.610 ;
        RECT 113.115 85.305 113.705 85.635 ;
        RECT 111.015 84.585 111.220 85.015 ;
        RECT 111.390 84.670 113.115 85.015 ;
        RECT 113.285 84.840 113.650 85.305 ;
        RECT 113.875 85.135 114.075 85.805 ;
        RECT 113.820 84.995 114.075 85.135 ;
        RECT 114.375 85.780 114.850 86.685 ;
        RECT 115.030 86.390 117.000 87.435 ;
        RECT 115.030 85.960 116.475 86.390 ;
        RECT 114.375 85.610 116.265 85.780 ;
        RECT 116.645 85.635 117.010 86.220 ;
        RECT 117.180 85.805 117.435 87.435 ;
        RECT 114.375 85.015 114.545 85.610 ;
        RECT 114.715 85.185 115.505 85.430 ;
        RECT 115.675 85.405 116.265 85.610 ;
        RECT 116.475 85.305 117.065 85.635 ;
        RECT 113.820 84.825 114.115 84.995 ;
        RECT 111.390 84.415 113.640 84.670 ;
        RECT 111.310 84.045 113.640 84.415 ;
        RECT 113.820 84.255 114.075 84.825 ;
        RECT 114.375 84.585 114.580 85.015 ;
        RECT 114.750 84.670 116.475 85.015 ;
        RECT 116.645 84.840 117.010 85.305 ;
        RECT 117.235 85.135 117.435 85.805 ;
        RECT 117.180 84.995 117.435 85.135 ;
        RECT 117.735 85.780 118.210 86.685 ;
        RECT 118.390 86.390 120.360 87.435 ;
        RECT 118.390 85.960 119.835 86.390 ;
        RECT 117.735 85.610 119.625 85.780 ;
        RECT 120.005 85.635 120.370 86.220 ;
        RECT 120.540 85.805 120.795 87.435 ;
        RECT 117.735 85.015 117.905 85.610 ;
        RECT 118.075 85.185 118.865 85.430 ;
        RECT 119.035 85.405 119.625 85.610 ;
        RECT 119.835 85.305 120.425 85.635 ;
        RECT 117.180 84.825 117.515 84.995 ;
        RECT 114.750 84.415 117.000 84.670 ;
        RECT 114.670 84.045 117.000 84.415 ;
        RECT 117.180 84.255 117.435 84.825 ;
        RECT 117.735 84.585 117.940 85.015 ;
        RECT 118.110 84.670 119.835 85.015 ;
        RECT 120.005 84.840 120.370 85.305 ;
        RECT 120.595 85.135 120.795 85.805 ;
        RECT 118.110 84.415 120.360 84.670 ;
        RECT 118.030 84.045 120.360 84.415 ;
        RECT 120.540 84.255 120.795 85.135 ;
        RECT 121.095 85.780 121.570 86.685 ;
        RECT 121.750 86.390 123.720 87.435 ;
        RECT 121.750 85.960 123.195 86.390 ;
        RECT 121.095 85.610 122.985 85.780 ;
        RECT 123.365 85.635 123.730 86.220 ;
        RECT 123.900 85.805 124.155 87.435 ;
        RECT 121.095 85.015 121.265 85.610 ;
        RECT 121.435 85.185 122.225 85.430 ;
        RECT 122.395 85.405 122.985 85.610 ;
        RECT 123.195 85.305 123.785 85.635 ;
        RECT 121.095 84.585 121.300 85.015 ;
        RECT 121.470 84.670 123.195 85.015 ;
        RECT 123.365 84.840 123.730 85.305 ;
        RECT 123.955 85.135 124.155 85.805 ;
        RECT 121.470 84.415 123.720 84.670 ;
        RECT 121.390 84.045 123.720 84.415 ;
        RECT 123.900 84.255 124.155 85.135 ;
        RECT 40.280 83.595 57.080 83.765 ;
        RECT 110.840 83.595 124.760 83.765 ;
        RECT 40.750 82.945 43.080 83.315 ;
        RECT 40.455 82.345 40.660 82.775 ;
        RECT 40.830 82.690 43.080 82.945 ;
        RECT 40.830 82.345 42.555 82.690 ;
        RECT 40.455 81.750 40.625 82.345 ;
        RECT 40.795 81.930 41.585 82.175 ;
        RECT 42.725 82.055 43.090 82.520 ;
        RECT 43.260 82.225 43.515 83.105 ;
        RECT 44.110 82.945 46.440 83.315 ;
        RECT 41.755 81.750 42.345 81.955 ;
        RECT 40.455 81.580 42.345 81.750 ;
        RECT 42.555 81.725 43.145 82.055 ;
        RECT 40.455 80.675 40.930 81.580 ;
        RECT 41.110 80.970 42.555 81.400 ;
        RECT 42.725 81.140 43.090 81.725 ;
        RECT 43.315 81.555 43.515 82.225 ;
        RECT 41.110 79.925 43.080 80.970 ;
        RECT 43.260 80.915 43.515 81.555 ;
        RECT 43.815 82.345 44.020 82.775 ;
        RECT 44.190 82.690 46.440 82.945 ;
        RECT 44.190 82.345 45.915 82.690 ;
        RECT 43.815 81.750 43.985 82.345 ;
        RECT 44.155 81.930 44.945 82.175 ;
        RECT 46.085 82.055 46.450 82.520 ;
        RECT 46.620 82.225 46.875 83.105 ;
        RECT 47.470 82.945 49.800 83.315 ;
        RECT 45.115 81.750 45.705 81.955 ;
        RECT 43.815 81.580 45.705 81.750 ;
        RECT 45.915 81.725 46.505 82.055 ;
        RECT 43.260 80.745 43.565 80.915 ;
        RECT 43.260 79.925 43.515 80.745 ;
        RECT 43.815 80.675 44.290 81.580 ;
        RECT 44.470 80.970 45.915 81.400 ;
        RECT 46.085 81.140 46.450 81.725 ;
        RECT 46.675 81.555 46.875 82.225 ;
        RECT 44.470 79.925 46.440 80.970 ;
        RECT 46.620 79.925 46.875 81.555 ;
        RECT 47.175 82.345 47.380 82.775 ;
        RECT 47.550 82.690 49.800 82.945 ;
        RECT 47.550 82.345 49.275 82.690 ;
        RECT 47.175 81.750 47.345 82.345 ;
        RECT 47.515 81.930 48.305 82.175 ;
        RECT 49.445 82.055 49.810 82.520 ;
        RECT 49.980 82.225 50.235 83.105 ;
        RECT 50.830 82.945 53.160 83.315 ;
        RECT 48.475 81.750 49.065 81.955 ;
        RECT 47.175 81.580 49.065 81.750 ;
        RECT 49.275 81.725 49.865 82.055 ;
        RECT 47.175 80.675 47.650 81.580 ;
        RECT 47.830 80.970 49.275 81.400 ;
        RECT 49.445 81.140 49.810 81.725 ;
        RECT 50.035 81.555 50.235 82.225 ;
        RECT 47.830 79.925 49.800 80.970 ;
        RECT 49.980 79.925 50.235 81.555 ;
        RECT 50.535 82.345 50.740 82.775 ;
        RECT 50.910 82.690 53.160 82.945 ;
        RECT 50.910 82.345 52.635 82.690 ;
        RECT 50.535 81.750 50.705 82.345 ;
        RECT 50.875 81.930 51.665 82.175 ;
        RECT 52.805 82.055 53.170 82.520 ;
        RECT 53.340 82.225 53.595 83.105 ;
        RECT 54.190 82.945 56.520 83.315 ;
        RECT 51.835 81.750 52.425 81.955 ;
        RECT 50.535 81.580 52.425 81.750 ;
        RECT 52.635 81.725 53.225 82.055 ;
        RECT 50.535 80.675 51.010 81.580 ;
        RECT 51.190 80.970 52.635 81.400 ;
        RECT 52.805 81.140 53.170 81.725 ;
        RECT 53.395 81.555 53.595 82.225 ;
        RECT 51.190 79.925 53.160 80.970 ;
        RECT 53.340 79.925 53.595 81.555 ;
        RECT 53.895 82.345 54.100 82.775 ;
        RECT 54.270 82.690 56.520 82.945 ;
        RECT 54.270 82.345 55.995 82.690 ;
        RECT 53.895 81.750 54.065 82.345 ;
        RECT 54.235 81.930 55.025 82.175 ;
        RECT 56.165 82.055 56.530 82.520 ;
        RECT 56.700 82.225 56.955 83.105 ;
        RECT 113.230 82.945 115.560 83.315 ;
        RECT 55.195 81.750 55.785 81.955 ;
        RECT 53.895 81.580 55.785 81.750 ;
        RECT 55.995 81.725 56.585 82.055 ;
        RECT 53.895 80.675 54.370 81.580 ;
        RECT 54.550 80.970 55.995 81.400 ;
        RECT 56.165 81.140 56.530 81.725 ;
        RECT 56.755 81.555 56.955 82.225 ;
        RECT 112.935 82.345 113.140 82.775 ;
        RECT 113.310 82.690 115.560 82.945 ;
        RECT 113.310 82.345 115.035 82.690 ;
        RECT 56.700 81.255 56.955 81.555 ;
        RECT 56.700 81.085 56.995 81.255 ;
        RECT 54.550 79.925 56.520 80.970 ;
        RECT 56.700 79.925 56.955 81.085 ;
        RECT 39.320 79.525 57.080 79.695 ;
        RECT 39.495 77.640 39.970 78.545 ;
        RECT 40.150 78.250 42.120 79.295 ;
        RECT 40.150 77.820 41.595 78.250 ;
        RECT 39.495 77.470 41.385 77.640 ;
        RECT 41.765 77.495 42.130 78.080 ;
        RECT 42.300 77.665 42.555 79.295 ;
        RECT 39.495 76.875 39.665 77.470 ;
        RECT 39.835 77.045 40.625 77.290 ;
        RECT 40.795 77.265 41.385 77.470 ;
        RECT 41.595 77.165 42.185 77.495 ;
        RECT 39.495 76.445 39.700 76.875 ;
        RECT 39.870 76.530 41.595 76.875 ;
        RECT 41.765 76.700 42.130 77.165 ;
        RECT 42.355 76.995 42.555 77.665 ;
        RECT 39.870 76.275 42.120 76.530 ;
        RECT 39.790 75.905 42.120 76.275 ;
        RECT 42.300 76.115 42.555 76.995 ;
        RECT 42.855 77.640 43.330 78.545 ;
        RECT 43.510 78.250 45.480 79.295 ;
        RECT 45.660 78.535 45.915 79.295 ;
        RECT 45.660 78.365 45.945 78.535 ;
        RECT 43.510 77.820 44.955 78.250 ;
        RECT 42.855 77.470 44.745 77.640 ;
        RECT 45.125 77.495 45.490 78.080 ;
        RECT 45.660 77.665 45.915 78.365 ;
        RECT 42.855 76.875 43.025 77.470 ;
        RECT 43.195 77.045 43.985 77.290 ;
        RECT 44.155 77.265 44.745 77.470 ;
        RECT 44.955 77.165 45.545 77.495 ;
        RECT 42.855 76.445 43.060 76.875 ;
        RECT 43.230 76.530 44.955 76.875 ;
        RECT 45.125 76.700 45.490 77.165 ;
        RECT 45.715 76.995 45.915 77.665 ;
        RECT 43.230 76.275 45.480 76.530 ;
        RECT 43.150 75.905 45.480 76.275 ;
        RECT 45.660 76.115 45.915 76.995 ;
        RECT 46.215 77.640 46.690 78.545 ;
        RECT 46.870 78.250 48.840 79.295 ;
        RECT 46.870 77.820 48.315 78.250 ;
        RECT 46.215 77.470 48.105 77.640 ;
        RECT 48.485 77.495 48.850 78.080 ;
        RECT 49.020 77.665 49.275 79.295 ;
        RECT 46.215 76.875 46.385 77.470 ;
        RECT 46.555 77.045 47.345 77.290 ;
        RECT 47.515 77.265 48.105 77.470 ;
        RECT 48.315 77.165 48.905 77.495 ;
        RECT 46.215 76.445 46.420 76.875 ;
        RECT 46.590 76.530 48.315 76.875 ;
        RECT 48.485 76.700 48.850 77.165 ;
        RECT 49.075 76.995 49.275 77.665 ;
        RECT 49.020 76.835 49.275 76.995 ;
        RECT 49.575 77.640 50.050 78.545 ;
        RECT 50.230 78.250 52.200 79.295 ;
        RECT 50.230 77.820 51.675 78.250 ;
        RECT 49.575 77.470 51.465 77.640 ;
        RECT 51.845 77.515 52.210 78.080 ;
        RECT 52.380 77.665 52.635 79.295 ;
        RECT 51.845 77.495 52.235 77.515 ;
        RECT 49.575 76.875 49.745 77.470 ;
        RECT 49.915 77.045 50.705 77.290 ;
        RECT 50.875 77.265 51.465 77.470 ;
        RECT 51.675 77.165 52.265 77.495 ;
        RECT 49.020 76.665 49.345 76.835 ;
        RECT 46.590 76.275 48.840 76.530 ;
        RECT 46.510 75.905 48.840 76.275 ;
        RECT 49.020 76.115 49.275 76.665 ;
        RECT 49.575 76.445 49.780 76.875 ;
        RECT 49.950 76.530 51.675 76.875 ;
        RECT 51.845 76.700 52.210 77.165 ;
        RECT 52.435 76.995 52.635 77.665 ;
        RECT 49.950 76.275 52.200 76.530 ;
        RECT 49.870 75.905 52.200 76.275 ;
        RECT 52.380 76.115 52.635 76.995 ;
        RECT 52.935 77.640 53.410 78.545 ;
        RECT 53.590 78.250 55.560 79.295 ;
        RECT 53.590 77.820 55.035 78.250 ;
        RECT 52.935 77.470 54.825 77.640 ;
        RECT 55.205 77.515 55.570 78.080 ;
        RECT 55.740 77.665 55.995 79.295 ;
        RECT 55.125 77.495 55.570 77.515 ;
        RECT 52.935 76.875 53.105 77.470 ;
        RECT 53.275 77.045 54.065 77.290 ;
        RECT 54.235 77.265 54.825 77.470 ;
        RECT 55.035 77.165 55.625 77.495 ;
        RECT 52.935 76.445 53.140 76.875 ;
        RECT 53.310 76.530 55.035 76.875 ;
        RECT 55.205 76.700 55.570 77.165 ;
        RECT 55.795 76.995 55.995 77.665 ;
        RECT 57.505 77.345 57.675 81.935 ;
        RECT 112.935 81.750 113.105 82.345 ;
        RECT 113.275 81.930 114.065 82.175 ;
        RECT 115.205 82.055 115.570 82.520 ;
        RECT 115.740 82.225 115.995 83.105 ;
        RECT 116.590 82.945 118.920 83.315 ;
        RECT 114.235 81.750 114.825 81.955 ;
        RECT 112.935 81.580 114.825 81.750 ;
        RECT 115.035 81.725 115.625 82.055 ;
        RECT 112.935 80.675 113.410 81.580 ;
        RECT 113.590 80.970 115.035 81.400 ;
        RECT 115.205 81.140 115.570 81.725 ;
        RECT 115.795 81.555 115.995 82.225 ;
        RECT 113.590 79.925 115.560 80.970 ;
        RECT 115.740 79.925 115.995 81.555 ;
        RECT 116.295 82.345 116.500 82.775 ;
        RECT 116.670 82.690 118.920 82.945 ;
        RECT 116.670 82.345 118.395 82.690 ;
        RECT 116.295 81.750 116.465 82.345 ;
        RECT 116.635 81.930 117.425 82.175 ;
        RECT 118.565 82.055 118.930 82.520 ;
        RECT 119.100 82.225 119.355 83.105 ;
        RECT 121.870 82.945 124.200 83.315 ;
        RECT 117.595 81.750 118.185 81.955 ;
        RECT 116.295 81.580 118.185 81.750 ;
        RECT 118.395 81.725 118.985 82.055 ;
        RECT 116.295 80.675 116.770 81.580 ;
        RECT 116.950 80.970 118.395 81.400 ;
        RECT 118.565 81.140 118.930 81.725 ;
        RECT 119.155 81.555 119.355 82.225 ;
        RECT 119.100 81.255 119.355 81.555 ;
        RECT 121.575 82.345 121.780 82.775 ;
        RECT 121.950 82.690 124.200 82.945 ;
        RECT 121.950 82.345 123.675 82.690 ;
        RECT 121.575 81.750 121.745 82.345 ;
        RECT 121.915 81.930 122.705 82.175 ;
        RECT 123.845 82.055 124.210 82.520 ;
        RECT 124.380 82.225 124.635 83.105 ;
        RECT 122.875 81.750 123.465 81.955 ;
        RECT 121.575 81.580 123.465 81.750 ;
        RECT 123.675 81.725 124.265 82.055 ;
        RECT 119.100 81.085 119.385 81.255 ;
        RECT 116.950 79.925 118.920 80.970 ;
        RECT 119.100 79.925 119.355 81.085 ;
        RECT 121.575 80.675 122.050 81.580 ;
        RECT 122.230 80.970 123.675 81.400 ;
        RECT 123.845 81.140 124.210 81.725 ;
        RECT 124.435 81.555 124.635 82.225 ;
        RECT 122.230 79.925 124.200 80.970 ;
        RECT 124.380 80.575 124.635 81.555 ;
        RECT 124.380 80.405 124.655 80.575 ;
        RECT 124.380 79.925 124.635 80.405 ;
        RECT 112.760 79.525 127.160 79.695 ;
        RECT 113.895 77.640 114.370 78.545 ;
        RECT 114.550 78.250 116.520 79.295 ;
        RECT 116.700 78.535 116.955 79.295 ;
        RECT 116.700 78.365 117.005 78.535 ;
        RECT 114.550 77.820 115.995 78.250 ;
        RECT 113.895 77.470 115.785 77.640 ;
        RECT 116.165 77.495 116.530 78.080 ;
        RECT 116.700 77.665 116.955 78.365 ;
        RECT 53.310 76.275 55.560 76.530 ;
        RECT 53.230 75.905 55.560 76.275 ;
        RECT 55.740 76.115 55.995 76.995 ;
        RECT 113.895 76.875 114.065 77.470 ;
        RECT 114.235 77.045 115.025 77.290 ;
        RECT 115.195 77.265 115.785 77.470 ;
        RECT 115.995 77.165 116.585 77.495 ;
        RECT 113.895 76.445 114.100 76.875 ;
        RECT 114.270 76.530 115.995 76.875 ;
        RECT 116.165 76.700 116.530 77.165 ;
        RECT 116.755 76.995 116.955 77.665 ;
        RECT 114.270 76.275 116.520 76.530 ;
        RECT 114.190 75.905 116.520 76.275 ;
        RECT 116.700 76.115 116.955 76.995 ;
        RECT 117.255 77.640 117.730 78.545 ;
        RECT 117.910 78.250 119.880 79.295 ;
        RECT 117.910 77.820 119.355 78.250 ;
        RECT 117.255 77.470 119.145 77.640 ;
        RECT 119.525 77.515 119.890 78.080 ;
        RECT 120.060 77.665 120.315 79.295 ;
        RECT 119.385 77.495 119.890 77.515 ;
        RECT 117.255 76.875 117.425 77.470 ;
        RECT 117.595 77.045 118.385 77.290 ;
        RECT 118.555 77.265 119.145 77.470 ;
        RECT 119.355 77.165 119.945 77.495 ;
        RECT 117.255 76.445 117.460 76.875 ;
        RECT 117.630 76.530 119.355 76.875 ;
        RECT 119.525 76.700 119.890 77.165 ;
        RECT 120.115 76.995 120.315 77.665 ;
        RECT 117.630 76.275 119.880 76.530 ;
        RECT 117.550 75.905 119.880 76.275 ;
        RECT 120.060 76.115 120.315 76.995 ;
        RECT 120.615 77.640 121.090 78.545 ;
        RECT 121.270 78.250 123.240 79.295 ;
        RECT 121.270 77.820 122.715 78.250 ;
        RECT 120.615 77.470 122.505 77.640 ;
        RECT 122.885 77.515 123.250 78.080 ;
        RECT 123.420 77.665 123.675 79.295 ;
        RECT 122.785 77.495 123.250 77.515 ;
        RECT 120.615 76.875 120.785 77.470 ;
        RECT 120.955 77.045 121.745 77.290 ;
        RECT 121.915 77.265 122.505 77.470 ;
        RECT 122.715 77.165 123.305 77.495 ;
        RECT 120.615 76.445 120.820 76.875 ;
        RECT 120.990 76.530 122.715 76.875 ;
        RECT 122.885 76.700 123.250 77.165 ;
        RECT 123.475 76.995 123.675 77.665 ;
        RECT 120.990 76.275 123.240 76.530 ;
        RECT 120.910 75.905 123.240 76.275 ;
        RECT 123.420 76.115 123.675 76.995 ;
        RECT 123.975 77.640 124.450 78.545 ;
        RECT 124.630 78.250 126.600 79.295 ;
        RECT 124.630 77.820 126.075 78.250 ;
        RECT 123.975 77.470 125.865 77.640 ;
        RECT 126.245 77.515 126.610 78.080 ;
        RECT 126.780 77.665 127.035 79.295 ;
        RECT 126.185 77.495 126.610 77.515 ;
        RECT 123.975 76.875 124.145 77.470 ;
        RECT 124.315 77.045 125.105 77.290 ;
        RECT 125.275 77.265 125.865 77.470 ;
        RECT 126.075 77.165 126.665 77.495 ;
        RECT 123.975 76.445 124.180 76.875 ;
        RECT 124.350 76.530 126.075 76.875 ;
        RECT 126.245 76.700 126.610 77.165 ;
        RECT 126.835 76.995 127.035 77.665 ;
        RECT 124.350 76.275 126.600 76.530 ;
        RECT 124.270 75.905 126.600 76.275 ;
        RECT 126.780 76.115 127.035 76.995 ;
        RECT 39.320 75.455 56.120 75.625 ;
        RECT 113.720 75.455 127.160 75.625 ;
      LAYER met1 ;
        RECT 37.880 160.710 127.160 161.310 ;
        RECT 39.320 160.385 47.480 160.710 ;
        RECT 49.400 160.385 56.600 160.710 ;
        RECT 58.040 160.385 65.240 160.710 ;
        RECT 115.640 160.385 125.720 160.710 ;
        RECT 38.650 160.120 38.970 160.180 ;
        RECT 40.445 160.120 40.735 160.165 ;
        RECT 43.875 160.120 44.105 160.195 ;
        RECT 38.650 159.980 40.735 160.120 ;
        RECT 38.650 159.920 38.970 159.980 ;
        RECT 40.445 159.935 40.735 159.980 ;
        RECT 41.040 159.980 44.105 160.120 ;
        RECT 38.190 159.440 38.510 159.500 ;
        RECT 41.040 159.440 41.180 159.980 ;
        RECT 43.875 159.905 44.105 159.980 ;
        RECT 122.045 160.120 122.335 160.165 ;
        RECT 123.750 160.120 124.070 160.180 ;
        RECT 122.045 159.980 124.070 160.120 ;
        RECT 122.045 159.935 122.335 159.980 ;
        RECT 123.750 159.920 124.070 159.980 ;
        RECT 47.075 159.780 47.365 159.825 ;
        RECT 38.190 159.300 41.180 159.440 ;
        RECT 44.260 159.640 47.365 159.780 ;
        RECT 38.190 159.240 38.510 159.300 ;
        RECT 37.730 159.100 38.050 159.160 ;
        RECT 44.260 159.100 44.400 159.640 ;
        RECT 47.075 159.595 47.365 159.640 ;
        RECT 118.135 159.440 118.425 159.485 ;
        RECT 118.135 159.255 118.460 159.440 ;
        RECT 37.730 158.960 44.400 159.100 ;
        RECT 37.730 158.900 38.050 158.960 ;
        RECT 51.990 158.900 52.310 159.160 ;
        RECT 116.850 159.100 117.170 159.160 ;
        RECT 118.320 159.100 118.460 159.255 ;
        RECT 124.765 159.100 125.055 159.145 ;
        RECT 116.850 158.960 125.055 159.100 ;
        RECT 116.850 158.900 117.170 158.960 ;
        RECT 34.970 158.760 35.290 158.820 ;
        RECT 39.425 158.760 39.715 158.805 ;
        RECT 48.770 158.760 49.090 158.820 ;
        RECT 49.625 158.760 49.915 158.805 ;
        RECT 34.970 158.620 39.715 158.760 ;
        RECT 41.960 158.695 43.940 158.760 ;
        RECT 41.870 158.680 43.940 158.695 ;
        RECT 34.970 158.560 35.290 158.620 ;
        RECT 39.425 158.575 39.715 158.620 ;
        RECT 41.805 158.635 43.940 158.680 ;
        RECT 44.695 158.635 44.985 158.680 ;
        RECT 41.805 158.620 44.985 158.635 ;
        RECT 41.805 158.450 42.190 158.620 ;
        RECT 43.800 158.495 44.985 158.620 ;
        RECT 48.770 158.620 49.915 158.760 ;
        RECT 48.770 158.560 49.090 158.620 ;
        RECT 49.625 158.575 49.915 158.620 ;
        RECT 54.290 158.760 54.610 158.820 ;
        RECT 121.540 158.805 121.680 158.960 ;
        RECT 124.765 158.915 125.055 158.960 ;
        RECT 58.465 158.760 58.755 158.805 ;
        RECT 54.290 158.620 58.755 158.760 ;
        RECT 119.700 158.680 121.220 158.760 ;
        RECT 54.290 158.560 54.610 158.620 ;
        RECT 58.465 158.575 58.755 158.620 ;
        RECT 116.435 158.635 116.725 158.680 ;
        RECT 119.495 158.635 121.220 158.680 ;
        RECT 41.870 158.435 42.190 158.450 ;
        RECT 43.165 158.420 43.455 158.465 ;
        RECT 44.695 158.450 44.985 158.495 ;
        RECT 116.435 158.495 117.080 158.635 ;
        RECT 46.565 158.420 46.855 158.465 ;
        RECT 116.435 158.450 116.725 158.495 ;
        RECT 42.880 158.280 43.455 158.420 ;
        RECT 41.410 158.080 41.730 158.140 ;
        RECT 42.880 158.080 43.020 158.280 ;
        RECT 43.165 158.235 43.455 158.280 ;
        RECT 45.640 158.280 46.855 158.420 ;
        RECT 45.640 158.080 45.780 158.280 ;
        RECT 46.565 158.235 46.855 158.280 ;
        RECT 63.950 158.125 64.270 158.140 ;
        RECT 41.410 157.940 45.780 158.080 ;
        RECT 41.410 157.880 41.730 157.940 ;
        RECT 63.905 157.895 64.270 158.125 ;
        RECT 63.950 157.880 64.270 157.895 ;
        RECT 116.390 158.080 116.710 158.140 ;
        RECT 116.940 158.080 117.080 158.495 ;
        RECT 118.925 158.620 121.220 158.635 ;
        RECT 118.925 158.495 119.840 158.620 ;
        RECT 118.925 158.420 119.065 158.495 ;
        RECT 119.495 158.450 119.785 158.495 ;
        RECT 118.320 158.280 119.065 158.420 ;
        RECT 121.080 158.420 121.220 158.620 ;
        RECT 121.365 158.620 121.680 158.805 ;
        RECT 125.475 158.760 125.705 158.835 ;
        RECT 128.810 158.760 129.130 158.820 ;
        RECT 122.895 158.635 123.185 158.680 ;
        RECT 121.365 158.575 121.655 158.620 ;
        RECT 122.000 158.495 123.185 158.635 ;
        RECT 125.475 158.620 129.130 158.760 ;
        RECT 125.475 158.545 125.705 158.620 ;
        RECT 128.810 158.560 129.130 158.620 ;
        RECT 122.000 158.420 122.140 158.495 ;
        RECT 122.895 158.450 123.185 158.495 ;
        RECT 121.080 158.280 122.140 158.420 ;
        RECT 118.320 158.080 118.460 158.280 ;
        RECT 118.690 158.125 119.010 158.140 ;
        RECT 116.390 157.940 118.460 158.080 ;
        RECT 116.390 157.880 116.710 157.940 ;
        RECT 118.645 157.895 119.010 158.125 ;
        RECT 118.690 157.880 119.010 157.895 ;
        RECT 39.320 157.240 47.480 157.565 ;
        RECT 49.400 157.240 56.600 157.565 ;
        RECT 58.040 157.240 65.240 157.565 ;
        RECT 115.640 157.240 125.720 157.565 ;
        RECT 37.880 156.640 127.160 157.240 ;
        RECT 40.280 156.315 71.960 156.640 ;
        RECT 114.680 156.315 124.760 156.640 ;
        RECT 39.110 156.040 39.430 156.100 ;
        RECT 49.965 156.040 50.255 156.085 ;
        RECT 39.110 155.900 50.255 156.040 ;
        RECT 39.110 155.840 39.430 155.900 ;
        RECT 49.965 155.855 50.255 155.900 ;
        RECT 117.625 156.040 117.915 156.085 ;
        RECT 118.690 156.040 119.010 156.100 ;
        RECT 117.625 155.900 119.010 156.040 ;
        RECT 117.625 155.855 117.915 155.900 ;
        RECT 118.690 155.840 119.010 155.900 ;
        RECT 38.650 155.700 38.970 155.760 ;
        RECT 51.990 155.700 52.310 155.760 ;
        RECT 53.830 155.700 54.150 155.760 ;
        RECT 63.950 155.745 64.270 155.760 ;
        RECT 38.650 155.560 49.920 155.700 ;
        RECT 38.650 155.500 38.970 155.560 ;
        RECT 39.765 155.360 40.055 155.405 ;
        RECT 40.785 155.360 41.075 155.405 ;
        RECT 41.870 155.360 42.190 155.420 ;
        RECT 44.185 155.360 44.475 155.405 ;
        RECT 47.585 155.360 47.875 155.405 ;
        RECT 49.285 155.360 49.575 155.405 ;
        RECT 39.765 155.220 47.875 155.360 ;
        RECT 39.765 155.175 40.055 155.220 ;
        RECT 40.785 155.175 41.075 155.220 ;
        RECT 41.870 155.160 42.190 155.220 ;
        RECT 44.185 155.175 44.475 155.220 ;
        RECT 47.585 155.175 47.875 155.220 ;
        RECT 48.400 155.220 49.575 155.360 ;
        RECT 49.780 155.360 49.920 155.560 ;
        RECT 51.990 155.560 54.150 155.700 ;
        RECT 51.990 155.500 52.310 155.560 ;
        RECT 53.830 155.500 54.150 155.560 ;
        RECT 63.905 155.515 64.270 155.745 ;
        RECT 63.950 155.500 64.270 155.515 ;
        RECT 116.390 155.700 116.710 155.760 ;
        RECT 116.390 155.560 118.460 155.700 ;
        RECT 116.390 155.500 116.710 155.560 ;
        RECT 50.645 155.360 50.935 155.405 ;
        RECT 57.785 155.360 58.075 155.405 ;
        RECT 61.650 155.360 61.970 155.420 ;
        RECT 49.780 155.220 61.970 155.360 ;
        RECT 64.040 155.360 64.180 155.500 ;
        RECT 64.925 155.360 65.215 155.405 ;
        RECT 64.040 155.220 65.215 155.360 ;
        RECT 46.225 155.020 46.515 155.065 ;
        RECT 48.400 155.020 48.540 155.220 ;
        RECT 49.285 155.175 49.575 155.220 ;
        RECT 50.645 155.175 50.935 155.220 ;
        RECT 57.785 155.175 58.075 155.220 ;
        RECT 61.650 155.160 61.970 155.220 ;
        RECT 64.925 155.175 65.215 155.220 ;
        RECT 114.090 155.360 114.410 155.420 ;
        RECT 115.245 155.360 115.535 155.405 ;
        RECT 116.480 155.360 116.620 155.500 ;
        RECT 114.090 155.220 116.620 155.360 ;
        RECT 116.850 155.405 117.170 155.420 ;
        RECT 116.850 155.360 117.235 155.405 ;
        RECT 118.320 155.360 118.460 155.560 ;
        RECT 118.645 155.360 118.935 155.405 ;
        RECT 122.045 155.360 122.335 155.405 ;
        RECT 116.850 155.220 118.000 155.360 ;
        RECT 118.320 155.220 122.335 155.360 ;
        RECT 114.090 155.160 114.410 155.220 ;
        RECT 115.245 155.175 115.535 155.220 ;
        RECT 116.850 155.175 117.235 155.220 ;
        RECT 116.850 155.160 117.170 155.175 ;
        RECT 46.100 154.880 48.540 155.020 ;
        RECT 117.860 155.020 118.000 155.220 ;
        RECT 118.645 155.175 118.935 155.220 ;
        RECT 122.045 155.175 122.335 155.220 ;
        RECT 120.345 155.020 120.635 155.065 ;
        RECT 123.745 155.020 124.035 155.065 ;
        RECT 117.860 154.880 124.035 155.020 ;
        RECT 46.100 154.835 46.515 154.880 ;
        RECT 120.345 154.835 120.635 154.880 ;
        RECT 123.745 154.835 124.035 154.880 ;
        RECT 41.410 154.680 41.730 154.740 ;
        RECT 42.825 154.680 43.115 154.725 ;
        RECT 46.100 154.680 46.240 154.835 ;
        RECT 41.410 154.540 46.240 154.680 ;
        RECT 121.025 154.680 121.315 154.725 ;
        RECT 126.510 154.680 126.830 154.740 ;
        RECT 121.025 154.540 126.830 154.680 ;
        RECT 41.410 154.480 41.730 154.540 ;
        RECT 42.825 154.495 43.115 154.540 ;
        RECT 121.025 154.495 121.315 154.540 ;
        RECT 126.510 154.480 126.830 154.540 ;
        RECT 39.110 154.340 39.430 154.400 ;
        RECT 46.565 154.340 46.855 154.385 ;
        RECT 39.110 154.200 46.855 154.340 ;
        RECT 39.110 154.140 39.430 154.200 ;
        RECT 46.565 154.155 46.855 154.200 ;
        RECT 36.350 154.000 36.670 154.060 ;
        RECT 43.335 154.000 43.625 154.045 ;
        RECT 36.350 153.860 43.625 154.000 ;
        RECT 36.350 153.800 36.670 153.860 ;
        RECT 43.335 153.815 43.625 153.860 ;
        RECT 65.945 154.000 66.235 154.045 ;
        RECT 66.710 154.000 67.030 154.060 ;
        RECT 65.945 153.860 67.030 154.000 ;
        RECT 65.945 153.815 66.235 153.860 ;
        RECT 66.710 153.800 67.030 153.860 ;
        RECT 124.425 154.000 124.715 154.045 ;
        RECT 128.350 154.000 128.670 154.060 ;
        RECT 124.425 153.860 128.670 154.000 ;
        RECT 124.425 153.815 124.715 153.860 ;
        RECT 128.350 153.800 128.670 153.860 ;
        RECT 40.280 153.170 71.960 153.495 ;
        RECT 114.680 153.170 124.760 153.495 ;
        RECT 37.880 152.570 127.160 153.170 ;
        RECT 40.280 152.245 47.000 152.570 ;
        RECT 47.480 152.245 54.200 152.570 ;
        RECT 60.920 152.245 65.240 152.570 ;
        RECT 66.200 152.245 67.640 152.570 ;
        RECT 68.600 152.245 83.000 152.570 ;
        RECT 111.320 152.245 124.760 152.570 ;
        RECT 51.990 151.960 52.310 152.020 ;
        RECT 61.650 152.005 61.970 152.020 ;
        RECT 53.875 151.960 54.165 152.005 ;
        RECT 51.990 151.820 54.165 151.960 ;
        RECT 51.990 151.760 52.310 151.820 ;
        RECT 53.875 151.775 54.165 151.820 ;
        RECT 61.650 151.775 62.155 152.005 ;
        RECT 114.425 151.960 114.655 152.035 ;
        RECT 116.390 151.960 116.710 152.020 ;
        RECT 114.425 151.820 116.710 151.960 ;
        RECT 61.650 151.760 61.970 151.775 ;
        RECT 114.425 151.745 114.655 151.820 ;
        RECT 116.390 151.760 116.710 151.820 ;
        RECT 39.110 151.280 39.430 151.340 ;
        RECT 46.565 151.280 46.855 151.325 ;
        RECT 49.965 151.280 50.255 151.325 ;
        RECT 53.365 151.280 53.655 151.325 ;
        RECT 63.225 151.280 63.515 151.325 ;
        RECT 64.925 151.280 65.215 151.325 ;
        RECT 39.110 151.140 46.855 151.280 ;
        RECT 39.110 151.080 39.430 151.140 ;
        RECT 46.565 151.095 46.855 151.140 ;
        RECT 47.020 151.140 53.655 151.280 ;
        RECT 41.410 150.940 41.730 151.000 ;
        RECT 42.825 150.940 43.115 150.985 ;
        RECT 47.020 150.940 47.160 151.140 ;
        RECT 49.965 151.095 50.255 151.140 ;
        RECT 53.365 151.095 53.655 151.140 ;
        RECT 63.120 151.140 65.215 151.280 ;
        RECT 63.120 151.095 63.515 151.140 ;
        RECT 64.925 151.095 65.215 151.140 ;
        RECT 41.410 150.800 47.160 150.940 ;
        RECT 41.410 150.740 41.730 150.800 ;
        RECT 42.825 150.755 43.115 150.800 ;
        RECT 46.300 150.645 46.440 150.800 ;
        RECT 39.765 150.495 40.055 150.540 ;
        RECT 40.785 150.495 41.075 150.540 ;
        RECT 44.185 150.495 44.475 150.540 ;
        RECT 39.765 150.355 45.780 150.495 ;
        RECT 46.225 150.415 46.515 150.645 ;
        RECT 48.770 150.600 49.090 150.660 ;
        RECT 63.120 150.645 63.260 151.095 ;
        RECT 67.305 150.940 67.595 150.985 ;
        RECT 114.090 150.940 114.410 151.000 ;
        RECT 121.025 150.940 121.315 150.985 ;
        RECT 126.510 150.940 126.830 151.000 ;
        RECT 65.420 150.800 67.595 150.940 ;
        RECT 64.410 150.645 64.730 150.660 ;
        RECT 50.475 150.600 50.765 150.645 ;
        RECT 47.940 150.540 48.540 150.600 ;
        RECT 47.940 150.460 48.555 150.540 ;
        RECT 39.765 150.310 40.055 150.355 ;
        RECT 40.785 150.310 41.075 150.355 ;
        RECT 44.185 150.310 44.475 150.355 ;
        RECT 38.190 149.920 38.510 149.980 ;
        RECT 43.335 149.920 43.625 149.965 ;
        RECT 38.190 149.780 43.625 149.920 ;
        RECT 45.640 149.920 45.780 150.355 ;
        RECT 47.940 149.920 48.080 150.460 ;
        RECT 48.265 150.310 48.555 150.460 ;
        RECT 48.770 150.460 50.765 150.600 ;
        RECT 61.525 150.600 61.815 150.645 ;
        RECT 62.885 150.600 63.260 150.645 ;
        RECT 51.495 150.495 51.785 150.540 ;
        RECT 48.770 150.400 49.090 150.460 ;
        RECT 50.475 150.415 50.765 150.460 ;
        RECT 51.160 150.355 51.785 150.495 ;
        RECT 61.525 150.460 63.260 150.600 ;
        RECT 64.245 150.600 64.730 150.645 ;
        RECT 65.420 150.600 65.560 150.800 ;
        RECT 67.305 150.755 67.595 150.800 ;
        RECT 113.260 150.800 114.410 150.940 ;
        RECT 66.710 150.645 67.030 150.660 ;
        RECT 69.010 150.645 69.330 150.660 ;
        RECT 76.370 150.645 76.690 150.660 ;
        RECT 64.245 150.460 65.560 150.600 ;
        RECT 66.625 150.600 67.030 150.645 ;
        RECT 69.005 150.600 69.330 150.645 ;
        RECT 76.145 150.600 76.690 150.645 ;
        RECT 66.625 150.460 69.330 150.600 ;
        RECT 61.525 150.415 61.815 150.460 ;
        RECT 62.885 150.415 63.175 150.460 ;
        RECT 64.245 150.415 64.730 150.460 ;
        RECT 66.625 150.415 67.030 150.460 ;
        RECT 69.005 150.415 69.330 150.460 ;
        RECT 64.410 150.400 64.730 150.415 ;
        RECT 66.710 150.400 67.030 150.415 ;
        RECT 69.010 150.400 69.330 150.415 ;
        RECT 75.540 150.460 76.690 150.600 ;
        RECT 113.260 150.600 113.400 150.800 ;
        RECT 114.090 150.740 114.410 150.800 ;
        RECT 117.020 150.800 120.560 150.940 ;
        RECT 117.020 150.660 117.160 150.800 ;
        RECT 116.850 150.645 117.170 150.660 ;
        RECT 120.420 150.645 120.560 150.800 ;
        RECT 121.025 150.800 126.830 150.940 ;
        RECT 121.025 150.755 121.315 150.800 ;
        RECT 126.510 150.740 126.830 150.800 ;
        RECT 123.750 150.645 124.070 150.660 ;
        RECT 113.260 150.540 115.700 150.600 ;
        RECT 51.160 149.920 51.300 150.355 ;
        RECT 51.495 150.310 51.785 150.355 ;
        RECT 75.540 150.305 75.680 150.460 ;
        RECT 76.145 150.415 76.690 150.460 ;
        RECT 76.370 150.400 76.690 150.415 ;
        RECT 112.355 150.495 112.645 150.540 ;
        RECT 113.260 150.495 115.705 150.540 ;
        RECT 112.355 150.460 116.620 150.495 ;
        RECT 112.355 150.355 113.400 150.460 ;
        RECT 115.415 150.355 116.620 150.460 ;
        RECT 116.850 150.415 117.235 150.645 ;
        RECT 118.985 150.495 119.275 150.540 ;
        RECT 116.850 150.400 117.170 150.415 ;
        RECT 112.355 150.310 112.645 150.355 ;
        RECT 115.415 150.310 115.705 150.355 ;
        RECT 75.465 150.075 75.755 150.305 ;
        RECT 113.885 150.260 114.175 150.305 ;
        RECT 116.480 150.260 116.620 150.355 ;
        RECT 118.320 150.355 119.485 150.495 ;
        RECT 120.345 150.415 120.635 150.645 ;
        RECT 123.745 150.600 124.070 150.645 ;
        RECT 121.875 150.495 122.165 150.540 ;
        RECT 121.540 150.355 122.165 150.495 ;
        RECT 123.555 150.460 124.070 150.600 ;
        RECT 123.745 150.415 124.070 150.460 ;
        RECT 123.750 150.400 124.070 150.415 ;
        RECT 118.320 150.260 118.460 150.355 ;
        RECT 118.985 150.310 119.380 150.355 ;
        RECT 113.885 150.120 115.240 150.260 ;
        RECT 116.480 150.120 118.460 150.260 ;
        RECT 113.885 150.075 114.175 150.120 ;
        RECT 45.640 149.780 51.300 149.920 ;
        RECT 115.100 149.920 115.240 150.120 ;
        RECT 119.240 149.980 119.380 150.310 ;
        RECT 116.850 149.920 117.170 149.980 ;
        RECT 115.100 149.780 117.170 149.920 ;
        RECT 38.190 149.720 38.510 149.780 ;
        RECT 43.335 149.735 43.625 149.780 ;
        RECT 116.850 149.720 117.170 149.780 ;
        RECT 117.625 149.920 117.915 149.965 ;
        RECT 118.690 149.920 119.010 149.980 ;
        RECT 117.625 149.780 119.010 149.920 ;
        RECT 117.625 149.735 117.915 149.780 ;
        RECT 118.690 149.720 119.010 149.780 ;
        RECT 119.150 149.920 119.470 149.980 ;
        RECT 121.540 149.920 121.680 150.355 ;
        RECT 121.875 150.310 122.165 150.355 ;
        RECT 119.150 149.780 121.680 149.920 ;
        RECT 124.425 149.920 124.715 149.965 ;
        RECT 128.350 149.920 128.670 149.980 ;
        RECT 124.425 149.780 128.670 149.920 ;
        RECT 119.150 149.720 119.470 149.780 ;
        RECT 124.425 149.735 124.715 149.780 ;
        RECT 128.350 149.720 128.670 149.780 ;
        RECT 40.280 149.100 47.000 149.425 ;
        RECT 47.480 149.100 54.200 149.425 ;
        RECT 60.920 149.100 65.240 149.425 ;
        RECT 66.200 149.100 67.640 149.425 ;
        RECT 68.600 149.100 83.000 149.425 ;
        RECT 111.320 149.100 124.760 149.425 ;
        RECT 37.880 148.500 127.160 149.100 ;
        RECT 40.280 148.175 50.360 148.500 ;
        RECT 52.760 148.175 59.960 148.500 ;
        RECT 63.320 148.175 64.760 148.500 ;
        RECT 68.120 148.175 75.320 148.500 ;
        RECT 117.080 148.175 127.160 148.500 ;
        RECT 64.410 147.925 64.730 147.940 ;
        RECT 40.860 147.740 43.940 147.880 ;
        RECT 40.860 147.245 41.000 147.740 ;
        RECT 41.410 147.540 41.730 147.600 ;
        RECT 42.825 147.540 43.115 147.585 ;
        RECT 41.410 147.400 43.115 147.540 ;
        RECT 43.800 147.540 43.940 147.740 ;
        RECT 64.245 147.695 64.730 147.925 ;
        RECT 64.410 147.680 64.730 147.695 ;
        RECT 43.800 147.400 47.800 147.540 ;
        RECT 41.410 147.340 41.730 147.400 ;
        RECT 42.825 147.355 43.115 147.400 ;
        RECT 39.765 147.200 40.055 147.245 ;
        RECT 40.785 147.200 41.075 147.245 ;
        RECT 39.765 147.060 41.075 147.200 ;
        RECT 42.900 147.200 43.040 147.355 ;
        RECT 44.260 147.245 44.400 147.400 ;
        RECT 47.660 147.245 47.800 147.400 ;
        RECT 119.240 147.400 124.640 147.540 ;
        RECT 119.240 147.260 119.380 147.400 ;
        RECT 53.830 147.245 54.150 147.260 ;
        RECT 42.900 147.060 43.940 147.200 ;
        RECT 39.765 147.015 40.055 147.060 ;
        RECT 40.785 147.015 41.075 147.060 ;
        RECT 43.800 146.860 43.940 147.060 ;
        RECT 44.185 147.015 44.475 147.245 ;
        RECT 46.225 147.015 46.515 147.245 ;
        RECT 47.585 147.015 47.875 147.245 ;
        RECT 49.285 147.015 49.575 147.245 ;
        RECT 53.705 147.015 54.150 147.245 ;
        RECT 46.300 146.860 46.440 147.015 ;
        RECT 49.360 146.860 49.500 147.015 ;
        RECT 53.830 147.000 54.150 147.015 ;
        RECT 58.890 147.200 59.210 147.260 ;
        RECT 69.010 147.245 69.330 147.260 ;
        RECT 63.565 147.200 63.855 147.245 ;
        RECT 69.005 147.200 69.330 147.245 ;
        RECT 58.890 147.060 63.855 147.200 ;
        RECT 68.815 147.060 69.330 147.200 ;
        RECT 58.890 147.000 59.210 147.060 ;
        RECT 63.565 147.015 63.855 147.060 ;
        RECT 69.005 147.015 69.330 147.060 ;
        RECT 117.965 147.200 118.255 147.245 ;
        RECT 119.150 147.200 119.470 147.260 ;
        RECT 121.100 147.245 121.240 147.400 ;
        RECT 117.965 147.060 119.470 147.200 ;
        RECT 117.965 147.015 118.255 147.060 ;
        RECT 69.010 147.000 69.330 147.015 ;
        RECT 119.150 147.000 119.470 147.060 ;
        RECT 119.665 147.015 119.955 147.245 ;
        RECT 121.025 147.015 121.315 147.245 ;
        RECT 122.725 147.200 123.015 147.245 ;
        RECT 123.750 147.200 124.070 147.260 ;
        RECT 124.500 147.245 124.640 147.400 ;
        RECT 122.000 147.060 124.070 147.200 ;
        RECT 42.420 146.720 43.480 146.860 ;
        RECT 43.800 146.720 49.500 146.860 ;
        RECT 38.650 146.520 38.970 146.580 ;
        RECT 42.420 146.520 42.560 146.720 ;
        RECT 38.650 146.380 42.560 146.520 ;
        RECT 43.340 146.520 43.480 146.720 ;
        RECT 49.965 146.520 50.255 146.565 ;
        RECT 43.340 146.380 50.255 146.520 ;
        RECT 69.100 146.520 69.240 147.000 ;
        RECT 116.850 146.860 117.170 146.920 ;
        RECT 119.700 146.860 119.840 147.015 ;
        RECT 122.000 146.860 122.140 147.060 ;
        RECT 122.725 147.015 123.015 147.060 ;
        RECT 123.750 147.000 124.070 147.060 ;
        RECT 124.425 147.015 124.715 147.245 ;
        RECT 116.850 146.720 122.140 146.860 ;
        RECT 123.840 146.860 123.980 147.000 ;
        RECT 126.125 146.860 126.415 146.905 ;
        RECT 123.840 146.720 126.415 146.860 ;
        RECT 116.850 146.660 117.170 146.720 ;
        RECT 126.125 146.675 126.415 146.720 ;
        RECT 71.045 146.520 71.335 146.565 ;
        RECT 69.100 146.380 71.335 146.520 ;
        RECT 38.650 146.320 38.970 146.380 ;
        RECT 49.965 146.335 50.255 146.380 ;
        RECT 71.045 146.335 71.335 146.380 ;
        RECT 120.005 146.520 120.295 146.565 ;
        RECT 120.990 146.520 121.310 146.580 ;
        RECT 120.005 146.380 121.310 146.520 ;
        RECT 120.005 146.335 120.295 146.380 ;
        RECT 120.990 146.320 121.310 146.380 ;
        RECT 39.110 146.180 39.430 146.240 ;
        RECT 46.565 146.180 46.855 146.225 ;
        RECT 39.110 146.040 46.855 146.180 ;
        RECT 39.110 145.980 39.430 146.040 ;
        RECT 46.565 145.995 46.855 146.040 ;
        RECT 38.190 145.840 38.510 145.900 ;
        RECT 58.890 145.885 59.210 145.900 ;
        RECT 43.335 145.840 43.625 145.885 ;
        RECT 38.190 145.700 43.625 145.840 ;
        RECT 38.190 145.640 38.510 145.700 ;
        RECT 43.335 145.655 43.625 145.700 ;
        RECT 58.805 145.655 59.210 145.885 ;
        RECT 123.405 145.840 123.695 145.885 ;
        RECT 126.050 145.840 126.370 145.900 ;
        RECT 123.405 145.700 126.370 145.840 ;
        RECT 123.405 145.655 123.695 145.700 ;
        RECT 58.890 145.640 59.210 145.655 ;
        RECT 126.050 145.640 126.370 145.700 ;
        RECT 126.805 145.840 127.095 145.885 ;
        RECT 129.730 145.840 130.050 145.900 ;
        RECT 126.805 145.700 130.050 145.840 ;
        RECT 126.805 145.655 127.095 145.700 ;
        RECT 129.730 145.640 130.050 145.700 ;
        RECT 40.280 145.030 50.360 145.355 ;
        RECT 52.760 145.030 59.960 145.355 ;
        RECT 63.320 145.030 64.760 145.355 ;
        RECT 68.120 145.030 75.320 145.355 ;
        RECT 117.080 145.030 127.160 145.355 ;
        RECT 37.880 144.430 127.160 145.030 ;
        RECT 40.280 144.105 47.000 144.430 ;
        RECT 48.920 144.105 52.280 144.430 ;
        RECT 53.240 144.105 67.640 144.430 ;
        RECT 74.360 144.105 81.560 144.430 ;
        RECT 116.120 144.105 126.200 144.430 ;
        RECT 76.370 143.800 76.690 143.860 ;
        RECT 77.165 143.800 77.455 143.845 ;
        RECT 76.370 143.660 77.455 143.800 ;
        RECT 76.370 143.600 76.690 143.660 ;
        RECT 77.165 143.615 77.455 143.660 ;
        RECT 39.110 143.120 39.430 143.180 ;
        RECT 46.565 143.120 46.855 143.165 ;
        RECT 39.110 142.980 46.855 143.120 ;
        RECT 39.110 142.920 39.430 142.980 ;
        RECT 46.565 142.935 46.855 142.980 ;
        RECT 41.410 142.780 41.730 142.840 ;
        RECT 42.825 142.780 43.115 142.825 ;
        RECT 51.325 142.780 51.615 142.825 ;
        RECT 41.410 142.640 51.615 142.780 ;
        RECT 41.410 142.580 41.730 142.640 ;
        RECT 42.825 142.595 43.115 142.640 ;
        RECT 46.300 142.485 46.440 142.640 ;
        RECT 51.325 142.595 51.615 142.640 ;
        RECT 119.155 142.780 119.445 142.825 ;
        RECT 126.050 142.780 126.370 142.840 ;
        RECT 119.155 142.640 126.370 142.780 ;
        RECT 119.155 142.595 119.445 142.640 ;
        RECT 126.050 142.580 126.370 142.640 ;
        RECT 52.035 142.500 52.265 142.515 ;
        RECT 39.765 142.355 40.055 142.400 ;
        RECT 41.295 142.355 41.585 142.400 ;
        RECT 41.870 142.355 42.190 142.415 ;
        RECT 44.185 142.355 44.475 142.400 ;
        RECT 39.765 142.215 45.780 142.355 ;
        RECT 46.225 142.255 46.515 142.485 ;
        RECT 49.455 142.355 49.745 142.400 ;
        RECT 39.765 142.170 40.055 142.215 ;
        RECT 41.295 142.170 41.585 142.215 ;
        RECT 41.870 142.155 42.190 142.215 ;
        RECT 44.185 142.170 44.475 142.215 ;
        RECT 45.640 142.100 45.780 142.215 ;
        RECT 48.170 142.215 49.745 142.355 ;
        RECT 51.990 142.240 52.310 142.500 ;
        RECT 58.890 142.440 59.210 142.500 ;
        RECT 59.485 142.440 59.775 142.485 ;
        RECT 60.195 142.440 60.425 142.515 ;
        RECT 76.370 142.485 76.690 142.500 ;
        RECT 60.845 142.440 61.135 142.485 ;
        RECT 58.890 142.300 61.135 142.440 ;
        RECT 58.890 142.240 59.210 142.300 ;
        RECT 59.485 142.255 59.775 142.300 ;
        RECT 52.035 142.225 52.265 142.240 ;
        RECT 60.195 142.225 60.425 142.300 ;
        RECT 60.845 142.255 61.135 142.300 ;
        RECT 76.370 142.255 76.775 142.485 ;
        RECT 124.210 142.440 124.530 142.500 ;
        RECT 125.105 142.440 125.395 142.485 ;
        RECT 117.860 142.400 120.560 142.440 ;
        RECT 121.540 142.415 122.600 142.440 ;
        RECT 117.115 142.355 117.405 142.400 ;
        RECT 117.860 142.355 120.805 142.400 ;
        RECT 121.450 142.355 122.600 142.415 ;
        RECT 123.405 142.355 123.695 142.400 ;
        RECT 117.115 142.300 123.695 142.355 ;
        RECT 76.370 142.240 76.690 142.255 ;
        RECT 48.170 142.100 48.310 142.215 ;
        RECT 49.455 142.170 49.745 142.215 ;
        RECT 117.115 142.215 118.000 142.300 ;
        RECT 117.115 142.170 117.405 142.215 ;
        RECT 119.150 142.155 119.470 142.300 ;
        RECT 120.420 142.215 121.770 142.300 ;
        RECT 122.460 142.215 123.695 142.300 ;
        RECT 124.210 142.300 125.395 142.440 ;
        RECT 124.210 142.240 124.530 142.300 ;
        RECT 125.105 142.255 125.395 142.300 ;
        RECT 120.515 142.170 120.805 142.215 ;
        RECT 121.450 142.155 121.770 142.215 ;
        RECT 123.405 142.170 123.695 142.215 ;
        RECT 45.640 141.960 48.310 142.100 ;
        RECT 118.645 141.915 118.935 142.145 ;
        RECT 122.045 141.915 122.335 142.145 ;
        RECT 34.970 141.760 35.290 141.820 ;
        RECT 66.710 141.805 67.030 141.820 ;
        RECT 43.335 141.760 43.625 141.805 ;
        RECT 34.970 141.620 43.625 141.760 ;
        RECT 34.970 141.560 35.290 141.620 ;
        RECT 43.335 141.575 43.625 141.620 ;
        RECT 66.625 141.575 67.030 141.805 ;
        RECT 118.720 141.760 118.860 141.915 ;
        RECT 119.150 141.760 119.470 141.820 ;
        RECT 122.120 141.760 122.260 141.915 ;
        RECT 118.720 141.620 122.260 141.760 ;
        RECT 122.585 141.760 122.815 141.835 ;
        RECT 124.210 141.760 124.530 141.820 ;
        RECT 122.585 141.620 124.530 141.760 ;
        RECT 66.710 141.560 67.030 141.575 ;
        RECT 119.150 141.560 119.470 141.620 ;
        RECT 122.585 141.545 122.815 141.620 ;
        RECT 124.210 141.560 124.530 141.620 ;
        RECT 125.785 141.760 126.075 141.805 ;
        RECT 129.270 141.760 129.590 141.820 ;
        RECT 125.785 141.620 129.590 141.760 ;
        RECT 125.785 141.575 126.075 141.620 ;
        RECT 129.270 141.560 129.590 141.620 ;
        RECT 40.280 140.960 47.000 141.285 ;
        RECT 48.920 140.960 52.280 141.285 ;
        RECT 53.240 140.960 67.640 141.285 ;
        RECT 74.360 140.960 81.560 141.285 ;
        RECT 116.120 140.960 126.200 141.285 ;
        RECT 37.880 140.360 127.160 140.960 ;
        RECT 40.280 140.035 43.640 140.360 ;
        RECT 44.600 140.035 51.320 140.360 ;
        RECT 62.360 140.035 69.560 140.360 ;
        RECT 72.440 140.035 79.640 140.360 ;
        RECT 118.040 140.035 124.760 140.360 ;
        RECT 41.410 139.720 41.730 139.780 ;
        RECT 74.070 139.720 74.390 139.780 ;
        RECT 76.370 139.720 76.690 139.780 ;
        RECT 78.525 139.720 78.815 139.765 ;
        RECT 41.410 139.580 43.040 139.720 ;
        RECT 41.410 139.520 41.730 139.580 ;
        RECT 42.900 139.425 43.040 139.580 ;
        RECT 66.625 139.500 66.925 139.550 ;
        RECT 68.350 139.500 68.650 139.550 ;
        RECT 71.000 139.500 71.475 139.600 ;
        RECT 74.070 139.580 78.815 139.720 ;
        RECT 74.070 139.520 74.390 139.580 ;
        RECT 76.370 139.520 76.690 139.580 ;
        RECT 78.525 139.535 78.815 139.580 ;
        RECT 42.825 139.380 43.115 139.425 ;
        RECT 44.185 139.380 44.475 139.425 ;
        RECT 42.825 139.240 44.475 139.380 ;
        RECT 66.625 139.350 71.475 139.500 ;
        RECT 66.625 139.300 66.925 139.350 ;
        RECT 68.350 139.300 68.650 139.350 ;
        RECT 71.000 139.250 71.475 139.350 ;
        RECT 42.825 139.195 43.115 139.240 ;
        RECT 44.185 139.195 44.475 139.240 ;
        RECT 41.295 139.100 41.585 139.145 ;
        RECT 41.870 139.100 42.190 139.160 ;
        RECT 121.910 139.145 122.230 139.160 ;
        RECT 45.205 139.100 45.495 139.145 ;
        RECT 48.435 139.100 48.725 139.145 ;
        RECT 118.985 139.100 119.275 139.145 ;
        RECT 121.875 139.100 122.230 139.145 ;
        RECT 41.295 139.040 42.190 139.100 ;
        RECT 44.720 139.040 48.725 139.100 ;
        RECT 41.295 138.960 48.725 139.040 ;
        RECT 41.295 138.915 41.585 138.960 ;
        RECT 41.870 138.900 44.860 138.960 ;
        RECT 45.205 138.915 45.495 138.960 ;
        RECT 48.435 138.915 48.725 138.960 ;
        RECT 66.710 139.040 67.030 139.100 ;
        RECT 68.665 139.040 68.955 139.085 ;
        RECT 70.365 139.040 70.655 139.085 ;
        RECT 66.710 138.900 70.655 139.040 ;
        RECT 66.710 138.840 67.030 138.900 ;
        RECT 68.665 138.855 68.955 138.900 ;
        RECT 70.365 138.855 70.655 138.900 ;
        RECT 78.865 139.040 79.155 139.085 ;
        RECT 79.885 139.040 80.175 139.085 ;
        RECT 78.865 138.900 80.175 139.040 ;
        RECT 118.985 138.960 122.230 139.100 ;
        RECT 118.985 138.915 119.275 138.960 ;
        RECT 121.875 138.915 122.230 138.960 ;
        RECT 121.910 138.900 122.230 138.915 ;
        RECT 78.865 138.855 79.155 138.900 ;
        RECT 79.885 138.855 80.175 138.900 ;
        RECT 39.110 138.700 39.430 138.760 ;
        RECT 44.170 138.700 44.490 138.760 ;
        RECT 46.905 138.700 47.195 138.745 ;
        RECT 50.305 138.700 50.595 138.745 ;
        RECT 39.110 138.560 43.480 138.700 ;
        RECT 39.110 138.500 39.430 138.560 ;
        RECT 43.340 138.360 43.480 138.560 ;
        RECT 44.170 138.560 50.595 138.700 ;
        RECT 44.170 138.500 44.490 138.560 ;
        RECT 46.905 138.515 47.195 138.560 ;
        RECT 50.305 138.515 50.595 138.560 ;
        RECT 119.150 138.700 119.470 138.760 ;
        RECT 123.750 138.745 124.070 138.760 ;
        RECT 120.345 138.700 120.635 138.745 ;
        RECT 123.745 138.700 124.070 138.745 ;
        RECT 119.150 138.560 124.070 138.700 ;
        RECT 119.150 138.500 119.470 138.560 ;
        RECT 120.345 138.515 120.635 138.560 ;
        RECT 123.745 138.515 124.070 138.560 ;
        RECT 123.750 138.500 124.070 138.515 ;
        RECT 50.985 138.360 51.275 138.405 ;
        RECT 43.340 138.220 51.275 138.360 ;
        RECT 50.985 138.175 51.275 138.220 ;
        RECT 121.025 138.360 121.315 138.405 ;
        RECT 126.510 138.360 126.830 138.420 ;
        RECT 121.025 138.220 126.830 138.360 ;
        RECT 121.025 138.175 121.315 138.220 ;
        RECT 126.510 138.160 126.830 138.220 ;
        RECT 46.930 138.020 47.250 138.080 ;
        RECT 47.585 138.020 47.875 138.065 ;
        RECT 46.930 137.880 47.875 138.020 ;
        RECT 46.930 137.820 47.250 137.880 ;
        RECT 47.585 137.835 47.875 137.880 ;
        RECT 37.270 137.680 37.590 137.740 ;
        RECT 43.335 137.680 43.625 137.725 ;
        RECT 37.270 137.540 43.625 137.680 ;
        RECT 37.270 137.480 37.590 137.540 ;
        RECT 43.335 137.495 43.625 137.540 ;
        RECT 124.425 137.680 124.715 137.725 ;
        RECT 128.350 137.680 128.670 137.740 ;
        RECT 124.425 137.540 128.670 137.680 ;
        RECT 124.425 137.495 124.715 137.540 ;
        RECT 128.350 137.480 128.670 137.540 ;
        RECT 40.280 136.890 43.640 137.215 ;
        RECT 44.600 136.890 51.320 137.215 ;
        RECT 62.360 136.890 69.560 137.215 ;
        RECT 72.440 136.890 79.640 137.215 ;
        RECT 118.040 136.890 124.760 137.215 ;
        RECT 37.880 136.290 127.160 136.890 ;
        RECT 37.880 135.965 47.960 136.290 ;
        RECT 62.840 135.965 70.040 136.290 ;
        RECT 71.960 135.965 79.160 136.290 ;
        RECT 111.320 135.965 124.760 136.290 ;
        RECT 44.170 135.640 44.490 135.700 ;
        RECT 40.580 135.500 44.490 135.640 ;
        RECT 40.580 135.005 40.720 135.500 ;
        RECT 44.170 135.440 44.490 135.500 ;
        RECT 114.425 135.640 114.655 135.715 ;
        RECT 116.390 135.640 116.710 135.700 ;
        RECT 114.425 135.500 116.710 135.640 ;
        RECT 114.425 135.425 114.655 135.500 ;
        RECT 116.390 135.440 116.710 135.500 ;
        RECT 40.445 134.775 40.735 135.005 ;
        RECT 36.810 134.620 37.130 134.680 ;
        RECT 40.985 134.620 41.215 134.695 ;
        RECT 46.905 134.620 47.195 134.665 ;
        RECT 69.685 134.620 69.975 134.665 ;
        RECT 70.365 134.620 70.655 134.665 ;
        RECT 78.865 134.620 79.155 134.665 ;
        RECT 79.885 134.620 80.175 134.665 ;
        RECT 36.810 134.480 41.215 134.620 ;
        RECT 36.810 134.420 37.130 134.480 ;
        RECT 40.985 134.405 41.215 134.480 ;
        RECT 44.260 134.480 47.195 134.620 ;
        RECT 44.260 134.340 44.400 134.480 ;
        RECT 46.905 134.435 47.195 134.480 ;
        RECT 69.560 134.480 80.175 134.620 ;
        RECT 69.560 134.435 69.975 134.480 ;
        RECT 70.365 134.435 70.655 134.480 ;
        RECT 78.865 134.435 79.155 134.480 ;
        RECT 79.885 134.435 80.175 134.480 ;
        RECT 113.885 134.620 114.175 134.665 ;
        RECT 119.150 134.620 119.470 134.680 ;
        RECT 120.345 134.620 120.635 134.665 ;
        RECT 113.885 134.480 120.635 134.620 ;
        RECT 113.885 134.435 114.175 134.480 ;
        RECT 43.505 134.280 43.795 134.325 ;
        RECT 44.170 134.280 44.490 134.340 ;
        RECT 69.560 134.325 69.700 134.435 ;
        RECT 41.870 134.260 42.190 134.275 ;
        RECT 38.915 134.215 39.205 134.260 ;
        RECT 41.805 134.215 42.190 134.260 ;
        RECT 38.915 134.075 43.040 134.215 ;
        RECT 43.505 134.140 44.490 134.280 ;
        RECT 45.205 134.215 45.495 134.260 ;
        RECT 43.505 134.095 43.795 134.140 ;
        RECT 44.170 134.080 44.490 134.140 ;
        RECT 38.915 134.030 39.205 134.075 ;
        RECT 41.805 134.030 42.190 134.075 ;
        RECT 41.870 134.015 42.190 134.030 ;
        RECT 42.900 133.940 43.040 134.075 ;
        RECT 44.720 134.075 45.495 134.215 ;
        RECT 69.345 134.140 69.700 134.325 ;
        RECT 74.070 134.325 74.390 134.340 ;
        RECT 117.020 134.325 117.160 134.480 ;
        RECT 119.150 134.420 119.470 134.480 ;
        RECT 120.345 134.435 120.635 134.480 ;
        RECT 121.025 134.620 121.315 134.665 ;
        RECT 126.510 134.620 126.830 134.680 ;
        RECT 121.025 134.480 126.830 134.620 ;
        RECT 121.025 134.435 121.315 134.480 ;
        RECT 126.510 134.420 126.830 134.480 ;
        RECT 123.750 134.325 124.070 134.340 ;
        RECT 74.070 134.280 74.395 134.325 ;
        RECT 74.070 134.140 74.585 134.280 ;
        RECT 112.355 134.215 112.645 134.260 ;
        RECT 115.755 134.215 116.045 134.260 ;
        RECT 69.345 134.095 69.635 134.140 ;
        RECT 74.070 134.095 74.395 134.140 ;
        RECT 74.070 134.080 74.390 134.095 ;
        RECT 44.720 133.940 44.860 134.075 ;
        RECT 45.205 134.030 45.495 134.075 ;
        RECT 112.355 134.075 116.160 134.215 ;
        RECT 116.945 134.095 117.235 134.325 ;
        RECT 123.745 134.280 124.070 134.325 ;
        RECT 117.400 134.260 119.065 134.280 ;
        RECT 121.910 134.260 122.230 134.275 ;
        RECT 117.400 134.215 119.275 134.260 ;
        RECT 121.875 134.215 122.230 134.260 ;
        RECT 117.400 134.140 122.230 134.215 ;
        RECT 123.555 134.140 124.070 134.280 ;
        RECT 112.355 134.030 112.645 134.075 ;
        RECT 115.755 134.030 116.160 134.075 ;
        RECT 42.900 133.800 44.860 133.940 ;
        RECT 116.020 133.940 116.160 134.030 ;
        RECT 117.400 133.940 117.540 134.140 ;
        RECT 118.925 134.075 122.230 134.140 ;
        RECT 123.745 134.095 124.070 134.140 ;
        RECT 123.750 134.080 124.070 134.095 ;
        RECT 118.985 134.030 119.275 134.075 ;
        RECT 121.875 134.030 122.230 134.075 ;
        RECT 121.910 134.015 122.230 134.030 ;
        RECT 116.020 133.800 117.540 133.940 ;
        RECT 38.650 133.600 38.970 133.660 ;
        RECT 44.185 133.600 44.475 133.645 ;
        RECT 38.650 133.460 44.475 133.600 ;
        RECT 38.650 133.400 38.970 133.460 ;
        RECT 44.185 133.415 44.475 133.460 ;
        RECT 46.930 133.600 47.250 133.660 ;
        RECT 47.585 133.600 47.875 133.645 ;
        RECT 46.930 133.460 47.875 133.600 ;
        RECT 46.930 133.400 47.250 133.460 ;
        RECT 47.585 133.415 47.875 133.460 ;
        RECT 117.625 133.600 117.915 133.645 ;
        RECT 118.690 133.600 119.010 133.660 ;
        RECT 117.625 133.460 119.010 133.600 ;
        RECT 117.625 133.415 117.915 133.460 ;
        RECT 118.690 133.400 119.010 133.460 ;
        RECT 124.425 133.600 124.715 133.645 ;
        RECT 128.350 133.600 128.670 133.660 ;
        RECT 124.425 133.460 128.670 133.600 ;
        RECT 124.425 133.415 124.715 133.460 ;
        RECT 128.350 133.400 128.670 133.460 ;
        RECT 37.880 132.820 47.960 133.145 ;
        RECT 62.840 132.820 70.040 133.145 ;
        RECT 71.960 132.820 79.160 133.145 ;
        RECT 111.320 132.820 124.760 133.145 ;
        RECT 37.880 132.220 127.160 132.820 ;
        RECT 40.280 131.895 47.000 132.220 ;
        RECT 118.040 131.895 124.760 132.220 ;
        RECT 118.720 131.420 122.090 131.560 ;
        RECT 39.765 130.960 40.055 131.005 ;
        RECT 40.785 130.960 41.075 131.005 ;
        RECT 41.870 130.960 42.190 131.020 ;
        RECT 118.720 131.005 118.860 131.420 ;
        RECT 121.950 131.020 122.090 131.420 ;
        RECT 121.910 131.005 122.230 131.020 ;
        RECT 44.185 130.960 44.475 131.005 ;
        RECT 39.765 130.820 44.475 130.960 ;
        RECT 39.765 130.775 40.055 130.820 ;
        RECT 40.785 130.775 41.075 130.820 ;
        RECT 41.870 130.760 42.190 130.820 ;
        RECT 44.185 130.775 44.475 130.820 ;
        RECT 46.225 130.695 46.515 130.925 ;
        RECT 118.645 130.775 118.935 131.005 ;
        RECT 121.875 130.960 122.230 131.005 ;
        RECT 119.150 130.880 119.470 130.940 ;
        RECT 120.345 130.880 120.635 130.925 ;
        RECT 119.150 130.740 120.760 130.880 ;
        RECT 121.715 130.820 122.230 130.960 ;
        RECT 123.750 130.925 124.070 130.940 ;
        RECT 123.745 130.880 124.070 130.925 ;
        RECT 121.875 130.775 122.230 130.820 ;
        RECT 121.910 130.760 122.230 130.775 ;
        RECT 123.555 130.740 124.070 130.880 ;
        RECT 42.825 130.540 43.115 130.585 ;
        RECT 44.170 130.540 44.490 130.600 ;
        RECT 46.300 130.540 46.440 130.695 ;
        RECT 119.150 130.680 119.470 130.740 ;
        RECT 120.345 130.695 120.760 130.740 ;
        RECT 123.745 130.695 124.070 130.740 ;
        RECT 46.930 130.540 47.250 130.600 ;
        RECT 42.825 130.400 47.250 130.540 ;
        RECT 120.620 130.540 120.760 130.695 ;
        RECT 123.750 130.680 124.070 130.695 ;
        RECT 123.820 130.540 123.960 130.680 ;
        RECT 120.620 130.400 123.960 130.540 ;
        RECT 42.825 130.355 43.115 130.400 ;
        RECT 44.170 130.340 44.490 130.400 ;
        RECT 46.930 130.340 47.250 130.400 ;
        RECT 121.025 130.200 121.315 130.245 ;
        RECT 126.510 130.200 126.830 130.260 ;
        RECT 121.025 130.060 126.830 130.200 ;
        RECT 121.025 130.015 121.315 130.060 ;
        RECT 126.510 130.000 126.830 130.060 ;
        RECT 39.110 129.860 39.430 129.920 ;
        RECT 46.565 129.860 46.855 129.905 ;
        RECT 39.110 129.720 46.855 129.860 ;
        RECT 39.110 129.660 39.430 129.720 ;
        RECT 46.565 129.675 46.855 129.720 ;
        RECT 38.190 129.520 38.510 129.580 ;
        RECT 43.335 129.520 43.625 129.565 ;
        RECT 38.190 129.380 43.625 129.520 ;
        RECT 38.190 129.320 38.510 129.380 ;
        RECT 43.335 129.335 43.625 129.380 ;
        RECT 124.425 129.520 124.715 129.565 ;
        RECT 128.350 129.520 128.670 129.580 ;
        RECT 124.425 129.380 128.670 129.520 ;
        RECT 124.425 129.335 124.715 129.380 ;
        RECT 128.350 129.320 128.670 129.380 ;
        RECT 40.280 128.750 47.000 129.075 ;
        RECT 118.040 128.750 124.760 129.075 ;
        RECT 37.880 128.150 127.160 128.750 ;
        RECT 44.120 127.825 54.200 128.150 ;
        RECT 118.040 127.825 124.760 128.150 ;
        RECT 39.110 127.480 39.430 127.540 ;
        RECT 50.475 127.480 50.765 127.525 ;
        RECT 39.110 127.340 50.765 127.480 ;
        RECT 39.110 127.280 39.430 127.340 ;
        RECT 50.475 127.295 50.765 127.340 ;
        RECT 124.425 127.480 124.715 127.525 ;
        RECT 126.050 127.480 126.370 127.540 ;
        RECT 124.425 127.340 126.370 127.480 ;
        RECT 124.425 127.295 124.715 127.340 ;
        RECT 126.050 127.280 126.370 127.340 ;
        RECT 123.750 126.800 124.070 126.860 ;
        RECT 120.620 126.660 124.070 126.800 ;
        RECT 39.110 126.460 39.430 126.520 ;
        RECT 53.875 126.460 54.165 126.505 ;
        RECT 39.110 126.320 54.165 126.460 ;
        RECT 39.110 126.260 39.430 126.320 ;
        RECT 53.875 126.275 54.165 126.320 ;
        RECT 39.765 126.120 40.055 126.165 ;
        RECT 44.865 126.120 45.155 126.165 ;
        RECT 48.265 126.120 48.555 126.165 ;
        RECT 51.325 126.120 51.615 126.165 ;
        RECT 39.765 125.980 51.615 126.120 ;
        RECT 39.765 125.935 40.055 125.980 ;
        RECT 44.865 125.935 45.155 125.980 ;
        RECT 48.265 125.935 48.555 125.980 ;
        RECT 51.325 125.935 51.615 125.980 ;
        RECT 116.850 126.120 117.170 126.180 ;
        RECT 120.620 126.165 120.760 126.660 ;
        RECT 123.750 126.600 124.070 126.660 ;
        RECT 121.025 126.460 121.315 126.505 ;
        RECT 126.510 126.460 126.830 126.520 ;
        RECT 121.025 126.320 126.830 126.460 ;
        RECT 121.025 126.275 121.315 126.320 ;
        RECT 126.510 126.260 126.830 126.320 ;
        RECT 118.645 126.120 118.935 126.165 ;
        RECT 116.850 125.980 118.935 126.120 ;
        RECT 116.850 125.920 117.170 125.980 ;
        RECT 118.645 125.935 118.935 125.980 ;
        RECT 120.345 125.980 120.760 126.165 ;
        RECT 121.910 126.165 122.230 126.180 ;
        RECT 123.750 126.165 124.070 126.180 ;
        RECT 120.345 125.935 120.635 125.980 ;
        RECT 121.910 125.935 122.335 126.165 ;
        RECT 123.745 126.120 124.070 126.165 ;
        RECT 123.555 125.980 124.070 126.120 ;
        RECT 123.745 125.935 124.070 125.980 ;
        RECT 46.470 125.825 46.790 125.840 ;
        RECT 46.470 125.780 46.855 125.825 ;
        RECT 49.965 125.780 50.255 125.825 ;
        RECT 53.365 125.780 53.655 125.825 ;
        RECT 46.470 125.640 53.655 125.780 ;
        RECT 118.720 125.780 118.860 125.935 ;
        RECT 121.910 125.920 122.230 125.935 ;
        RECT 123.750 125.920 124.070 125.935 ;
        RECT 122.000 125.780 122.140 125.920 ;
        RECT 118.720 125.640 122.140 125.780 ;
        RECT 46.470 125.595 46.855 125.640 ;
        RECT 49.965 125.595 50.255 125.640 ;
        RECT 53.365 125.595 53.655 125.640 ;
        RECT 46.470 125.580 46.790 125.595 ;
        RECT 39.110 125.440 39.430 125.500 ;
        RECT 47.075 125.440 47.365 125.485 ;
        RECT 39.110 125.300 47.365 125.440 ;
        RECT 39.110 125.240 39.430 125.300 ;
        RECT 47.075 125.255 47.365 125.300 ;
        RECT 44.120 124.680 54.200 125.005 ;
        RECT 118.040 124.680 124.760 125.005 ;
        RECT 37.880 124.080 127.160 124.680 ;
        RECT 40.280 123.755 47.000 124.080 ;
        RECT 115.160 123.755 125.240 124.080 ;
        RECT 39.110 123.400 39.430 123.460 ;
        RECT 43.335 123.400 43.625 123.445 ;
        RECT 39.110 123.260 43.625 123.400 ;
        RECT 39.110 123.200 39.430 123.260 ;
        RECT 43.335 123.215 43.625 123.260 ;
        RECT 124.935 123.400 125.225 123.445 ;
        RECT 126.050 123.400 126.370 123.460 ;
        RECT 124.935 123.260 126.370 123.400 ;
        RECT 124.935 123.215 125.225 123.260 ;
        RECT 126.050 123.200 126.370 123.260 ;
        RECT 39.765 122.820 40.055 122.865 ;
        RECT 40.785 122.820 41.075 122.865 ;
        RECT 44.185 122.820 44.475 122.865 ;
        RECT 39.765 122.680 44.475 122.820 ;
        RECT 115.755 122.820 116.045 122.865 ;
        RECT 116.850 122.820 117.170 122.880 ;
        RECT 118.985 122.820 119.275 122.865 ;
        RECT 122.385 122.820 122.675 122.865 ;
        RECT 39.765 122.635 40.055 122.680 ;
        RECT 40.785 122.635 41.075 122.680 ;
        RECT 44.185 122.635 44.475 122.680 ;
        RECT 46.225 122.720 46.515 122.765 ;
        RECT 46.930 122.720 47.250 122.780 ;
        RECT 46.225 122.580 47.250 122.720 ;
        RECT 115.755 122.680 122.675 122.820 ;
        RECT 115.755 122.635 116.045 122.680 ;
        RECT 116.850 122.620 117.170 122.680 ;
        RECT 118.985 122.635 119.275 122.680 ;
        RECT 122.385 122.635 122.675 122.680 ;
        RECT 46.225 122.535 46.515 122.580 ;
        RECT 42.825 122.380 43.115 122.425 ;
        RECT 46.300 122.380 46.440 122.535 ;
        RECT 46.930 122.520 47.250 122.580 ;
        RECT 42.825 122.240 46.440 122.380 ;
        RECT 123.750 122.380 124.070 122.440 ;
        RECT 124.425 122.380 124.715 122.425 ;
        RECT 123.750 122.240 124.715 122.380 ;
        RECT 42.825 122.195 43.115 122.240 ;
        RECT 123.750 122.180 124.070 122.240 ;
        RECT 124.425 122.195 124.715 122.240 ;
        RECT 116.390 122.040 116.710 122.100 ;
        RECT 117.625 122.040 117.915 122.085 ;
        RECT 116.390 121.900 117.915 122.040 ;
        RECT 116.390 121.840 116.710 121.900 ;
        RECT 117.625 121.855 117.915 121.900 ;
        RECT 118.135 122.040 118.425 122.085 ;
        RECT 118.690 122.040 119.010 122.100 ;
        RECT 118.135 121.900 119.010 122.040 ;
        RECT 118.135 121.855 118.425 121.900 ;
        RECT 118.690 121.840 119.010 121.900 ;
        RECT 121.025 122.040 121.315 122.085 ;
        RECT 123.840 122.040 123.980 122.180 ;
        RECT 121.025 121.900 123.980 122.040 ;
        RECT 121.025 121.855 121.315 121.900 ;
        RECT 39.110 121.700 39.430 121.760 ;
        RECT 46.565 121.700 46.855 121.745 ;
        RECT 39.110 121.560 46.855 121.700 ;
        RECT 39.110 121.500 39.430 121.560 ;
        RECT 46.565 121.515 46.855 121.560 ;
        RECT 121.535 121.360 121.825 121.405 ;
        RECT 124.210 121.360 124.530 121.420 ;
        RECT 121.535 121.220 124.530 121.360 ;
        RECT 121.535 121.175 121.825 121.220 ;
        RECT 124.210 121.160 124.530 121.220 ;
        RECT 40.280 120.610 47.000 120.935 ;
        RECT 115.160 120.610 125.240 120.935 ;
        RECT 37.880 120.010 127.160 120.610 ;
        RECT 40.760 119.685 50.840 120.010 ;
        RECT 114.680 119.685 124.760 120.010 ;
        RECT 46.930 118.780 47.250 119.040 ;
        RECT 40.105 118.640 40.395 118.685 ;
        RECT 43.165 118.640 43.455 118.685 ;
        RECT 47.020 118.640 47.160 118.780 ;
        RECT 49.965 118.640 50.255 118.685 ;
        RECT 40.105 118.500 50.255 118.640 ;
        RECT 40.105 118.455 40.395 118.500 ;
        RECT 43.165 118.455 43.455 118.500 ;
        RECT 41.960 118.160 44.860 118.300 ;
        RECT 39.765 117.960 40.055 118.005 ;
        RECT 41.465 117.960 41.755 118.005 ;
        RECT 41.960 117.960 42.100 118.160 ;
        RECT 44.720 118.005 44.860 118.160 ;
        RECT 46.930 118.100 47.250 118.360 ;
        RECT 44.695 117.960 44.985 118.005 ;
        RECT 47.020 117.960 47.160 118.100 ;
        RECT 48.265 117.960 48.555 118.005 ;
        RECT 39.765 117.820 42.100 117.960 ;
        RECT 42.880 117.820 44.400 117.960 ;
        RECT 39.765 117.775 40.055 117.820 ;
        RECT 41.465 117.775 41.755 117.820 ;
        RECT 39.110 117.620 39.430 117.680 ;
        RECT 42.880 117.620 43.020 117.820 ;
        RECT 39.110 117.480 43.020 117.620 ;
        RECT 39.110 117.420 39.430 117.480 ;
        RECT 38.650 117.280 38.970 117.340 ;
        RECT 43.875 117.280 44.105 117.355 ;
        RECT 38.650 117.140 44.105 117.280 ;
        RECT 44.260 117.280 44.400 117.820 ;
        RECT 44.695 117.820 48.555 117.960 ;
        RECT 44.695 117.775 44.985 117.820 ;
        RECT 48.265 117.775 48.555 117.820 ;
        RECT 46.565 117.620 46.855 117.665 ;
        RECT 48.860 117.620 49.000 118.500 ;
        RECT 49.965 118.455 50.255 118.500 ;
        RECT 116.850 118.440 117.170 118.700 ;
        RECT 116.940 118.300 117.080 118.440 ;
        RECT 115.320 118.160 118.860 118.300 ;
        RECT 115.320 118.005 115.460 118.160 ;
        RECT 115.245 117.775 115.535 118.005 ;
        RECT 116.390 117.960 116.710 118.020 ;
        RECT 118.720 118.005 118.860 118.160 ;
        RECT 121.910 118.005 122.230 118.020 ;
        RECT 123.750 118.005 124.070 118.020 ;
        RECT 116.945 117.960 117.235 118.005 ;
        RECT 116.390 117.820 117.235 117.960 ;
        RECT 116.390 117.760 116.710 117.820 ;
        RECT 116.945 117.775 117.235 117.820 ;
        RECT 118.645 117.960 118.935 118.005 ;
        RECT 121.910 117.960 122.335 118.005 ;
        RECT 123.745 117.960 124.070 118.005 ;
        RECT 118.645 117.820 122.665 117.960 ;
        RECT 123.555 117.820 124.070 117.960 ;
        RECT 118.645 117.775 118.935 117.820 ;
        RECT 121.910 117.775 122.335 117.820 ;
        RECT 123.745 117.775 124.070 117.820 ;
        RECT 46.565 117.480 49.000 117.620 ;
        RECT 117.020 117.620 117.160 117.775 ;
        RECT 121.910 117.760 122.230 117.775 ;
        RECT 123.750 117.760 124.070 117.775 ;
        RECT 120.515 117.620 120.805 117.665 ;
        RECT 117.020 117.480 120.805 117.620 ;
        RECT 46.565 117.435 46.855 117.480 ;
        RECT 120.515 117.435 120.805 117.480 ;
        RECT 121.025 117.620 121.315 117.665 ;
        RECT 126.510 117.620 126.830 117.680 ;
        RECT 121.025 117.480 126.830 117.620 ;
        RECT 121.025 117.435 121.315 117.480 ;
        RECT 126.510 117.420 126.830 117.480 ;
        RECT 47.075 117.280 47.365 117.325 ;
        RECT 44.260 117.140 47.365 117.280 ;
        RECT 38.650 117.080 38.970 117.140 ;
        RECT 43.875 117.065 44.105 117.140 ;
        RECT 47.075 117.095 47.365 117.140 ;
        RECT 48.770 117.280 49.090 117.340 ;
        RECT 50.475 117.280 50.765 117.325 ;
        RECT 48.770 117.140 50.765 117.280 ;
        RECT 48.770 117.080 49.090 117.140 ;
        RECT 50.475 117.095 50.765 117.140 ;
        RECT 117.625 117.280 117.915 117.325 ;
        RECT 119.150 117.280 119.470 117.340 ;
        RECT 117.625 117.140 119.470 117.280 ;
        RECT 117.625 117.095 117.915 117.140 ;
        RECT 119.150 117.080 119.470 117.140 ;
        RECT 124.425 117.280 124.715 117.325 ;
        RECT 126.970 117.280 127.290 117.340 ;
        RECT 124.425 117.140 127.290 117.280 ;
        RECT 124.425 117.095 124.715 117.140 ;
        RECT 126.970 117.080 127.290 117.140 ;
        RECT 40.760 116.540 50.840 116.865 ;
        RECT 114.680 116.540 124.760 116.865 ;
        RECT 37.880 115.940 127.160 116.540 ;
        RECT 40.760 115.615 54.200 115.940 ;
        RECT 114.680 115.615 124.760 115.940 ;
        RECT 38.190 115.240 38.510 115.300 ;
        RECT 43.875 115.240 44.105 115.315 ;
        RECT 38.190 115.100 44.105 115.240 ;
        RECT 38.190 115.040 38.510 115.100 ;
        RECT 43.875 115.025 44.105 115.100 ;
        RECT 49.230 115.240 49.550 115.300 ;
        RECT 120.990 115.285 121.310 115.300 ;
        RECT 50.475 115.240 50.765 115.285 ;
        RECT 49.230 115.100 50.765 115.240 ;
        RECT 49.230 115.040 49.550 115.100 ;
        RECT 50.475 115.055 50.765 115.100 ;
        RECT 120.990 115.240 121.315 115.285 ;
        RECT 124.425 115.240 124.715 115.285 ;
        RECT 126.050 115.240 126.370 115.300 ;
        RECT 120.990 115.100 121.505 115.240 ;
        RECT 124.425 115.100 126.370 115.240 ;
        RECT 120.990 115.055 121.315 115.100 ;
        RECT 124.425 115.055 124.715 115.100 ;
        RECT 120.990 115.040 121.310 115.055 ;
        RECT 126.050 115.040 126.370 115.100 ;
        RECT 41.805 114.680 42.095 114.725 ;
        RECT 44.695 114.680 44.985 114.725 ;
        RECT 46.930 114.680 47.250 114.740 ;
        RECT 48.095 114.680 48.385 114.725 ;
        RECT 51.325 114.680 51.615 114.725 ;
        RECT 41.805 114.540 51.615 114.680 ;
        RECT 41.805 114.495 42.095 114.540 ;
        RECT 44.695 114.495 44.985 114.540 ;
        RECT 46.930 114.480 47.250 114.540 ;
        RECT 48.095 114.495 48.385 114.540 ;
        RECT 51.325 114.495 51.615 114.540 ;
        RECT 115.415 114.560 115.705 114.725 ;
        RECT 118.645 114.680 118.935 114.725 ;
        RECT 119.150 114.680 119.470 114.740 ;
        RECT 121.910 114.725 122.230 114.740 ;
        RECT 121.875 114.680 122.230 114.725 ;
        RECT 116.390 114.560 116.710 114.620 ;
        RECT 116.945 114.560 117.235 114.605 ;
        RECT 115.415 114.495 116.140 114.560 ;
        RECT 115.490 114.420 116.140 114.495 ;
        RECT 39.110 114.220 39.430 114.280 ;
        RECT 53.875 114.220 54.165 114.265 ;
        RECT 39.110 114.080 54.165 114.220 ;
        RECT 39.110 114.020 39.430 114.080 ;
        RECT 53.875 114.035 54.165 114.080 ;
        RECT 40.105 113.880 40.395 113.925 ;
        RECT 43.165 113.880 43.455 113.925 ;
        RECT 46.565 113.880 46.855 113.925 ;
        RECT 48.770 113.880 49.090 113.940 ;
        RECT 49.965 113.880 50.255 113.925 ;
        RECT 53.365 113.880 53.655 113.925 ;
        RECT 40.105 113.740 53.655 113.880 ;
        RECT 116.000 113.880 116.140 114.420 ;
        RECT 116.390 114.420 117.235 114.560 ;
        RECT 118.645 114.540 122.230 114.680 ;
        RECT 123.750 114.605 124.070 114.620 ;
        RECT 118.645 114.495 118.935 114.540 ;
        RECT 119.150 114.480 119.470 114.540 ;
        RECT 121.875 114.495 122.230 114.540 ;
        RECT 121.910 114.480 122.230 114.495 ;
        RECT 116.390 114.360 116.710 114.420 ;
        RECT 116.945 114.375 117.235 114.420 ;
        RECT 123.745 114.375 124.070 114.605 ;
        RECT 117.020 114.220 117.160 114.375 ;
        RECT 123.750 114.360 124.070 114.375 ;
        RECT 120.515 114.220 120.805 114.265 ;
        RECT 123.820 114.220 123.960 114.360 ;
        RECT 117.020 114.080 123.960 114.220 ;
        RECT 120.515 114.035 120.805 114.080 ;
        RECT 119.150 113.880 119.470 113.940 ;
        RECT 116.000 113.740 119.470 113.880 ;
        RECT 40.105 113.695 40.395 113.740 ;
        RECT 43.165 113.695 43.455 113.740 ;
        RECT 46.565 113.695 46.855 113.740 ;
        RECT 48.770 113.680 49.090 113.740 ;
        RECT 49.965 113.695 50.255 113.740 ;
        RECT 53.365 113.695 53.655 113.740 ;
        RECT 119.150 113.680 119.470 113.740 ;
        RECT 46.930 113.245 47.250 113.260 ;
        RECT 46.930 113.015 47.365 113.245 ;
        RECT 117.625 113.200 117.915 113.245 ;
        RECT 118.690 113.200 119.010 113.260 ;
        RECT 117.625 113.060 119.010 113.200 ;
        RECT 117.625 113.015 117.915 113.060 ;
        RECT 46.930 113.000 47.250 113.015 ;
        RECT 118.690 113.000 119.010 113.060 ;
        RECT 40.760 112.470 54.200 112.795 ;
        RECT 114.680 112.470 124.760 112.795 ;
        RECT 37.880 111.870 127.160 112.470 ;
        RECT 40.280 111.545 47.000 111.870 ;
        RECT 115.160 111.545 125.240 111.870 ;
        RECT 38.650 110.480 38.970 110.540 ;
        RECT 43.335 110.480 43.625 110.525 ;
        RECT 38.650 110.340 43.625 110.480 ;
        RECT 38.650 110.280 38.970 110.340 ;
        RECT 43.335 110.295 43.625 110.340 ;
        RECT 118.135 110.480 118.425 110.525 ;
        RECT 118.690 110.480 119.010 110.540 ;
        RECT 118.135 110.340 119.010 110.480 ;
        RECT 118.135 110.295 118.425 110.340 ;
        RECT 118.690 110.280 119.010 110.340 ;
        RECT 124.935 110.480 125.225 110.525 ;
        RECT 126.050 110.480 126.370 110.540 ;
        RECT 124.935 110.340 126.370 110.480 ;
        RECT 124.935 110.295 125.225 110.340 ;
        RECT 126.050 110.280 126.370 110.340 ;
        RECT 42.825 110.140 43.115 110.185 ;
        RECT 46.225 110.140 46.515 110.185 ;
        RECT 48.770 110.140 49.090 110.200 ;
        RECT 42.825 110.000 49.090 110.140 ;
        RECT 42.825 109.955 43.115 110.000 ;
        RECT 46.225 109.955 46.515 110.000 ;
        RECT 48.770 109.940 49.090 110.000 ;
        RECT 119.150 109.845 119.470 109.860 ;
        RECT 39.765 109.800 40.055 109.845 ;
        RECT 40.785 109.800 41.075 109.845 ;
        RECT 44.185 109.800 44.475 109.845 ;
        RECT 39.765 109.660 44.475 109.800 ;
        RECT 39.765 109.615 40.055 109.660 ;
        RECT 40.785 109.615 41.075 109.660 ;
        RECT 44.185 109.615 44.475 109.660 ;
        RECT 113.205 109.800 113.495 109.845 ;
        RECT 115.925 109.800 116.215 109.845 ;
        RECT 118.985 109.800 119.470 109.845 ;
        RECT 122.385 109.800 122.675 109.845 ;
        RECT 113.205 109.660 122.675 109.800 ;
        RECT 113.205 109.615 113.495 109.660 ;
        RECT 115.925 109.615 116.215 109.660 ;
        RECT 118.985 109.615 119.470 109.660 ;
        RECT 122.385 109.615 122.675 109.660 ;
        RECT 119.150 109.600 119.470 109.615 ;
        RECT 116.390 109.460 116.710 109.520 ;
        RECT 117.625 109.460 117.915 109.505 ;
        RECT 121.025 109.460 121.315 109.505 ;
        RECT 124.425 109.460 124.715 109.505 ;
        RECT 116.390 109.320 124.715 109.460 ;
        RECT 116.390 109.260 116.710 109.320 ;
        RECT 117.625 109.275 117.915 109.320 ;
        RECT 121.025 109.275 121.315 109.320 ;
        RECT 124.425 109.275 124.715 109.320 ;
        RECT 39.110 109.120 39.430 109.180 ;
        RECT 46.565 109.120 46.855 109.165 ;
        RECT 39.110 108.980 46.855 109.120 ;
        RECT 39.110 108.920 39.430 108.980 ;
        RECT 46.565 108.935 46.855 108.980 ;
        RECT 121.535 109.120 121.825 109.165 ;
        RECT 123.750 109.120 124.070 109.180 ;
        RECT 121.535 108.980 124.070 109.120 ;
        RECT 121.535 108.935 121.825 108.980 ;
        RECT 123.750 108.920 124.070 108.980 ;
        RECT 40.280 108.400 47.000 108.725 ;
        RECT 115.160 108.400 125.240 108.725 ;
        RECT 37.880 107.800 127.160 108.400 ;
        RECT 40.280 107.475 43.640 107.800 ;
        RECT 46.520 107.475 53.240 107.800 ;
        RECT 113.720 107.475 117.080 107.800 ;
        RECT 118.040 107.475 124.760 107.800 ;
        RECT 39.110 107.080 39.430 107.140 ;
        RECT 43.335 107.080 43.625 107.125 ;
        RECT 48.770 107.080 49.090 107.140 ;
        RECT 39.110 106.940 43.625 107.080 ;
        RECT 39.110 106.880 39.430 106.940 ;
        RECT 43.335 106.895 43.625 106.940 ;
        RECT 45.640 106.940 49.090 107.080 ;
        RECT 42.825 106.740 43.115 106.785 ;
        RECT 43.845 106.740 44.135 106.785 ;
        RECT 45.640 106.740 45.780 106.940 ;
        RECT 48.770 106.880 49.090 106.940 ;
        RECT 49.230 107.125 49.550 107.140 ;
        RECT 116.850 107.125 117.170 107.140 ;
        RECT 49.230 106.895 49.745 107.125 ;
        RECT 116.775 106.895 117.170 107.125 ;
        RECT 124.425 107.080 124.715 107.125 ;
        RECT 126.510 107.080 126.830 107.140 ;
        RECT 124.425 106.940 126.830 107.080 ;
        RECT 124.425 106.895 124.715 106.940 ;
        RECT 49.230 106.880 49.550 106.895 ;
        RECT 116.850 106.880 117.170 106.895 ;
        RECT 126.510 106.880 126.830 106.940 ;
        RECT 41.410 106.615 41.730 106.630 ;
        RECT 39.765 106.570 40.055 106.615 ;
        RECT 41.295 106.570 41.730 106.615 ;
        RECT 39.765 106.430 41.730 106.570 ;
        RECT 42.825 106.600 45.780 106.740 ;
        RECT 114.300 106.615 118.860 106.740 ;
        RECT 42.825 106.555 43.115 106.600 ;
        RECT 43.845 106.555 44.135 106.600 ;
        RECT 47.075 106.570 47.365 106.615 ;
        RECT 50.475 106.570 50.765 106.615 ;
        RECT 39.765 106.385 40.055 106.430 ;
        RECT 41.295 106.400 41.730 106.430 ;
        RECT 46.100 106.430 50.765 106.570 ;
        RECT 46.100 106.400 46.240 106.430 ;
        RECT 41.295 106.385 46.240 106.400 ;
        RECT 47.075 106.385 47.365 106.430 ;
        RECT 50.475 106.385 50.765 106.430 ;
        RECT 113.205 106.570 113.495 106.615 ;
        RECT 114.225 106.600 118.935 106.615 ;
        RECT 114.225 106.570 114.515 106.600 ;
        RECT 113.205 106.430 114.515 106.570 ;
        RECT 113.205 106.385 113.495 106.430 ;
        RECT 114.225 106.385 114.515 106.430 ;
        RECT 118.645 106.570 118.935 106.600 ;
        RECT 121.875 106.570 122.165 106.615 ;
        RECT 118.645 106.430 122.165 106.570 ;
        RECT 118.645 106.385 118.935 106.430 ;
        RECT 121.875 106.385 122.165 106.430 ;
        RECT 41.410 106.370 46.240 106.385 ;
        RECT 41.500 106.260 46.240 106.370 ;
        RECT 123.745 106.215 124.035 106.445 ;
        RECT 46.930 106.060 47.250 106.120 ;
        RECT 52.855 106.060 53.145 106.105 ;
        RECT 123.820 106.060 123.960 106.215 ;
        RECT 46.930 105.920 53.145 106.060 ;
        RECT 46.930 105.860 47.250 105.920 ;
        RECT 52.855 105.875 53.145 105.920 ;
        RECT 120.590 105.920 123.960 106.060 ;
        RECT 48.770 105.765 49.090 105.780 ;
        RECT 116.390 105.765 116.710 105.780 ;
        RECT 120.590 105.765 120.730 105.920 ;
        RECT 48.770 105.720 49.235 105.765 ;
        RECT 52.345 105.720 52.635 105.765 ;
        RECT 48.770 105.580 52.635 105.720 ;
        RECT 48.770 105.535 49.235 105.580 ;
        RECT 52.345 105.535 52.635 105.580 ;
        RECT 116.265 105.720 116.710 105.765 ;
        RECT 120.515 105.720 120.805 105.765 ;
        RECT 116.265 105.580 120.805 105.720 ;
        RECT 116.265 105.535 116.710 105.580 ;
        RECT 120.515 105.535 120.805 105.580 ;
        RECT 121.025 105.720 121.315 105.765 ;
        RECT 126.510 105.720 126.830 105.780 ;
        RECT 121.025 105.580 126.830 105.720 ;
        RECT 121.025 105.535 121.315 105.580 ;
        RECT 48.770 105.520 49.090 105.535 ;
        RECT 116.390 105.520 116.710 105.535 ;
        RECT 126.510 105.520 126.830 105.580 ;
        RECT 40.280 104.330 43.640 104.655 ;
        RECT 46.520 104.330 53.240 104.655 ;
        RECT 113.720 104.330 117.080 104.655 ;
        RECT 118.040 104.330 124.760 104.655 ;
        RECT 37.880 103.730 127.160 104.330 ;
        RECT 40.280 103.405 43.640 103.730 ;
        RECT 45.080 103.405 48.440 103.730 ;
        RECT 114.680 103.405 124.760 103.730 ;
        RECT 39.110 103.000 39.430 103.060 ;
        RECT 120.990 103.045 121.310 103.060 ;
        RECT 43.335 103.000 43.625 103.045 ;
        RECT 39.110 102.860 43.625 103.000 ;
        RECT 39.110 102.800 39.430 102.860 ;
        RECT 43.335 102.815 43.625 102.860 ;
        RECT 120.990 103.000 121.315 103.045 ;
        RECT 124.425 103.000 124.715 103.045 ;
        RECT 126.050 103.000 126.370 103.060 ;
        RECT 120.990 102.860 121.505 103.000 ;
        RECT 124.425 102.860 126.370 103.000 ;
        RECT 120.990 102.815 121.315 102.860 ;
        RECT 124.425 102.815 124.715 102.860 ;
        RECT 120.990 102.800 121.310 102.815 ;
        RECT 126.050 102.800 126.370 102.860 ;
        RECT 39.110 101.980 39.430 102.040 ;
        RECT 48.095 101.980 48.385 102.025 ;
        RECT 39.110 101.840 48.385 101.980 ;
        RECT 39.110 101.780 39.430 101.840 ;
        RECT 48.095 101.795 48.385 101.840 ;
        RECT 116.390 101.980 116.710 102.040 ;
        RECT 116.945 101.980 117.235 102.025 ;
        RECT 120.345 101.980 120.635 102.025 ;
        RECT 123.745 101.980 124.035 102.025 ;
        RECT 116.390 101.840 124.035 101.980 ;
        RECT 116.390 101.780 116.710 101.840 ;
        RECT 116.945 101.795 117.235 101.840 ;
        RECT 120.345 101.795 120.635 101.840 ;
        RECT 123.745 101.795 124.035 101.840 ;
        RECT 40.785 101.640 41.075 101.685 ;
        RECT 41.410 101.640 41.730 101.700 ;
        RECT 45.545 101.640 45.835 101.685 ;
        RECT 40.785 101.500 45.835 101.640 ;
        RECT 40.785 101.455 41.075 101.500 ;
        RECT 41.410 101.440 41.730 101.500 ;
        RECT 45.545 101.455 45.835 101.500 ;
        RECT 113.205 101.640 113.495 101.685 ;
        RECT 115.245 101.640 115.535 101.685 ;
        RECT 118.645 101.640 118.935 101.685 ;
        RECT 122.045 101.640 122.335 101.685 ;
        RECT 113.205 101.500 122.335 101.640 ;
        RECT 113.205 101.455 113.495 101.500 ;
        RECT 115.245 101.455 115.535 101.500 ;
        RECT 118.645 101.455 118.935 101.500 ;
        RECT 122.045 101.455 122.335 101.500 ;
        RECT 41.870 101.300 42.190 101.360 ;
        RECT 42.825 101.300 43.115 101.345 ;
        RECT 43.845 101.300 44.135 101.345 ;
        RECT 47.585 101.300 47.875 101.345 ;
        RECT 41.870 101.160 47.875 101.300 ;
        RECT 41.870 101.100 42.190 101.160 ;
        RECT 42.825 101.115 43.115 101.160 ;
        RECT 43.845 101.115 44.135 101.160 ;
        RECT 47.585 101.115 47.875 101.160 ;
        RECT 117.625 100.960 117.915 101.005 ;
        RECT 118.690 100.960 119.010 101.020 ;
        RECT 117.625 100.820 119.010 100.960 ;
        RECT 117.625 100.775 117.915 100.820 ;
        RECT 118.690 100.760 119.010 100.820 ;
        RECT 40.280 100.260 43.640 100.585 ;
        RECT 45.080 100.260 48.440 100.585 ;
        RECT 114.680 100.260 124.760 100.585 ;
        RECT 37.880 99.660 127.160 100.260 ;
        RECT 40.280 99.335 50.360 99.660 ;
        RECT 114.200 99.335 117.560 99.660 ;
        RECT 118.040 99.335 124.760 99.660 ;
        RECT 38.650 98.920 38.970 98.980 ;
        RECT 120.990 98.965 121.310 98.980 ;
        RECT 43.335 98.920 43.625 98.965 ;
        RECT 38.650 98.780 43.625 98.920 ;
        RECT 38.650 98.720 38.970 98.780 ;
        RECT 43.335 98.735 43.625 98.780 ;
        RECT 120.990 98.920 121.315 98.965 ;
        RECT 124.425 98.920 124.715 98.965 ;
        RECT 126.050 98.920 126.370 98.980 ;
        RECT 120.990 98.780 121.505 98.920 ;
        RECT 124.425 98.780 126.370 98.920 ;
        RECT 120.990 98.735 121.315 98.780 ;
        RECT 124.425 98.735 124.715 98.780 ;
        RECT 120.990 98.720 121.310 98.735 ;
        RECT 126.050 98.720 126.370 98.780 ;
        RECT 41.410 98.455 41.730 98.470 ;
        RECT 44.260 98.455 47.160 98.580 ;
        RECT 41.295 98.410 41.730 98.455 ;
        RECT 44.185 98.440 47.160 98.455 ;
        RECT 44.185 98.410 44.475 98.440 ;
        RECT 41.295 98.270 44.475 98.410 ;
        RECT 47.020 98.410 47.160 98.440 ;
        RECT 47.585 98.410 47.875 98.455 ;
        RECT 41.295 98.225 41.730 98.270 ;
        RECT 44.185 98.225 44.475 98.270 ;
        RECT 46.225 98.240 46.515 98.285 ;
        RECT 47.020 98.270 47.875 98.410 ;
        RECT 113.205 98.410 113.495 98.455 ;
        RECT 114.735 98.410 115.025 98.455 ;
        RECT 118.645 98.410 118.935 98.455 ;
        RECT 121.875 98.410 122.165 98.455 ;
        RECT 41.410 98.210 41.730 98.225 ;
        RECT 46.100 98.055 46.515 98.240 ;
        RECT 47.585 98.225 47.875 98.270 ;
        RECT 49.285 98.240 49.575 98.285 ;
        RECT 48.400 98.100 49.575 98.240 ;
        RECT 113.205 98.270 122.165 98.410 ;
        RECT 113.205 98.225 113.495 98.270 ;
        RECT 114.735 98.225 115.025 98.270 ;
        RECT 118.645 98.225 118.935 98.270 ;
        RECT 121.875 98.225 122.165 98.270 ;
        RECT 41.870 97.900 42.190 97.960 ;
        RECT 42.825 97.900 43.115 97.945 ;
        RECT 46.100 97.900 46.240 98.055 ;
        RECT 48.400 97.900 48.540 98.100 ;
        RECT 49.285 98.055 49.575 98.100 ;
        RECT 123.745 98.055 124.035 98.285 ;
        RECT 41.870 97.760 48.540 97.900 ;
        RECT 116.390 97.945 116.710 97.960 ;
        RECT 116.390 97.900 116.895 97.945 ;
        RECT 120.515 97.900 120.805 97.945 ;
        RECT 123.820 97.900 123.960 98.055 ;
        RECT 116.390 97.760 123.960 97.900 ;
        RECT 41.870 97.700 42.190 97.760 ;
        RECT 42.825 97.715 43.115 97.760 ;
        RECT 116.390 97.715 116.895 97.760 ;
        RECT 120.515 97.715 120.805 97.760 ;
        RECT 116.390 97.700 116.710 97.715 ;
        RECT 39.110 97.560 39.430 97.620 ;
        RECT 49.965 97.560 50.255 97.605 ;
        RECT 39.110 97.420 50.255 97.560 ;
        RECT 39.110 97.360 39.430 97.420 ;
        RECT 49.965 97.375 50.255 97.420 ;
        RECT 37.730 97.220 38.050 97.280 ;
        RECT 46.565 97.220 46.855 97.265 ;
        RECT 37.730 97.080 46.855 97.220 ;
        RECT 37.730 97.020 38.050 97.080 ;
        RECT 46.565 97.035 46.855 97.080 ;
        RECT 117.315 96.880 117.545 96.955 ;
        RECT 118.690 96.880 119.010 96.940 ;
        RECT 117.315 96.740 119.010 96.880 ;
        RECT 117.315 96.665 117.545 96.740 ;
        RECT 118.690 96.680 119.010 96.740 ;
        RECT 40.280 96.190 50.360 96.515 ;
        RECT 114.200 96.190 117.560 96.515 ;
        RECT 118.040 96.190 124.760 96.515 ;
        RECT 37.880 95.590 127.160 96.190 ;
        RECT 40.280 95.265 43.640 95.590 ;
        RECT 44.120 95.265 54.200 95.590 ;
        RECT 113.720 95.265 117.080 95.590 ;
        RECT 117.560 95.265 124.280 95.590 ;
        RECT 38.190 94.840 38.510 94.900 ;
        RECT 43.335 94.840 43.625 94.885 ;
        RECT 38.190 94.700 43.625 94.840 ;
        RECT 38.190 94.640 38.510 94.700 ;
        RECT 43.335 94.655 43.625 94.700 ;
        RECT 49.230 94.840 49.550 94.900 ;
        RECT 116.850 94.885 117.170 94.900 ;
        RECT 50.475 94.840 50.765 94.885 ;
        RECT 49.230 94.700 50.765 94.840 ;
        RECT 49.230 94.640 49.550 94.700 ;
        RECT 50.475 94.655 50.765 94.700 ;
        RECT 116.775 94.655 117.170 94.885 ;
        RECT 116.850 94.640 117.170 94.655 ;
        RECT 123.750 94.885 124.070 94.900 ;
        RECT 123.750 94.655 124.205 94.885 ;
        RECT 123.750 94.640 124.070 94.655 ;
        RECT 39.110 94.160 39.430 94.220 ;
        RECT 47.075 94.160 47.365 94.205 ;
        RECT 39.110 94.020 47.365 94.160 ;
        RECT 39.110 93.960 39.430 94.020 ;
        RECT 47.075 93.975 47.365 94.020 ;
        RECT 120.515 94.160 120.805 94.205 ;
        RECT 126.510 94.160 126.830 94.220 ;
        RECT 120.515 94.020 126.830 94.160 ;
        RECT 120.515 93.975 120.805 94.020 ;
        RECT 126.510 93.960 126.830 94.020 ;
        RECT 48.770 93.820 49.090 93.880 ;
        RECT 53.875 93.820 54.165 93.865 ;
        RECT 48.770 93.680 54.165 93.820 ;
        RECT 48.770 93.620 49.090 93.680 ;
        RECT 53.875 93.635 54.165 93.680 ;
        RECT 40.785 93.480 41.075 93.525 ;
        RECT 41.410 93.480 41.730 93.540 ;
        RECT 44.865 93.480 45.155 93.525 ;
        RECT 48.265 93.480 48.555 93.525 ;
        RECT 51.325 93.480 51.615 93.525 ;
        RECT 40.785 93.340 51.615 93.480 ;
        RECT 40.785 93.295 41.075 93.340 ;
        RECT 41.410 93.280 41.730 93.340 ;
        RECT 44.865 93.295 45.155 93.340 ;
        RECT 48.265 93.295 48.555 93.340 ;
        RECT 51.325 93.295 51.615 93.340 ;
        RECT 113.205 93.480 113.495 93.525 ;
        RECT 114.225 93.480 114.515 93.525 ;
        RECT 118.305 93.480 118.595 93.525 ;
        RECT 121.705 93.480 121.995 93.525 ;
        RECT 113.205 93.340 121.995 93.480 ;
        RECT 113.205 93.295 113.495 93.340 ;
        RECT 114.225 93.295 114.515 93.340 ;
        RECT 118.305 93.295 118.595 93.340 ;
        RECT 121.705 93.295 121.995 93.340 ;
        RECT 41.870 93.140 42.190 93.200 ;
        RECT 42.825 93.140 43.115 93.185 ;
        RECT 46.565 93.140 46.855 93.185 ;
        RECT 49.965 93.140 50.255 93.185 ;
        RECT 53.365 93.140 53.655 93.185 ;
        RECT 41.870 93.000 53.655 93.140 ;
        RECT 41.870 92.940 42.190 93.000 ;
        RECT 42.825 92.955 43.115 93.000 ;
        RECT 46.565 92.955 46.855 93.000 ;
        RECT 49.965 92.955 50.255 93.000 ;
        RECT 53.365 92.955 53.655 93.000 ;
        RECT 116.265 93.140 116.555 93.185 ;
        RECT 116.850 93.140 117.170 93.200 ;
        RECT 120.005 93.140 120.295 93.185 ;
        RECT 123.405 93.140 123.695 93.185 ;
        RECT 116.265 93.000 123.695 93.140 ;
        RECT 116.265 92.955 116.555 93.000 ;
        RECT 116.850 92.940 117.170 93.000 ;
        RECT 120.005 92.955 120.295 93.000 ;
        RECT 123.405 92.955 123.695 93.000 ;
        RECT 40.280 92.120 43.640 92.445 ;
        RECT 44.120 92.120 54.200 92.445 ;
        RECT 113.720 92.120 117.080 92.445 ;
        RECT 117.560 92.120 124.280 92.445 ;
        RECT 37.880 91.520 127.160 92.120 ;
        RECT 40.280 91.195 50.360 91.520 ;
        RECT 114.680 91.195 124.760 91.520 ;
        RECT 41.410 90.295 41.730 90.310 ;
        RECT 44.260 90.295 47.160 90.420 ;
        RECT 115.320 90.295 122.090 90.420 ;
        RECT 41.295 90.250 41.730 90.295 ;
        RECT 44.185 90.280 47.160 90.295 ;
        RECT 44.185 90.250 44.475 90.280 ;
        RECT 41.295 90.110 44.475 90.250 ;
        RECT 47.020 90.250 47.160 90.280 ;
        RECT 47.585 90.250 47.875 90.295 ;
        RECT 41.295 90.065 41.730 90.110 ;
        RECT 44.185 90.065 44.475 90.110 ;
        RECT 46.225 90.080 46.515 90.125 ;
        RECT 47.020 90.110 47.875 90.250 ;
        RECT 115.245 90.280 122.165 90.295 ;
        RECT 41.410 90.050 41.730 90.065 ;
        RECT 46.100 89.895 46.515 90.080 ;
        RECT 47.585 90.065 47.875 90.110 ;
        RECT 49.285 90.080 49.575 90.125 ;
        RECT 48.400 89.940 49.575 90.080 ;
        RECT 41.870 89.740 42.190 89.800 ;
        RECT 42.825 89.740 43.115 89.785 ;
        RECT 46.100 89.740 46.240 89.895 ;
        RECT 48.400 89.740 48.540 89.940 ;
        RECT 49.285 89.895 49.575 89.940 ;
        RECT 111.790 90.080 112.110 90.140 ;
        RECT 113.205 90.080 113.495 90.125 ;
        RECT 115.245 90.080 115.535 90.280 ;
        RECT 111.790 90.065 115.535 90.080 ;
        RECT 116.850 90.125 117.170 90.140 ;
        RECT 111.790 89.940 115.460 90.065 ;
        RECT 111.790 89.880 112.110 89.940 ;
        RECT 113.205 89.895 113.495 89.940 ;
        RECT 116.850 89.895 117.235 90.125 ;
        RECT 118.645 90.065 118.935 90.280 ;
        RECT 121.875 90.065 122.165 90.280 ;
        RECT 123.745 89.895 124.035 90.125 ;
        RECT 116.850 89.880 117.170 89.895 ;
        RECT 41.870 89.600 48.540 89.740 ;
        RECT 117.020 89.740 117.160 89.880 ;
        RECT 120.515 89.740 120.805 89.785 ;
        RECT 123.820 89.740 123.960 89.895 ;
        RECT 117.020 89.600 123.960 89.740 ;
        RECT 41.870 89.540 42.190 89.600 ;
        RECT 42.825 89.555 43.115 89.600 ;
        RECT 120.515 89.555 120.805 89.600 ;
        RECT 39.110 89.060 39.430 89.120 ;
        RECT 120.990 89.105 121.310 89.120 ;
        RECT 46.565 89.060 46.855 89.105 ;
        RECT 39.110 88.920 46.855 89.060 ;
        RECT 39.110 88.860 39.430 88.920 ;
        RECT 46.565 88.875 46.855 88.920 ;
        RECT 120.990 89.060 121.315 89.105 ;
        RECT 124.425 89.060 124.715 89.105 ;
        RECT 126.050 89.060 126.370 89.120 ;
        RECT 120.990 88.920 121.505 89.060 ;
        RECT 124.425 88.920 126.370 89.060 ;
        RECT 120.990 88.875 121.315 88.920 ;
        RECT 124.425 88.875 124.715 88.920 ;
        RECT 120.990 88.860 121.310 88.875 ;
        RECT 126.050 88.860 126.370 88.920 ;
        RECT 37.730 88.720 38.050 88.780 ;
        RECT 43.335 88.720 43.625 88.765 ;
        RECT 37.730 88.580 43.625 88.720 ;
        RECT 37.730 88.520 38.050 88.580 ;
        RECT 43.335 88.535 43.625 88.580 ;
        RECT 48.770 88.720 49.090 88.780 ;
        RECT 49.965 88.720 50.255 88.765 ;
        RECT 48.770 88.580 50.255 88.720 ;
        RECT 48.770 88.520 49.090 88.580 ;
        RECT 49.965 88.535 50.255 88.580 ;
        RECT 117.625 88.720 117.915 88.765 ;
        RECT 118.690 88.720 119.010 88.780 ;
        RECT 117.625 88.580 119.010 88.720 ;
        RECT 117.625 88.535 117.915 88.580 ;
        RECT 118.690 88.520 119.010 88.580 ;
        RECT 40.280 88.050 50.360 88.375 ;
        RECT 114.680 88.050 124.760 88.375 ;
        RECT 37.880 87.450 127.160 88.050 ;
        RECT 40.280 87.125 43.640 87.450 ;
        RECT 46.040 87.125 49.400 87.450 ;
        RECT 110.840 87.125 124.280 87.450 ;
        RECT 49.145 86.740 49.375 86.755 ;
        RECT 38.650 86.680 38.970 86.740 ;
        RECT 43.335 86.680 43.625 86.725 ;
        RECT 38.650 86.540 43.625 86.680 ;
        RECT 38.650 86.480 38.970 86.540 ;
        RECT 43.335 86.495 43.625 86.540 ;
        RECT 49.145 86.480 49.550 86.740 ;
        RECT 120.515 86.680 120.805 86.725 ;
        RECT 120.990 86.680 121.310 86.740 ;
        RECT 120.515 86.540 121.310 86.680 ;
        RECT 120.515 86.495 120.805 86.540 ;
        RECT 120.990 86.480 121.310 86.540 ;
        RECT 123.750 86.725 124.070 86.740 ;
        RECT 123.750 86.495 124.205 86.725 ;
        RECT 123.750 86.480 124.070 86.495 ;
        RECT 49.145 86.465 49.375 86.480 ;
        RECT 116.850 86.045 117.170 86.060 ;
        RECT 113.375 86.000 113.665 86.045 ;
        RECT 116.605 86.000 117.170 86.045 ;
        RECT 119.150 86.000 119.470 86.060 ;
        RECT 120.005 86.000 120.295 86.045 ;
        RECT 113.375 85.860 122.090 86.000 ;
        RECT 113.375 85.815 113.665 85.860 ;
        RECT 116.605 85.815 117.170 85.860 ;
        RECT 116.850 85.800 117.170 85.815 ;
        RECT 119.150 85.800 119.470 85.860 ;
        RECT 120.005 85.815 120.295 85.860 ;
        RECT 121.950 85.660 122.090 85.860 ;
        RECT 121.950 85.520 123.620 85.660 ;
        RECT 41.410 85.420 41.730 85.435 ;
        RECT 46.930 85.420 47.250 85.435 ;
        RECT 41.295 85.190 41.730 85.420 ;
        RECT 41.410 85.175 41.730 85.190 ;
        RECT 41.870 85.320 42.190 85.380 ;
        RECT 46.905 85.375 47.250 85.420 ;
        RECT 111.790 85.420 112.110 85.435 ;
        RECT 42.825 85.320 43.115 85.365 ;
        RECT 41.870 85.180 43.115 85.320 ;
        RECT 46.735 85.235 47.250 85.375 ;
        RECT 48.770 85.365 49.090 85.380 ;
        RECT 46.905 85.190 47.250 85.235 ;
        RECT 41.870 85.120 42.190 85.180 ;
        RECT 42.825 85.135 43.115 85.180 ;
        RECT 46.930 85.175 47.250 85.190 ;
        RECT 48.605 85.135 49.090 85.365 ;
        RECT 111.790 85.375 112.135 85.420 ;
        RECT 111.790 85.320 112.305 85.375 ;
        RECT 114.735 85.320 115.025 85.420 ;
        RECT 111.790 85.190 115.025 85.320 ;
        RECT 118.135 85.375 118.425 85.420 ;
        RECT 120.990 85.375 121.310 85.435 ;
        RECT 121.535 85.375 121.825 85.420 ;
        RECT 118.135 85.235 121.825 85.375 ;
        RECT 123.480 85.365 123.620 85.520 ;
        RECT 118.135 85.190 118.425 85.235 ;
        RECT 111.790 85.180 114.950 85.190 ;
        RECT 111.790 85.175 112.110 85.180 ;
        RECT 120.990 85.175 121.310 85.235 ;
        RECT 121.535 85.190 121.825 85.235 ;
        RECT 123.405 85.135 123.695 85.365 ;
        RECT 48.770 85.120 49.090 85.135 ;
        RECT 114.090 85.025 114.410 85.040 ;
        RECT 113.885 84.795 114.410 85.025 ;
        RECT 114.090 84.780 114.410 84.795 ;
        RECT 117.315 84.980 117.545 85.055 ;
        RECT 118.690 84.980 119.010 85.040 ;
        RECT 117.315 84.840 119.010 84.980 ;
        RECT 117.315 84.765 117.545 84.840 ;
        RECT 118.690 84.780 119.010 84.840 ;
        RECT 40.280 83.980 43.640 84.305 ;
        RECT 46.040 83.980 49.400 84.305 ;
        RECT 110.840 83.980 124.280 84.305 ;
        RECT 37.880 83.380 127.160 83.980 ;
        RECT 40.280 83.055 57.080 83.380 ;
        RECT 71.525 82.850 71.850 83.200 ;
        RECT 112.760 83.055 119.480 83.380 ;
        RECT 121.400 83.055 124.760 83.380 ;
        RECT 46.930 82.260 47.250 82.320 ;
        RECT 71.575 82.260 71.800 82.850 ;
        RECT 111.790 82.600 112.110 82.660 ;
        RECT 113.630 82.600 113.950 82.660 ;
        RECT 82.925 82.460 116.820 82.600 ;
        RECT 82.925 82.260 83.065 82.460 ;
        RECT 111.790 82.400 112.110 82.460 ;
        RECT 113.630 82.400 113.950 82.460 ;
        RECT 41.410 82.135 41.730 82.150 ;
        RECT 41.295 82.090 41.730 82.135 ;
        RECT 43.710 82.090 44.030 82.150 ;
        RECT 44.695 82.090 44.985 82.135 ;
        RECT 45.640 82.120 83.065 82.260 ;
        RECT 113.720 82.135 113.860 82.400 ;
        RECT 116.680 82.260 116.820 82.460 ;
        RECT 120.990 82.260 121.310 82.320 ;
        RECT 116.680 82.135 121.310 82.260 ;
        RECT 45.640 82.090 45.780 82.120 ;
        RECT 41.295 81.950 45.780 82.090 ;
        RECT 46.930 82.060 47.250 82.120 ;
        RECT 41.295 81.905 41.730 81.950 ;
        RECT 41.410 81.890 41.730 81.905 ;
        RECT 43.710 81.890 44.030 81.950 ;
        RECT 44.695 81.905 44.985 81.950 ;
        RECT 46.225 81.920 46.515 81.965 ;
        RECT 46.100 81.735 46.515 81.920 ;
        RECT 47.925 81.905 48.215 82.120 ;
        RECT 48.770 81.920 49.090 81.980 ;
        RECT 49.285 81.920 49.575 81.965 ;
        RECT 48.400 81.780 49.575 81.920 ;
        RECT 51.155 81.905 51.445 82.120 ;
        RECT 52.685 81.920 52.975 81.965 ;
        RECT 54.380 81.950 54.675 82.120 ;
        RECT 41.870 81.580 42.190 81.640 ;
        RECT 42.825 81.580 43.115 81.625 ;
        RECT 46.100 81.580 46.240 81.735 ;
        RECT 48.400 81.580 48.540 81.780 ;
        RECT 48.770 81.720 49.090 81.780 ;
        RECT 49.285 81.735 49.575 81.780 ;
        RECT 51.620 81.780 52.975 81.920 ;
        RECT 54.385 81.905 54.675 81.950 ;
        RECT 56.085 81.920 56.375 81.965 ;
        RECT 57.445 81.920 57.735 81.965 ;
        RECT 51.620 81.580 51.760 81.780 ;
        RECT 52.685 81.735 52.975 81.780 ;
        RECT 56.085 81.780 57.735 81.920 ;
        RECT 113.545 81.950 113.860 82.135 ;
        RECT 116.605 82.120 121.310 82.135 ;
        RECT 113.545 81.905 113.835 81.950 ;
        RECT 116.605 81.905 116.895 82.120 ;
        RECT 120.990 82.090 121.310 82.120 ;
        RECT 122.385 82.090 122.675 82.135 ;
        RECT 120.990 82.060 122.675 82.090 ;
        RECT 119.150 81.920 119.470 81.980 ;
        RECT 121.100 81.950 122.675 82.060 ;
        RECT 123.750 81.965 124.070 81.980 ;
        RECT 56.085 81.735 56.375 81.780 ;
        RECT 57.445 81.735 57.735 81.780 ;
        RECT 118.720 81.780 119.470 81.920 ;
        RECT 122.385 81.905 122.675 81.950 ;
        RECT 123.745 81.920 124.070 81.965 ;
        RECT 123.555 81.780 124.070 81.920 ;
        RECT 41.870 81.440 51.760 81.580 ;
        RECT 114.090 81.580 114.410 81.640 ;
        RECT 118.720 81.625 118.860 81.780 ;
        RECT 119.150 81.720 119.470 81.780 ;
        RECT 123.745 81.735 124.070 81.780 ;
        RECT 123.750 81.720 124.070 81.735 ;
        RECT 115.245 81.580 115.535 81.625 ;
        RECT 118.645 81.580 118.935 81.625 ;
        RECT 114.090 81.440 118.935 81.580 ;
        RECT 41.870 81.380 42.190 81.440 ;
        RECT 42.825 81.395 43.115 81.440 ;
        RECT 114.090 81.380 114.410 81.440 ;
        RECT 115.245 81.395 115.535 81.440 ;
        RECT 118.645 81.395 118.935 81.440 ;
        RECT 39.110 81.240 39.430 81.300 ;
        RECT 46.565 81.240 46.855 81.285 ;
        RECT 39.110 81.100 46.855 81.240 ;
        RECT 39.110 81.040 39.430 81.100 ;
        RECT 46.565 81.055 46.855 81.100 ;
        RECT 54.290 81.240 54.610 81.300 ;
        RECT 56.765 81.240 57.055 81.285 ;
        RECT 54.290 81.100 57.055 81.240 ;
        RECT 54.290 81.040 54.610 81.100 ;
        RECT 56.765 81.055 57.055 81.100 ;
        RECT 119.155 81.240 119.445 81.285 ;
        RECT 129.270 81.240 129.590 81.300 ;
        RECT 119.155 81.100 129.590 81.240 ;
        RECT 119.155 81.055 119.445 81.100 ;
        RECT 129.270 81.040 129.590 81.100 ;
        RECT 38.650 80.900 38.970 80.960 ;
        RECT 43.335 80.900 43.625 80.945 ;
        RECT 38.650 80.760 43.625 80.900 ;
        RECT 38.650 80.700 38.970 80.760 ;
        RECT 43.335 80.715 43.625 80.760 ;
        RECT 48.770 80.900 49.090 80.960 ;
        RECT 49.965 80.900 50.255 80.945 ;
        RECT 48.770 80.760 50.255 80.900 ;
        RECT 48.770 80.700 49.090 80.760 ;
        RECT 49.965 80.715 50.255 80.760 ;
        RECT 115.755 80.900 116.045 80.945 ;
        RECT 126.050 80.900 126.370 80.960 ;
        RECT 115.755 80.760 126.370 80.900 ;
        RECT 115.755 80.715 116.045 80.760 ;
        RECT 126.050 80.700 126.370 80.760 ;
        RECT 38.190 80.560 38.510 80.620 ;
        RECT 53.365 80.560 53.655 80.605 ;
        RECT 38.190 80.420 53.655 80.560 ;
        RECT 38.190 80.360 38.510 80.420 ;
        RECT 53.365 80.375 53.655 80.420 ;
        RECT 124.425 80.560 124.715 80.605 ;
        RECT 128.350 80.560 128.670 80.620 ;
        RECT 124.425 80.420 128.670 80.560 ;
        RECT 124.425 80.375 124.715 80.420 ;
        RECT 128.350 80.360 128.670 80.420 ;
        RECT 40.280 79.910 57.080 80.235 ;
        RECT 112.760 79.910 119.480 80.235 ;
        RECT 121.400 79.910 124.760 80.235 ;
        RECT 37.880 79.310 127.160 79.910 ;
        RECT 39.320 78.985 56.120 79.310 ;
        RECT 113.720 78.985 127.160 79.310 ;
        RECT 39.110 78.520 39.430 78.580 ;
        RECT 45.715 78.520 46.005 78.565 ;
        RECT 39.110 78.380 46.005 78.520 ;
        RECT 39.110 78.320 39.430 78.380 ;
        RECT 45.715 78.335 46.005 78.380 ;
        RECT 54.290 78.520 54.610 78.580 ;
        RECT 116.850 78.565 117.170 78.580 ;
        RECT 55.745 78.520 56.035 78.565 ;
        RECT 54.290 78.380 56.035 78.520 ;
        RECT 54.290 78.320 54.610 78.380 ;
        RECT 55.745 78.335 56.035 78.380 ;
        RECT 116.775 78.335 117.170 78.565 ;
        RECT 116.850 78.320 117.170 78.335 ;
        RECT 41.870 77.885 42.190 77.900 ;
        RECT 41.805 77.840 42.190 77.885 ;
        RECT 48.605 77.840 48.895 77.885 ;
        RECT 114.090 77.840 114.410 77.900 ;
        RECT 116.265 77.840 116.555 77.885 ;
        RECT 123.750 77.840 124.070 77.900 ;
        RECT 41.805 77.700 54.060 77.840 ;
        RECT 41.805 77.655 42.190 77.700 ;
        RECT 41.870 77.640 42.190 77.655 ;
        RECT 45.205 77.500 45.495 77.545 ;
        RECT 45.640 77.500 45.780 77.700 ;
        RECT 48.605 77.655 48.895 77.700 ;
        RECT 52.080 77.545 52.220 77.700 ;
        RECT 41.500 77.360 43.480 77.500 ;
        RECT 40.275 77.235 40.565 77.280 ;
        RECT 41.500 77.235 41.640 77.360 ;
        RECT 40.275 77.095 41.640 77.235 ;
        RECT 43.340 77.235 43.480 77.360 ;
        RECT 45.205 77.360 45.780 77.500 ;
        RECT 45.205 77.315 45.495 77.360 ;
        RECT 52.005 77.315 52.295 77.545 ;
        RECT 53.920 77.500 54.060 77.700 ;
        RECT 68.525 77.700 126.340 77.840 ;
        RECT 55.065 77.500 55.355 77.545 ;
        RECT 57.445 77.500 57.735 77.545 ;
        RECT 68.525 77.500 68.665 77.700 ;
        RECT 53.920 77.360 68.665 77.500 ;
        RECT 55.065 77.315 55.355 77.360 ;
        RECT 57.445 77.315 57.735 77.360 ;
        RECT 43.710 77.280 44.030 77.295 ;
        RECT 43.675 77.235 44.030 77.280 ;
        RECT 46.565 77.235 46.855 77.280 ;
        RECT 49.965 77.235 50.255 77.280 ;
        RECT 53.365 77.235 53.655 77.280 ;
        RECT 43.340 77.160 44.030 77.235 ;
        RECT 46.560 77.160 51.760 77.235 ;
        RECT 52.540 77.160 53.655 77.235 ;
        RECT 43.340 77.095 53.655 77.160 ;
        RECT 40.275 77.050 40.565 77.095 ;
        RECT 43.675 77.050 46.855 77.095 ;
        RECT 49.965 77.050 50.255 77.095 ;
        RECT 43.710 77.035 46.700 77.050 ;
        RECT 43.800 77.020 46.700 77.035 ;
        RECT 51.620 77.020 52.680 77.095 ;
        RECT 53.365 77.050 53.655 77.095 ;
        RECT 40.950 76.820 41.270 76.880 ;
        RECT 42.315 76.820 42.605 76.865 ;
        RECT 40.950 76.680 42.605 76.820 ;
        RECT 40.950 76.620 41.270 76.680 ;
        RECT 42.315 76.635 42.605 76.680 ;
        RECT 46.930 76.820 47.250 76.880 ;
        RECT 49.145 76.820 49.375 76.895 ;
        RECT 46.930 76.680 49.375 76.820 ;
        RECT 46.930 76.620 47.250 76.680 ;
        RECT 49.145 76.605 49.375 76.680 ;
        RECT 51.070 76.820 51.390 76.880 ;
        RECT 52.345 76.820 52.635 76.865 ;
        RECT 51.070 76.680 52.635 76.820 ;
        RECT 51.070 76.620 51.390 76.680 ;
        RECT 52.345 76.635 52.635 76.680 ;
        RECT 39.320 75.840 56.120 76.165 ;
        RECT 62.430 75.840 63.330 77.360 ;
        RECT 67.430 75.840 68.330 77.360 ;
        RECT 72.430 75.840 73.330 77.700 ;
        RECT 77.430 75.840 78.330 77.700 ;
        RECT 82.430 75.840 83.330 77.700 ;
        RECT 87.430 75.840 88.330 77.700 ;
        RECT 92.430 75.840 93.330 77.700 ;
        RECT 97.430 75.840 98.330 77.700 ;
        RECT 102.430 75.840 103.330 77.700 ;
        RECT 107.430 75.840 108.330 77.700 ;
        RECT 114.090 77.640 114.410 77.700 ;
        RECT 116.265 77.655 116.555 77.700 ;
        RECT 119.240 77.545 119.380 77.700 ;
        RECT 122.800 77.545 122.940 77.700 ;
        RECT 123.750 77.640 124.070 77.700 ;
        RECT 126.200 77.545 126.340 77.700 ;
        RECT 119.240 77.360 119.615 77.545 ;
        RECT 119.325 77.315 119.615 77.360 ;
        RECT 122.725 77.315 123.015 77.545 ;
        RECT 126.125 77.315 126.415 77.545 ;
        RECT 126.805 77.500 127.095 77.545 ;
        RECT 129.730 77.500 130.050 77.560 ;
        RECT 126.805 77.360 130.050 77.500 ;
        RECT 126.805 77.315 127.095 77.360 ;
        RECT 129.730 77.300 130.050 77.360 ;
        RECT 113.630 77.235 113.950 77.295 ;
        RECT 114.225 77.235 114.515 77.280 ;
        RECT 117.625 77.235 117.915 77.280 ;
        RECT 113.630 77.160 117.915 77.235 ;
        RECT 121.025 77.160 121.315 77.280 ;
        RECT 124.255 77.160 124.545 77.280 ;
        RECT 113.630 77.095 124.545 77.160 ;
        RECT 113.630 77.035 113.950 77.095 ;
        RECT 114.225 77.050 114.515 77.095 ;
        RECT 117.625 77.050 124.545 77.095 ;
        RECT 117.700 77.020 124.470 77.050 ;
        RECT 120.005 76.820 120.295 76.865 ;
        RECT 121.910 76.820 122.230 76.880 ;
        RECT 120.005 76.680 122.230 76.820 ;
        RECT 120.005 76.635 120.295 76.680 ;
        RECT 121.910 76.620 122.230 76.680 ;
        RECT 123.405 76.820 123.695 76.865 ;
        RECT 127.890 76.820 128.210 76.880 ;
        RECT 123.405 76.680 128.210 76.820 ;
        RECT 123.405 76.635 123.695 76.680 ;
        RECT 127.890 76.620 128.210 76.680 ;
        RECT 113.720 75.840 127.160 76.165 ;
        RECT 37.880 75.240 127.160 75.840 ;
      LAYER met2 ;
        RECT 34.990 166.835 35.270 167.205 ;
        RECT 35.060 158.850 35.200 166.835 ;
        RECT 38.670 165.475 38.950 165.845 ;
        RECT 38.740 160.210 38.880 165.475 ;
        RECT 38.680 159.890 38.940 160.210 ;
        RECT 38.220 159.210 38.480 159.530 ;
        RECT 37.760 159.045 38.020 159.190 ;
        RECT 35.000 158.530 35.260 158.850 ;
        RECT 37.750 158.675 38.030 159.045 ;
        RECT 38.280 156.325 38.420 159.210 ;
        RECT 38.210 155.955 38.490 156.325 ;
        RECT 38.740 155.790 38.880 159.890 ;
        RECT 39.130 157.315 39.410 157.685 ;
        RECT 39.200 156.130 39.340 157.315 ;
        RECT 39.140 155.810 39.400 156.130 ;
        RECT 38.680 155.470 38.940 155.790 ;
        RECT 39.130 154.595 39.410 154.965 ;
        RECT 39.200 154.430 39.340 154.595 ;
        RECT 39.140 154.110 39.400 154.430 ;
        RECT 36.380 153.770 36.640 154.090 ;
        RECT 36.440 153.605 36.580 153.770 ;
        RECT 36.370 153.235 36.650 153.605 ;
        RECT 39.140 151.050 39.400 151.370 ;
        RECT 38.220 149.690 38.480 150.010 ;
        RECT 38.280 146.805 38.420 149.690 ;
        RECT 39.200 149.525 39.340 151.050 ;
        RECT 39.130 149.155 39.410 149.525 ;
        RECT 38.670 147.795 38.950 148.165 ;
        RECT 38.210 146.435 38.490 146.805 ;
        RECT 38.740 146.610 38.880 147.795 ;
        RECT 38.680 146.290 38.940 146.610 ;
        RECT 39.140 145.950 39.400 146.270 ;
        RECT 38.220 145.610 38.480 145.930 ;
        RECT 38.280 144.085 38.420 145.610 ;
        RECT 39.200 145.445 39.340 145.950 ;
        RECT 39.130 145.075 39.410 145.445 ;
        RECT 38.210 143.715 38.490 144.085 ;
        RECT 39.140 142.890 39.400 143.210 ;
        RECT 35.000 141.530 35.260 141.850 ;
        RECT 35.060 137.285 35.200 141.530 ;
        RECT 39.200 141.365 39.340 142.890 ;
        RECT 39.130 140.995 39.410 141.365 ;
        RECT 39.130 139.635 39.410 140.005 ;
        RECT 39.200 138.790 39.340 139.635 ;
        RECT 39.140 138.470 39.400 138.790 ;
        RECT 37.300 137.450 37.560 137.770 ;
        RECT 34.990 136.915 35.270 137.285 ;
        RECT 37.360 135.925 37.500 137.450 ;
        RECT 37.290 135.555 37.570 135.925 ;
        RECT 36.840 134.565 37.100 134.710 ;
        RECT 36.830 134.195 37.110 134.565 ;
        RECT 38.680 133.370 38.940 133.690 ;
        RECT 38.740 131.845 38.880 133.370 ;
        RECT 38.670 131.475 38.950 131.845 ;
        RECT 39.130 130.115 39.410 130.485 ;
        RECT 39.200 129.950 39.340 130.115 ;
        RECT 39.140 129.630 39.400 129.950 ;
        RECT 38.220 129.290 38.480 129.610 ;
        RECT 38.280 129.125 38.420 129.290 ;
        RECT 38.210 128.755 38.490 129.125 ;
        RECT 39.130 127.395 39.410 127.765 ;
        RECT 39.140 127.250 39.400 127.395 ;
        RECT 39.140 126.405 39.400 126.550 ;
        RECT 39.130 126.035 39.410 126.405 ;
        RECT 39.140 125.210 39.400 125.530 ;
        RECT 39.200 125.045 39.340 125.210 ;
        RECT 39.130 124.675 39.410 125.045 ;
        RECT 39.130 123.315 39.410 123.685 ;
        RECT 39.140 123.170 39.400 123.315 ;
        RECT 39.130 121.955 39.410 122.325 ;
        RECT 39.200 121.790 39.340 121.955 ;
        RECT 39.140 121.470 39.400 121.790 ;
        RECT 38.670 120.595 38.950 120.965 ;
        RECT 38.210 117.875 38.490 118.245 ;
        RECT 38.280 115.330 38.420 117.875 ;
        RECT 38.740 117.370 38.880 120.595 ;
        RECT 39.130 119.235 39.410 119.605 ;
        RECT 39.200 117.710 39.340 119.235 ;
        RECT 39.140 117.390 39.400 117.710 ;
        RECT 38.680 117.050 38.940 117.370 ;
        RECT 38.220 115.010 38.480 115.330 ;
        RECT 39.140 114.165 39.400 114.310 ;
        RECT 39.130 113.795 39.410 114.165 ;
        RECT 38.670 111.075 38.950 111.445 ;
        RECT 38.740 110.570 38.880 111.075 ;
        RECT 38.680 110.250 38.940 110.570 ;
        RECT 39.130 109.715 39.410 110.085 ;
        RECT 39.200 109.210 39.340 109.715 ;
        RECT 39.140 108.890 39.400 109.210 ;
        RECT 39.130 108.355 39.410 108.725 ;
        RECT 39.200 107.170 39.340 108.355 ;
        RECT 39.140 106.850 39.400 107.170 ;
        RECT 39.130 104.275 39.410 104.645 ;
        RECT 38.670 102.915 38.950 103.285 ;
        RECT 39.200 103.090 39.340 104.275 ;
        RECT 37.750 101.555 38.030 101.925 ;
        RECT 37.820 97.310 37.960 101.555 ;
        RECT 38.210 98.835 38.490 99.205 ;
        RECT 38.740 99.010 38.880 102.915 ;
        RECT 39.140 102.770 39.400 103.090 ;
        RECT 39.140 101.750 39.400 102.070 ;
        RECT 39.200 100.565 39.340 101.750 ;
        RECT 39.130 100.195 39.410 100.565 ;
        RECT 37.760 96.990 38.020 97.310 ;
        RECT 37.750 96.115 38.030 96.485 ;
        RECT 37.820 88.810 37.960 96.115 ;
        RECT 38.280 94.930 38.420 98.835 ;
        RECT 38.680 98.690 38.940 99.010 ;
        RECT 39.130 97.475 39.410 97.845 ;
        RECT 39.140 97.330 39.400 97.475 ;
        RECT 38.220 94.610 38.480 94.930 ;
        RECT 39.140 93.930 39.400 94.250 ;
        RECT 39.200 92.405 39.340 93.930 ;
        RECT 39.130 92.035 39.410 92.405 ;
        RECT 39.130 90.675 39.410 91.045 ;
        RECT 38.670 89.315 38.950 89.685 ;
        RECT 37.760 88.490 38.020 88.810 ;
        RECT 38.740 86.770 38.880 89.315 ;
        RECT 39.200 89.150 39.340 90.675 ;
        RECT 39.140 88.830 39.400 89.150 ;
        RECT 38.680 86.450 38.940 86.770 ;
        RECT 38.670 85.235 38.950 85.605 ;
        RECT 38.210 82.515 38.490 82.885 ;
        RECT 38.280 80.650 38.420 82.515 ;
        RECT 38.740 80.990 38.880 85.235 ;
        RECT 39.130 83.875 39.410 84.245 ;
        RECT 39.200 81.330 39.340 83.875 ;
        RECT 39.140 81.010 39.400 81.330 ;
        RECT 38.680 80.670 38.940 80.990 ;
        RECT 38.220 80.330 38.480 80.650 ;
        RECT 39.140 78.290 39.400 78.610 ;
        RECT 39.200 77.445 39.340 78.290 ;
        RECT 39.130 77.075 39.410 77.445 ;
        RECT 39.930 66.940 40.830 169.610 ;
        RECT 41.900 158.405 42.160 158.725 ;
        RECT 41.440 157.850 41.700 158.170 ;
        RECT 41.500 154.770 41.640 157.850 ;
        RECT 41.960 155.450 42.100 158.405 ;
        RECT 41.900 155.130 42.160 155.450 ;
        RECT 41.440 154.450 41.700 154.770 ;
        RECT 41.500 151.030 41.640 154.450 ;
        RECT 41.440 150.710 41.700 151.030 ;
        RECT 41.500 147.630 41.640 150.710 ;
        RECT 41.440 147.310 41.700 147.630 ;
        RECT 41.500 142.870 41.640 147.310 ;
        RECT 41.440 142.550 41.700 142.870 ;
        RECT 41.500 139.810 41.640 142.550 ;
        RECT 41.900 142.125 42.160 142.445 ;
        RECT 41.440 139.490 41.700 139.810 ;
        RECT 41.960 139.190 42.100 142.125 ;
        RECT 41.900 138.870 42.160 139.190 ;
        RECT 41.960 134.305 42.100 138.870 ;
        RECT 41.900 133.985 42.160 134.305 ;
        RECT 41.960 131.050 42.100 133.985 ;
        RECT 41.900 130.730 42.160 131.050 ;
        RECT 41.440 106.340 41.700 106.660 ;
        RECT 41.500 101.730 41.640 106.340 ;
        RECT 41.440 101.410 41.700 101.730 ;
        RECT 41.500 98.500 41.640 101.410 ;
        RECT 41.900 101.070 42.160 101.390 ;
        RECT 41.440 98.180 41.700 98.500 ;
        RECT 41.500 93.570 41.640 98.180 ;
        RECT 41.960 97.990 42.100 101.070 ;
        RECT 41.900 97.670 42.160 97.990 ;
        RECT 41.440 93.250 41.700 93.570 ;
        RECT 41.500 90.340 41.640 93.250 ;
        RECT 41.960 93.230 42.100 97.670 ;
        RECT 41.900 92.910 42.160 93.230 ;
        RECT 41.440 90.020 41.700 90.340 ;
        RECT 41.500 85.465 41.640 90.020 ;
        RECT 41.960 89.830 42.100 92.910 ;
        RECT 41.900 89.510 42.160 89.830 ;
        RECT 41.440 85.145 41.700 85.465 ;
        RECT 41.960 85.410 42.100 89.510 ;
        RECT 41.500 82.180 41.640 85.145 ;
        RECT 41.900 85.090 42.160 85.410 ;
        RECT 41.440 81.860 41.700 82.180 ;
        RECT 41.960 81.670 42.100 85.090 ;
        RECT 41.900 81.350 42.160 81.670 ;
        RECT 41.960 77.930 42.100 81.350 ;
        RECT 41.900 77.610 42.160 77.930 ;
        RECT 40.980 76.590 41.240 76.910 ;
        RECT 41.040 74.725 41.180 76.590 ;
        RECT 40.970 74.355 41.250 74.725 ;
        RECT 42.430 63.740 43.330 172.810 ;
        RECT 44.200 138.470 44.460 138.790 ;
        RECT 44.260 135.730 44.400 138.470 ;
        RECT 44.200 135.410 44.460 135.730 ;
        RECT 44.260 134.370 44.400 135.410 ;
        RECT 44.200 134.050 44.460 134.370 ;
        RECT 44.260 130.630 44.400 134.050 ;
        RECT 44.200 130.310 44.460 130.630 ;
        RECT 43.740 81.860 44.000 82.180 ;
        RECT 43.800 77.325 43.940 81.860 ;
        RECT 43.740 77.005 44.000 77.325 ;
        RECT 44.930 66.940 45.830 169.610 ;
        RECT 46.950 138.275 47.230 138.645 ;
        RECT 47.020 138.110 47.160 138.275 ;
        RECT 46.960 137.790 47.220 138.110 ;
        RECT 46.960 133.370 47.220 133.690 ;
        RECT 47.020 133.205 47.160 133.370 ;
        RECT 46.950 132.835 47.230 133.205 ;
        RECT 46.960 130.310 47.220 130.630 ;
        RECT 46.500 125.610 46.760 125.870 ;
        RECT 47.020 125.610 47.160 130.310 ;
        RECT 46.500 125.550 47.160 125.610 ;
        RECT 46.560 125.470 47.160 125.550 ;
        RECT 47.020 122.810 47.160 125.470 ;
        RECT 46.960 122.490 47.220 122.810 ;
        RECT 47.020 119.070 47.160 122.490 ;
        RECT 46.960 118.750 47.220 119.070 ;
        RECT 46.960 118.070 47.220 118.390 ;
        RECT 47.020 114.770 47.160 118.070 ;
        RECT 46.960 114.450 47.220 114.770 ;
        RECT 46.960 112.970 47.220 113.290 ;
        RECT 47.020 112.805 47.160 112.970 ;
        RECT 46.950 112.435 47.230 112.805 ;
        RECT 46.960 106.005 47.220 106.150 ;
        RECT 46.950 105.635 47.230 106.005 ;
        RECT 46.960 85.145 47.220 85.465 ;
        RECT 47.020 82.350 47.160 85.145 ;
        RECT 46.960 82.030 47.220 82.350 ;
        RECT 46.960 76.590 47.220 76.910 ;
        RECT 47.020 76.085 47.160 76.590 ;
        RECT 46.950 75.715 47.230 76.085 ;
        RECT 47.430 63.740 48.330 172.810 ;
        RECT 48.790 161.395 49.070 161.765 ;
        RECT 48.860 158.850 49.000 161.395 ;
        RECT 48.800 158.530 49.060 158.850 ;
        RECT 48.790 150.515 49.070 150.885 ;
        RECT 48.800 150.370 49.060 150.515 ;
        RECT 48.800 117.050 49.060 117.370 ;
        RECT 48.860 116.885 49.000 117.050 ;
        RECT 48.790 116.515 49.070 116.885 ;
        RECT 49.250 115.155 49.530 115.525 ;
        RECT 49.260 115.010 49.520 115.155 ;
        RECT 48.800 113.650 49.060 113.970 ;
        RECT 48.860 110.230 49.000 113.650 ;
        RECT 48.800 109.910 49.060 110.230 ;
        RECT 48.860 107.170 49.000 109.910 ;
        RECT 48.800 106.850 49.060 107.170 ;
        RECT 49.250 106.995 49.530 107.365 ;
        RECT 49.260 106.850 49.520 106.995 ;
        RECT 48.860 105.810 49.000 106.850 ;
        RECT 48.800 105.490 49.060 105.810 ;
        RECT 49.250 94.755 49.530 95.125 ;
        RECT 49.260 94.610 49.520 94.755 ;
        RECT 48.800 93.765 49.060 93.910 ;
        RECT 48.790 93.395 49.070 93.765 ;
        RECT 48.800 88.490 49.060 88.810 ;
        RECT 48.860 88.325 49.000 88.490 ;
        RECT 48.790 87.955 49.070 88.325 ;
        RECT 49.250 86.595 49.530 86.965 ;
        RECT 49.260 86.450 49.520 86.595 ;
        RECT 48.800 85.090 49.060 85.410 ;
        RECT 48.860 82.010 49.000 85.090 ;
        RECT 48.800 81.690 49.060 82.010 ;
        RECT 48.800 80.670 49.060 80.990 ;
        RECT 48.860 80.165 49.000 80.670 ;
        RECT 48.790 79.795 49.070 80.165 ;
        RECT 49.930 66.940 50.830 169.610 ;
        RECT 52.020 158.870 52.280 159.190 ;
        RECT 52.080 155.790 52.220 158.870 ;
        RECT 52.020 155.470 52.280 155.790 ;
        RECT 52.010 151.875 52.290 152.245 ;
        RECT 52.020 151.730 52.280 151.875 ;
        RECT 52.010 142.355 52.290 142.725 ;
        RECT 52.020 142.210 52.280 142.355 ;
        RECT 51.100 76.590 51.360 76.910 ;
        RECT 51.160 73.365 51.300 76.590 ;
        RECT 51.090 72.995 51.370 73.365 ;
        RECT 52.430 63.740 53.330 172.810 ;
        RECT 54.310 160.035 54.590 160.405 ;
        RECT 54.380 158.850 54.520 160.035 ;
        RECT 54.320 158.530 54.580 158.850 ;
        RECT 53.860 155.470 54.120 155.790 ;
        RECT 53.920 147.290 54.060 155.470 ;
        RECT 53.860 146.970 54.120 147.290 ;
        RECT 54.310 81.155 54.590 81.525 ;
        RECT 54.320 81.010 54.580 81.155 ;
        RECT 54.310 78.435 54.590 78.805 ;
        RECT 54.320 78.290 54.580 78.435 ;
        RECT 54.930 66.940 55.830 169.610 ;
        RECT 57.430 63.740 58.330 172.810 ;
        RECT 58.920 146.970 59.180 147.290 ;
        RECT 58.980 145.930 59.120 146.970 ;
        RECT 58.920 145.610 59.180 145.930 ;
        RECT 58.980 142.530 59.120 145.610 ;
        RECT 58.920 142.210 59.180 142.530 ;
        RECT 59.930 66.940 60.830 169.610 ;
        RECT 61.680 155.130 61.940 155.450 ;
        RECT 61.740 152.050 61.880 155.130 ;
        RECT 61.680 151.730 61.940 152.050 ;
        RECT 62.430 63.740 63.330 172.810 ;
        RECT 63.980 157.850 64.240 158.170 ;
        RECT 64.040 155.790 64.180 157.850 ;
        RECT 63.980 155.470 64.240 155.790 ;
        RECT 64.440 150.370 64.700 150.690 ;
        RECT 64.500 147.970 64.640 150.370 ;
        RECT 64.440 147.650 64.700 147.970 ;
        RECT 64.930 66.940 65.830 169.610 ;
        RECT 66.740 153.770 67.000 154.090 ;
        RECT 66.800 150.690 66.940 153.770 ;
        RECT 66.740 150.370 67.000 150.690 ;
        RECT 66.740 141.530 67.000 141.850 ;
        RECT 66.800 139.130 66.940 141.530 ;
        RECT 66.740 138.810 67.000 139.130 ;
        RECT 67.430 63.740 68.330 172.810 ;
        RECT 69.040 150.370 69.300 150.690 ;
        RECT 69.100 147.290 69.240 150.370 ;
        RECT 69.040 146.970 69.300 147.290 ;
        RECT 69.930 66.940 70.830 169.610 ;
        RECT 71.125 139.220 71.820 139.650 ;
        RECT 71.550 83.150 71.820 139.220 ;
        RECT 71.450 82.825 71.925 83.150 ;
        RECT 72.430 63.740 73.330 172.810 ;
        RECT 74.100 139.490 74.360 139.810 ;
        RECT 74.160 134.370 74.300 139.490 ;
        RECT 74.100 134.050 74.360 134.370 ;
        RECT 74.930 66.940 75.830 169.610 ;
        RECT 76.400 150.370 76.660 150.690 ;
        RECT 76.460 143.890 76.600 150.370 ;
        RECT 76.400 143.570 76.660 143.890 ;
        RECT 76.460 142.530 76.600 143.570 ;
        RECT 76.400 142.210 76.660 142.530 ;
        RECT 76.460 139.810 76.600 142.210 ;
        RECT 76.400 139.490 76.660 139.810 ;
        RECT 77.430 63.740 78.330 172.810 ;
        RECT 79.930 66.940 80.830 169.610 ;
        RECT 82.430 63.740 83.330 172.810 ;
        RECT 84.930 66.940 85.830 169.610 ;
        RECT 87.430 63.740 88.330 172.810 ;
        RECT 89.930 66.940 90.830 169.610 ;
        RECT 92.430 63.740 93.330 172.810 ;
        RECT 94.930 66.940 95.830 169.610 ;
        RECT 97.430 63.740 98.330 172.810 ;
        RECT 99.930 66.940 100.830 169.610 ;
        RECT 102.430 63.740 103.330 172.810 ;
        RECT 104.930 66.940 105.830 169.610 ;
        RECT 107.430 63.740 108.330 172.810 ;
        RECT 109.930 66.940 110.830 169.610 ;
        RECT 111.820 89.850 112.080 90.170 ;
        RECT 111.880 85.465 112.020 89.850 ;
        RECT 111.820 85.145 112.080 85.465 ;
        RECT 111.880 82.690 112.020 85.145 ;
        RECT 111.820 82.370 112.080 82.690 ;
        RECT 112.430 63.740 113.330 172.810 ;
        RECT 114.120 155.130 114.380 155.450 ;
        RECT 114.180 151.030 114.320 155.130 ;
        RECT 114.120 150.710 114.380 151.030 ;
        RECT 114.120 84.750 114.380 85.070 ;
        RECT 114.180 84.245 114.320 84.750 ;
        RECT 114.110 83.875 114.390 84.245 ;
        RECT 113.660 82.370 113.920 82.690 ;
        RECT 113.720 77.325 113.860 82.370 ;
        RECT 114.120 81.350 114.380 81.670 ;
        RECT 114.180 77.930 114.320 81.350 ;
        RECT 114.120 77.610 114.380 77.930 ;
        RECT 113.660 77.005 113.920 77.325 ;
        RECT 114.930 66.940 115.830 169.610 ;
        RECT 116.880 158.870 117.140 159.190 ;
        RECT 116.420 157.850 116.680 158.170 ;
        RECT 116.480 155.790 116.620 157.850 ;
        RECT 116.420 155.470 116.680 155.790 ;
        RECT 116.940 155.450 117.080 158.870 ;
        RECT 116.880 155.130 117.140 155.450 ;
        RECT 116.410 151.875 116.690 152.245 ;
        RECT 116.420 151.730 116.680 151.875 ;
        RECT 116.940 150.690 117.080 155.130 ;
        RECT 116.880 150.370 117.140 150.690 ;
        RECT 116.940 150.010 117.080 150.370 ;
        RECT 116.880 149.690 117.140 150.010 ;
        RECT 116.940 146.950 117.080 149.690 ;
        RECT 116.880 146.630 117.140 146.950 ;
        RECT 116.410 135.555 116.690 135.925 ;
        RECT 116.420 135.410 116.680 135.555 ;
        RECT 116.880 125.890 117.140 126.210 ;
        RECT 116.940 122.910 117.080 125.890 ;
        RECT 116.880 122.590 117.140 122.910 ;
        RECT 116.420 121.810 116.680 122.130 ;
        RECT 116.480 118.050 116.620 121.810 ;
        RECT 116.940 118.730 117.080 122.590 ;
        RECT 116.880 118.410 117.140 118.730 ;
        RECT 116.420 117.730 116.680 118.050 ;
        RECT 116.480 114.650 116.620 117.730 ;
        RECT 116.420 114.330 116.680 114.650 ;
        RECT 116.480 109.550 116.620 114.330 ;
        RECT 116.420 109.230 116.680 109.550 ;
        RECT 116.480 105.810 116.620 109.230 ;
        RECT 116.870 106.995 117.150 107.365 ;
        RECT 116.880 106.850 117.140 106.995 ;
        RECT 116.420 105.490 116.680 105.810 ;
        RECT 116.480 102.070 116.620 105.490 ;
        RECT 116.420 101.750 116.680 102.070 ;
        RECT 116.480 97.990 116.620 101.750 ;
        RECT 116.420 97.670 116.680 97.990 ;
        RECT 116.480 93.140 116.620 97.670 ;
        RECT 116.870 94.755 117.150 95.125 ;
        RECT 116.880 94.610 117.140 94.755 ;
        RECT 116.880 93.140 117.140 93.230 ;
        RECT 116.480 93.000 117.140 93.140 ;
        RECT 116.880 92.910 117.140 93.000 ;
        RECT 116.940 90.170 117.080 92.910 ;
        RECT 116.880 89.850 117.140 90.170 ;
        RECT 116.940 86.090 117.080 89.850 ;
        RECT 116.880 85.770 117.140 86.090 ;
        RECT 116.870 78.435 117.150 78.805 ;
        RECT 116.880 78.290 117.140 78.435 ;
        RECT 117.430 63.740 118.330 172.810 ;
        RECT 118.720 157.850 118.980 158.170 ;
        RECT 118.780 157.685 118.920 157.850 ;
        RECT 118.710 157.315 118.990 157.685 ;
        RECT 118.710 155.955 118.990 156.325 ;
        RECT 118.720 155.810 118.980 155.955 ;
        RECT 118.720 149.690 118.980 150.010 ;
        RECT 119.180 149.690 119.440 150.010 ;
        RECT 118.780 149.525 118.920 149.690 ;
        RECT 118.710 149.155 118.990 149.525 ;
        RECT 119.240 147.290 119.380 149.690 ;
        RECT 119.180 146.970 119.440 147.290 ;
        RECT 119.240 142.445 119.380 146.970 ;
        RECT 119.180 142.125 119.440 142.445 ;
        RECT 119.180 141.530 119.440 141.850 ;
        RECT 119.240 138.790 119.380 141.530 ;
        RECT 119.180 138.470 119.440 138.790 ;
        RECT 119.240 134.710 119.380 138.470 ;
        RECT 119.180 134.390 119.440 134.710 ;
        RECT 118.720 133.370 118.980 133.690 ;
        RECT 118.780 133.205 118.920 133.370 ;
        RECT 118.710 132.835 118.990 133.205 ;
        RECT 119.240 130.970 119.380 134.390 ;
        RECT 119.180 130.650 119.440 130.970 ;
        RECT 118.710 121.955 118.990 122.325 ;
        RECT 118.720 121.810 118.980 121.955 ;
        RECT 119.170 119.235 119.450 119.605 ;
        RECT 119.240 117.370 119.380 119.235 ;
        RECT 119.180 117.050 119.440 117.370 ;
        RECT 119.180 114.450 119.440 114.770 ;
        RECT 119.240 113.970 119.380 114.450 ;
        RECT 119.180 113.650 119.440 113.970 ;
        RECT 118.720 112.970 118.980 113.290 ;
        RECT 118.780 112.805 118.920 112.970 ;
        RECT 118.710 112.435 118.990 112.805 ;
        RECT 118.720 110.250 118.980 110.570 ;
        RECT 118.780 110.085 118.920 110.250 ;
        RECT 118.710 109.715 118.990 110.085 ;
        RECT 119.240 109.890 119.380 113.650 ;
        RECT 119.180 109.570 119.440 109.890 ;
        RECT 118.720 100.730 118.980 101.050 ;
        RECT 118.780 100.565 118.920 100.730 ;
        RECT 118.710 100.195 118.990 100.565 ;
        RECT 118.720 96.650 118.980 96.970 ;
        RECT 118.780 96.485 118.920 96.650 ;
        RECT 118.710 96.115 118.990 96.485 ;
        RECT 118.720 88.490 118.980 88.810 ;
        RECT 118.780 88.325 118.920 88.490 ;
        RECT 118.710 87.955 118.990 88.325 ;
        RECT 119.180 85.770 119.440 86.090 ;
        RECT 118.710 85.235 118.990 85.605 ;
        RECT 118.780 85.070 118.920 85.235 ;
        RECT 118.720 84.750 118.980 85.070 ;
        RECT 119.240 82.010 119.380 85.770 ;
        RECT 119.180 81.690 119.440 82.010 ;
        RECT 119.930 66.940 120.830 169.610 ;
        RECT 121.010 147.795 121.290 148.165 ;
        RECT 121.080 146.610 121.220 147.795 ;
        RECT 121.020 146.290 121.280 146.610 ;
        RECT 121.480 142.125 121.740 142.445 ;
        RECT 121.540 141.930 121.680 142.125 ;
        RECT 121.540 141.790 122.140 141.930 ;
        RECT 122.000 139.190 122.140 141.790 ;
        RECT 121.940 138.870 122.200 139.190 ;
        RECT 122.000 134.305 122.140 138.870 ;
        RECT 121.940 133.985 122.200 134.305 ;
        RECT 122.000 131.050 122.140 133.985 ;
        RECT 121.940 130.730 122.200 131.050 ;
        RECT 122.000 126.210 122.140 130.730 ;
        RECT 121.940 125.890 122.200 126.210 ;
        RECT 121.940 117.730 122.200 118.050 ;
        RECT 121.010 115.155 121.290 115.525 ;
        RECT 121.020 115.010 121.280 115.155 ;
        RECT 122.000 114.770 122.140 117.730 ;
        RECT 121.940 114.450 122.200 114.770 ;
        RECT 121.010 102.915 121.290 103.285 ;
        RECT 121.020 102.770 121.280 102.915 ;
        RECT 121.010 98.835 121.290 99.205 ;
        RECT 121.020 98.690 121.280 98.835 ;
        RECT 121.010 90.675 121.290 91.045 ;
        RECT 121.080 89.150 121.220 90.675 ;
        RECT 121.020 88.830 121.280 89.150 ;
        RECT 121.010 86.595 121.290 86.965 ;
        RECT 121.020 86.450 121.280 86.595 ;
        RECT 121.020 85.145 121.280 85.465 ;
        RECT 121.080 82.350 121.220 85.145 ;
        RECT 121.020 82.030 121.280 82.350 ;
        RECT 121.940 76.590 122.200 76.910 ;
        RECT 122.000 76.085 122.140 76.590 ;
        RECT 121.930 75.715 122.210 76.085 ;
        RECT 122.430 63.740 123.330 172.810 ;
        RECT 123.770 160.035 124.050 160.405 ;
        RECT 123.780 159.890 124.040 160.035 ;
        RECT 123.780 150.370 124.040 150.690 ;
        RECT 123.840 147.290 123.980 150.370 ;
        RECT 123.780 146.970 124.040 147.290 ;
        RECT 123.840 142.610 123.980 146.970 ;
        RECT 123.840 142.530 124.440 142.610 ;
        RECT 123.840 142.470 124.500 142.530 ;
        RECT 123.840 138.790 123.980 142.470 ;
        RECT 124.240 142.210 124.500 142.470 ;
        RECT 124.240 141.530 124.500 141.850 ;
        RECT 124.300 141.365 124.440 141.530 ;
        RECT 124.230 140.995 124.510 141.365 ;
        RECT 123.780 138.470 124.040 138.790 ;
        RECT 123.780 134.050 124.040 134.370 ;
        RECT 123.840 130.970 123.980 134.050 ;
        RECT 123.780 130.650 124.040 130.970 ;
        RECT 123.840 126.890 123.980 130.650 ;
        RECT 123.780 126.570 124.040 126.890 ;
        RECT 123.840 126.210 123.980 126.570 ;
        RECT 123.780 125.890 124.040 126.210 ;
        RECT 123.840 122.470 123.980 125.890 ;
        RECT 123.780 122.150 124.040 122.470 ;
        RECT 123.840 118.050 123.980 122.150 ;
        RECT 124.240 121.130 124.500 121.450 ;
        RECT 124.300 120.965 124.440 121.130 ;
        RECT 124.230 120.595 124.510 120.965 ;
        RECT 123.780 117.730 124.040 118.050 ;
        RECT 123.840 114.650 123.980 117.730 ;
        RECT 123.780 114.330 124.040 114.650 ;
        RECT 123.780 108.890 124.040 109.210 ;
        RECT 123.840 108.725 123.980 108.890 ;
        RECT 123.770 108.355 124.050 108.725 ;
        RECT 123.770 97.475 124.050 97.845 ;
        RECT 123.840 94.930 123.980 97.475 ;
        RECT 123.780 94.610 124.040 94.930 ;
        RECT 123.770 89.315 124.050 89.685 ;
        RECT 123.840 86.770 123.980 89.315 ;
        RECT 123.780 86.450 124.040 86.770 ;
        RECT 123.780 81.690 124.040 82.010 ;
        RECT 123.840 77.930 123.980 81.690 ;
        RECT 123.780 77.610 124.040 77.930 ;
        RECT 124.930 66.940 125.830 169.610 ;
        RECT 128.830 158.675 129.110 159.045 ;
        RECT 128.840 158.530 129.100 158.675 ;
        RECT 126.530 154.595 126.810 154.965 ;
        RECT 126.540 154.450 126.800 154.595 ;
        RECT 128.380 153.770 128.640 154.090 ;
        RECT 128.440 153.605 128.580 153.770 ;
        RECT 128.370 153.235 128.650 153.605 ;
        RECT 126.540 150.885 126.800 151.030 ;
        RECT 126.530 150.515 126.810 150.885 ;
        RECT 128.380 149.690 128.640 150.010 ;
        RECT 128.440 146.805 128.580 149.690 ;
        RECT 128.370 146.435 128.650 146.805 ;
        RECT 126.080 145.610 126.340 145.930 ;
        RECT 129.760 145.610 130.020 145.930 ;
        RECT 126.140 144.085 126.280 145.610 ;
        RECT 129.820 145.445 129.960 145.610 ;
        RECT 129.750 145.075 130.030 145.445 ;
        RECT 126.070 143.715 126.350 144.085 ;
        RECT 126.080 142.725 126.340 142.870 ;
        RECT 126.070 142.355 126.350 142.725 ;
        RECT 129.300 141.530 129.560 141.850 ;
        RECT 129.360 140.005 129.500 141.530 ;
        RECT 129.290 139.635 129.570 140.005 ;
        RECT 126.530 138.275 126.810 138.645 ;
        RECT 126.540 138.130 126.800 138.275 ;
        RECT 128.380 137.450 128.640 137.770 ;
        RECT 128.440 137.285 128.580 137.450 ;
        RECT 128.370 136.915 128.650 137.285 ;
        RECT 126.540 134.565 126.800 134.710 ;
        RECT 126.530 134.195 126.810 134.565 ;
        RECT 128.380 133.370 128.640 133.690 ;
        RECT 128.440 131.845 128.580 133.370 ;
        RECT 128.370 131.475 128.650 131.845 ;
        RECT 126.530 130.115 126.810 130.485 ;
        RECT 126.540 129.970 126.800 130.115 ;
        RECT 128.380 129.290 128.640 129.610 ;
        RECT 128.440 129.125 128.580 129.290 ;
        RECT 128.370 128.755 128.650 129.125 ;
        RECT 126.070 127.395 126.350 127.765 ;
        RECT 126.080 127.250 126.340 127.395 ;
        RECT 126.540 126.405 126.800 126.550 ;
        RECT 126.530 126.035 126.810 126.405 ;
        RECT 126.070 124.675 126.350 125.045 ;
        RECT 126.140 123.490 126.280 124.675 ;
        RECT 126.080 123.170 126.340 123.490 ;
        RECT 126.990 123.315 127.270 123.685 ;
        RECT 126.530 117.875 126.810 118.245 ;
        RECT 126.600 117.710 126.740 117.875 ;
        RECT 126.540 117.390 126.800 117.710 ;
        RECT 127.060 117.370 127.200 123.315 ;
        RECT 127.000 117.050 127.260 117.370 ;
        RECT 126.070 116.515 126.350 116.885 ;
        RECT 126.140 115.330 126.280 116.515 ;
        RECT 126.080 115.010 126.340 115.330 ;
        RECT 126.070 113.795 126.350 114.165 ;
        RECT 126.140 110.570 126.280 113.795 ;
        RECT 126.530 111.075 126.810 111.445 ;
        RECT 126.080 110.250 126.340 110.570 ;
        RECT 126.600 107.170 126.740 111.075 ;
        RECT 126.540 106.850 126.800 107.170 ;
        RECT 126.530 105.635 126.810 106.005 ;
        RECT 126.540 105.490 126.800 105.635 ;
        RECT 126.070 104.275 126.350 104.645 ;
        RECT 126.140 103.090 126.280 104.275 ;
        RECT 126.080 102.770 126.340 103.090 ;
        RECT 126.070 101.555 126.350 101.925 ;
        RECT 126.140 99.010 126.280 101.555 ;
        RECT 126.080 98.690 126.340 99.010 ;
        RECT 126.540 93.930 126.800 94.250 ;
        RECT 126.600 93.765 126.740 93.930 ;
        RECT 126.530 93.395 126.810 93.765 ;
        RECT 126.070 92.035 126.350 92.405 ;
        RECT 126.140 89.150 126.280 92.035 ;
        RECT 126.080 88.830 126.340 89.150 ;
        RECT 126.070 82.515 126.350 82.885 ;
        RECT 126.140 80.990 126.280 82.515 ;
        RECT 129.290 81.155 129.570 81.525 ;
        RECT 129.300 81.010 129.560 81.155 ;
        RECT 126.080 80.670 126.340 80.990 ;
        RECT 128.380 80.330 128.640 80.650 ;
        RECT 128.440 80.165 128.580 80.330 ;
        RECT 128.370 79.795 128.650 80.165 ;
        RECT 129.760 77.445 130.020 77.590 ;
        RECT 129.750 77.075 130.030 77.445 ;
        RECT 127.920 76.590 128.180 76.910 ;
        RECT 127.980 74.725 128.120 76.590 ;
        RECT 127.910 74.355 128.190 74.725 ;
      LAYER met3 ;
        RECT 7.000 169.610 9.000 206.600 ;
        RECT 26.080 171.210 138.960 172.810 ;
        RECT 6.960 168.010 135.760 169.610 ;
        RECT 7.000 154.700 9.000 168.010 ;
        RECT 20.000 167.170 20.700 167.400 ;
        RECT 34.965 167.170 35.295 167.185 ;
        RECT 20.000 166.870 35.295 167.170 ;
        RECT 20.000 166.700 20.700 166.870 ;
        RECT 34.965 166.855 35.295 166.870 ;
        RECT 38.645 165.810 38.975 165.825 ;
        RECT 22.750 165.510 38.975 165.810 ;
        RECT 22.750 164.800 23.050 165.510 ;
        RECT 38.645 165.495 38.975 165.510 ;
        RECT 22.490 164.000 23.400 164.800 ;
        RECT 48.765 161.730 49.095 161.745 ;
        RECT 16.340 161.430 49.095 161.730 ;
        RECT 16.340 160.400 16.640 161.430 ;
        RECT 48.765 161.415 49.095 161.430 ;
        RECT 16.100 159.700 16.900 160.400 ;
        RECT 54.285 160.370 54.615 160.385 ;
        RECT 32.600 160.070 54.615 160.370 ;
        RECT 32.600 159.395 33.600 160.070 ;
        RECT 54.285 160.055 54.615 160.070 ;
        RECT 123.745 160.370 124.075 160.385 ;
        RECT 128.600 160.370 132.600 161.395 ;
        RECT 123.745 160.070 132.600 160.370 ;
        RECT 123.745 160.055 124.075 160.070 ;
        RECT 32.600 159.010 36.600 159.395 ;
        RECT 37.725 159.010 38.055 159.025 ;
        RECT 32.600 158.710 38.055 159.010 ;
        RECT 32.600 157.650 36.600 158.710 ;
        RECT 37.725 158.695 38.055 158.710 ;
        RECT 39.105 157.650 39.435 157.665 ;
        RECT 118.685 157.650 119.015 157.665 ;
        RECT 128.600 157.650 132.600 160.070 ;
        RECT 32.600 157.200 132.600 157.650 ;
        RECT 32.600 156.290 36.600 157.200 ;
        RECT 38.185 156.290 38.515 156.305 ;
        RECT 32.600 155.990 38.515 156.290 ;
        RECT 32.600 155.150 36.600 155.990 ;
        RECT 38.185 155.975 38.515 155.990 ;
        RECT 118.685 156.290 119.015 156.305 ;
        RECT 128.600 156.290 132.600 157.200 ;
        RECT 118.685 155.990 132.600 156.290 ;
        RECT 118.685 155.975 119.015 155.990 ;
        RECT 128.600 155.150 132.600 155.990 ;
        RECT 32.600 154.350 132.600 155.150 ;
        RECT 32.600 153.585 36.600 154.350 ;
        RECT 128.600 153.585 132.600 154.350 ;
        RECT 32.600 153.255 36.675 153.585 ;
        RECT 128.345 153.255 132.600 153.585 ;
        RECT 32.600 152.210 36.600 153.255 ;
        RECT 51.985 152.210 52.315 152.225 ;
        RECT 32.600 151.910 52.315 152.210 ;
        RECT 32.600 150.850 36.600 151.910 ;
        RECT 51.985 151.895 52.315 151.910 ;
        RECT 116.385 152.210 116.715 152.225 ;
        RECT 128.600 152.210 132.600 153.255 ;
        RECT 116.385 151.910 132.600 152.210 ;
        RECT 116.385 151.895 116.715 151.910 ;
        RECT 48.765 150.850 49.095 150.865 ;
        RECT 32.600 150.550 49.095 150.850 ;
        RECT 32.600 149.600 36.600 150.550 ;
        RECT 48.765 150.535 49.095 150.550 ;
        RECT 126.505 150.850 126.835 150.865 ;
        RECT 128.600 150.850 132.600 151.910 ;
        RECT 126.505 150.550 132.600 150.850 ;
        RECT 126.505 150.535 126.835 150.550 ;
        RECT 128.600 149.600 132.600 150.550 ;
        RECT 32.600 149.100 132.600 149.600 ;
        RECT 32.600 148.130 36.600 149.100 ;
        RECT 38.645 148.130 38.975 148.145 ;
        RECT 32.600 147.830 38.975 148.130 ;
        RECT 32.600 146.770 36.600 147.830 ;
        RECT 38.645 147.815 38.975 147.830 ;
        RECT 120.985 148.130 121.315 148.145 ;
        RECT 128.600 148.130 132.600 149.100 ;
        RECT 120.985 147.830 132.600 148.130 ;
        RECT 120.985 147.815 121.315 147.830 ;
        RECT 128.600 146.785 132.600 147.830 ;
        RECT 38.185 146.770 38.515 146.785 ;
        RECT 32.600 146.470 38.515 146.770 ;
        RECT 32.600 145.500 36.600 146.470 ;
        RECT 38.185 146.455 38.515 146.470 ;
        RECT 128.345 146.455 132.600 146.785 ;
        RECT 128.600 145.500 132.600 146.455 ;
        RECT 32.600 144.950 132.600 145.500 ;
        RECT 32.600 144.050 36.600 144.950 ;
        RECT 38.185 144.050 38.515 144.065 ;
        RECT 32.600 143.750 38.515 144.050 ;
        RECT 32.600 142.690 36.600 143.750 ;
        RECT 38.185 143.735 38.515 143.750 ;
        RECT 126.045 144.050 126.375 144.065 ;
        RECT 128.600 144.050 132.600 144.950 ;
        RECT 126.045 143.750 132.600 144.050 ;
        RECT 126.045 143.735 126.375 143.750 ;
        RECT 51.985 142.690 52.315 142.705 ;
        RECT 32.600 142.390 52.315 142.690 ;
        RECT 32.600 141.330 36.600 142.390 ;
        RECT 51.985 142.375 52.315 142.390 ;
        RECT 126.045 142.690 126.375 142.705 ;
        RECT 128.600 142.690 132.600 143.750 ;
        RECT 126.045 142.390 132.600 142.690 ;
        RECT 126.045 142.375 126.375 142.390 ;
        RECT 39.105 141.330 39.435 141.345 ;
        RECT 32.600 141.030 39.435 141.330 ;
        RECT 32.600 139.970 36.600 141.030 ;
        RECT 39.105 141.015 39.435 141.030 ;
        RECT 124.205 141.330 124.535 141.345 ;
        RECT 128.600 141.330 132.600 142.390 ;
        RECT 124.205 141.030 132.600 141.330 ;
        RECT 124.205 141.015 124.535 141.030 ;
        RECT 39.105 139.970 39.435 139.985 ;
        RECT 32.600 139.670 39.435 139.970 ;
        RECT 32.600 138.700 36.600 139.670 ;
        RECT 39.105 139.655 39.435 139.670 ;
        RECT 128.600 138.700 132.600 141.030 ;
        RECT 32.600 137.800 132.600 138.700 ;
        RECT 32.600 135.890 36.600 137.800 ;
        RECT 128.600 137.265 132.600 137.800 ;
        RECT 128.345 136.935 132.600 137.265 ;
        RECT 37.265 135.890 37.595 135.905 ;
        RECT 32.600 135.590 37.595 135.890 ;
        RECT 32.600 134.900 36.600 135.590 ;
        RECT 37.265 135.575 37.595 135.590 ;
        RECT 116.385 135.890 116.715 135.905 ;
        RECT 128.600 135.890 132.600 136.935 ;
        RECT 116.385 135.590 132.600 135.890 ;
        RECT 116.385 135.575 116.715 135.590 ;
        RECT 32.600 134.000 37.200 134.900 ;
        RECT 126.505 134.530 126.835 134.545 ;
        RECT 128.600 134.530 132.600 135.590 ;
        RECT 126.505 134.230 132.600 134.530 ;
        RECT 126.505 134.215 126.835 134.230 ;
        RECT 32.600 133.170 36.600 134.000 ;
        RECT 46.925 133.170 47.255 133.185 ;
        RECT 32.600 132.870 47.255 133.170 ;
        RECT 32.600 131.900 36.600 132.870 ;
        RECT 46.925 132.855 47.255 132.870 ;
        RECT 118.685 133.170 119.015 133.185 ;
        RECT 128.600 133.170 132.600 134.230 ;
        RECT 118.685 132.870 132.600 133.170 ;
        RECT 118.685 132.855 119.015 132.870 ;
        RECT 128.600 131.900 132.600 132.870 ;
        RECT 32.600 131.200 132.600 131.900 ;
        RECT 32.600 130.450 36.600 131.200 ;
        RECT 39.105 130.450 39.435 130.465 ;
        RECT 32.600 130.150 39.435 130.450 ;
        RECT 4.000 65.340 6.000 129.420 ;
        RECT 32.600 129.090 36.600 130.150 ;
        RECT 39.105 130.135 39.435 130.150 ;
        RECT 126.505 130.450 126.835 130.465 ;
        RECT 128.600 130.450 132.600 131.200 ;
        RECT 126.505 130.150 132.600 130.450 ;
        RECT 126.505 130.135 126.835 130.150 ;
        RECT 128.600 129.105 132.600 130.150 ;
        RECT 38.185 129.090 38.515 129.105 ;
        RECT 32.600 128.790 38.515 129.090 ;
        RECT 32.600 127.730 36.600 128.790 ;
        RECT 38.185 128.775 38.515 128.790 ;
        RECT 128.345 128.775 132.600 129.105 ;
        RECT 39.105 127.730 39.435 127.745 ;
        RECT 32.600 127.430 39.435 127.730 ;
        RECT 32.600 126.450 36.600 127.430 ;
        RECT 39.105 127.415 39.435 127.430 ;
        RECT 126.045 127.730 126.375 127.745 ;
        RECT 128.600 127.730 132.600 128.775 ;
        RECT 126.045 127.430 132.600 127.730 ;
        RECT 126.045 127.415 126.375 127.430 ;
        RECT 128.600 126.450 132.600 127.430 ;
        RECT 32.600 125.800 132.600 126.450 ;
        RECT 32.600 125.010 36.600 125.800 ;
        RECT 39.105 125.010 39.435 125.025 ;
        RECT 32.600 124.710 39.435 125.010 ;
        RECT 32.600 123.650 36.600 124.710 ;
        RECT 39.105 124.695 39.435 124.710 ;
        RECT 126.045 125.010 126.375 125.025 ;
        RECT 128.600 125.010 132.600 125.800 ;
        RECT 126.045 124.710 132.600 125.010 ;
        RECT 126.045 124.695 126.375 124.710 ;
        RECT 39.105 123.650 39.435 123.665 ;
        RECT 32.600 123.350 39.435 123.650 ;
        RECT 32.600 122.290 36.600 123.350 ;
        RECT 39.105 123.335 39.435 123.350 ;
        RECT 126.965 123.650 127.295 123.665 ;
        RECT 128.600 123.650 132.600 124.710 ;
        RECT 126.965 123.350 132.600 123.650 ;
        RECT 126.965 123.335 127.295 123.350 ;
        RECT 39.105 122.290 39.435 122.305 ;
        RECT 32.600 121.990 39.435 122.290 ;
        RECT 32.600 120.930 36.600 121.990 ;
        RECT 39.105 121.975 39.435 121.990 ;
        RECT 118.685 122.290 119.015 122.305 ;
        RECT 128.600 122.290 132.600 123.350 ;
        RECT 118.685 121.990 132.600 122.290 ;
        RECT 118.685 121.975 119.015 121.990 ;
        RECT 38.645 120.930 38.975 120.945 ;
        RECT 32.600 120.630 38.975 120.930 ;
        RECT 32.600 119.700 36.600 120.630 ;
        RECT 38.645 120.615 38.975 120.630 ;
        RECT 124.205 120.930 124.535 120.945 ;
        RECT 128.600 120.930 132.600 121.990 ;
        RECT 124.205 120.630 132.600 120.930 ;
        RECT 124.205 120.615 124.535 120.630 ;
        RECT 128.600 119.700 132.600 120.630 ;
        RECT 32.600 119.050 132.600 119.700 ;
        RECT 32.600 118.210 36.600 119.050 ;
        RECT 38.185 118.210 38.515 118.225 ;
        RECT 32.600 117.910 38.515 118.210 ;
        RECT 32.600 116.850 36.600 117.910 ;
        RECT 38.185 117.895 38.515 117.910 ;
        RECT 126.505 118.210 126.835 118.225 ;
        RECT 128.600 118.210 132.600 119.050 ;
        RECT 126.505 117.910 132.600 118.210 ;
        RECT 126.505 117.895 126.835 117.910 ;
        RECT 48.765 116.850 49.095 116.865 ;
        RECT 32.600 116.550 49.095 116.850 ;
        RECT 32.600 115.490 36.600 116.550 ;
        RECT 48.765 116.535 49.095 116.550 ;
        RECT 126.045 116.850 126.375 116.865 ;
        RECT 128.600 116.850 132.600 117.910 ;
        RECT 126.045 116.550 132.600 116.850 ;
        RECT 126.045 116.535 126.375 116.550 ;
        RECT 49.225 115.490 49.555 115.505 ;
        RECT 32.600 115.190 49.555 115.490 ;
        RECT 32.600 114.200 36.600 115.190 ;
        RECT 49.225 115.175 49.555 115.190 ;
        RECT 120.985 115.490 121.315 115.505 ;
        RECT 128.600 115.490 132.600 116.550 ;
        RECT 120.985 115.190 132.600 115.490 ;
        RECT 120.985 115.175 121.315 115.190 ;
        RECT 128.600 114.200 132.600 115.190 ;
        RECT 32.600 113.655 132.600 114.200 ;
        RECT 32.600 112.770 36.600 113.655 ;
        RECT 46.925 112.770 47.255 112.785 ;
        RECT 32.600 112.470 47.255 112.770 ;
        RECT 32.600 111.410 36.600 112.470 ;
        RECT 46.925 112.455 47.255 112.470 ;
        RECT 118.685 112.770 119.015 112.785 ;
        RECT 128.600 112.770 132.600 113.655 ;
        RECT 118.685 112.470 132.600 112.770 ;
        RECT 118.685 112.455 119.015 112.470 ;
        RECT 38.645 111.410 38.975 111.425 ;
        RECT 32.600 111.110 38.975 111.410 ;
        RECT 32.600 110.050 36.600 111.110 ;
        RECT 38.645 111.095 38.975 111.110 ;
        RECT 126.505 111.410 126.835 111.425 ;
        RECT 128.600 111.410 132.600 112.470 ;
        RECT 126.505 111.110 132.600 111.410 ;
        RECT 126.505 111.095 126.835 111.110 ;
        RECT 39.105 110.050 39.435 110.065 ;
        RECT 32.600 109.750 39.435 110.050 ;
        RECT 32.600 108.690 36.600 109.750 ;
        RECT 39.105 109.735 39.435 109.750 ;
        RECT 118.685 110.050 119.015 110.065 ;
        RECT 128.600 110.050 132.600 111.110 ;
        RECT 118.685 109.750 132.600 110.050 ;
        RECT 118.685 109.735 119.015 109.750 ;
        RECT 39.105 108.690 39.435 108.705 ;
        RECT 32.600 108.390 39.435 108.690 ;
        RECT 32.600 107.400 36.600 108.390 ;
        RECT 39.105 108.375 39.435 108.390 ;
        RECT 123.745 108.690 124.075 108.705 ;
        RECT 128.600 108.690 132.600 109.750 ;
        RECT 123.745 108.390 132.600 108.690 ;
        RECT 123.745 108.375 124.075 108.390 ;
        RECT 128.600 107.400 132.600 108.390 ;
        RECT 32.600 106.800 132.600 107.400 ;
        RECT 32.600 105.970 36.600 106.800 ;
        RECT 46.925 105.970 47.255 105.985 ;
        RECT 32.600 105.670 47.255 105.970 ;
        RECT 32.600 104.610 36.600 105.670 ;
        RECT 46.925 105.655 47.255 105.670 ;
        RECT 126.505 105.970 126.835 105.985 ;
        RECT 128.600 105.970 132.600 106.800 ;
        RECT 126.505 105.670 132.600 105.970 ;
        RECT 126.505 105.655 126.835 105.670 ;
        RECT 39.105 104.610 39.435 104.625 ;
        RECT 32.600 104.310 39.435 104.610 ;
        RECT 32.600 103.250 36.600 104.310 ;
        RECT 39.105 104.295 39.435 104.310 ;
        RECT 126.045 104.610 126.375 104.625 ;
        RECT 128.600 104.610 132.600 105.670 ;
        RECT 126.045 104.310 132.600 104.610 ;
        RECT 126.045 104.295 126.375 104.310 ;
        RECT 38.645 103.250 38.975 103.265 ;
        RECT 32.600 102.950 38.975 103.250 ;
        RECT 32.600 102.000 36.600 102.950 ;
        RECT 38.645 102.935 38.975 102.950 ;
        RECT 120.985 103.250 121.315 103.265 ;
        RECT 128.600 103.250 132.600 104.310 ;
        RECT 120.985 102.950 132.600 103.250 ;
        RECT 120.985 102.935 121.315 102.950 ;
        RECT 128.600 102.000 132.600 102.950 ;
        RECT 32.600 101.250 132.600 102.000 ;
        RECT 32.600 100.530 36.600 101.250 ;
        RECT 39.105 100.530 39.435 100.545 ;
        RECT 32.600 100.230 39.435 100.530 ;
        RECT 32.600 99.170 36.600 100.230 ;
        RECT 39.105 100.215 39.435 100.230 ;
        RECT 118.685 100.530 119.015 100.545 ;
        RECT 128.600 100.530 132.600 101.250 ;
        RECT 118.685 100.230 132.600 100.530 ;
        RECT 118.685 100.215 119.015 100.230 ;
        RECT 38.185 99.170 38.515 99.185 ;
        RECT 32.600 98.870 38.515 99.170 ;
        RECT 32.600 97.810 36.600 98.870 ;
        RECT 38.185 98.855 38.515 98.870 ;
        RECT 120.985 99.170 121.315 99.185 ;
        RECT 128.600 99.170 132.600 100.230 ;
        RECT 120.985 98.870 132.600 99.170 ;
        RECT 120.985 98.855 121.315 98.870 ;
        RECT 39.105 97.810 39.435 97.825 ;
        RECT 32.600 97.510 39.435 97.810 ;
        RECT 32.600 96.450 36.600 97.510 ;
        RECT 39.105 97.495 39.435 97.510 ;
        RECT 123.745 97.810 124.075 97.825 ;
        RECT 128.600 97.810 132.600 98.870 ;
        RECT 123.745 97.510 132.600 97.810 ;
        RECT 123.745 97.495 124.075 97.510 ;
        RECT 37.725 96.450 38.055 96.465 ;
        RECT 32.600 96.150 38.055 96.450 ;
        RECT 32.600 95.200 36.600 96.150 ;
        RECT 37.725 96.135 38.055 96.150 ;
        RECT 118.685 96.450 119.015 96.465 ;
        RECT 128.600 96.450 132.600 97.510 ;
        RECT 118.685 96.150 132.600 96.450 ;
        RECT 118.685 96.135 119.015 96.150 ;
        RECT 128.600 95.200 132.600 96.150 ;
        RECT 32.600 94.650 132.600 95.200 ;
        RECT 32.600 93.730 36.600 94.650 ;
        RECT 48.765 93.730 49.095 93.745 ;
        RECT 32.600 93.430 49.095 93.730 ;
        RECT 32.600 92.370 36.600 93.430 ;
        RECT 48.765 93.415 49.095 93.430 ;
        RECT 126.505 93.730 126.835 93.745 ;
        RECT 128.600 93.730 132.600 94.650 ;
        RECT 126.505 93.430 132.600 93.730 ;
        RECT 126.505 93.415 126.835 93.430 ;
        RECT 39.105 92.370 39.435 92.385 ;
        RECT 32.600 92.070 39.435 92.370 ;
        RECT 32.600 91.010 36.600 92.070 ;
        RECT 39.105 92.055 39.435 92.070 ;
        RECT 126.045 92.370 126.375 92.385 ;
        RECT 128.600 92.370 132.600 93.430 ;
        RECT 126.045 92.070 132.600 92.370 ;
        RECT 126.045 92.055 126.375 92.070 ;
        RECT 39.105 91.010 39.435 91.025 ;
        RECT 32.600 90.710 39.435 91.010 ;
        RECT 32.600 89.800 36.600 90.710 ;
        RECT 39.105 90.695 39.435 90.710 ;
        RECT 120.985 91.010 121.315 91.025 ;
        RECT 128.600 91.010 132.600 92.070 ;
        RECT 120.985 90.710 132.600 91.010 ;
        RECT 120.985 90.695 121.315 90.710 ;
        RECT 128.600 89.800 132.600 90.710 ;
        RECT 32.600 89.100 132.600 89.800 ;
        RECT 32.600 88.290 36.600 89.100 ;
        RECT 48.765 88.290 49.095 88.305 ;
        RECT 32.600 87.990 49.095 88.290 ;
        RECT 32.600 86.930 36.600 87.990 ;
        RECT 48.765 87.975 49.095 87.990 ;
        RECT 118.685 88.290 119.015 88.305 ;
        RECT 128.600 88.290 132.600 89.100 ;
        RECT 118.685 87.990 132.600 88.290 ;
        RECT 118.685 87.975 119.015 87.990 ;
        RECT 49.225 86.930 49.555 86.945 ;
        RECT 32.600 86.630 49.555 86.930 ;
        RECT 32.600 85.570 36.600 86.630 ;
        RECT 49.225 86.615 49.555 86.630 ;
        RECT 120.985 86.930 121.315 86.945 ;
        RECT 128.600 86.930 132.600 87.990 ;
        RECT 120.985 86.630 132.600 86.930 ;
        RECT 120.985 86.615 121.315 86.630 ;
        RECT 38.645 85.570 38.975 85.585 ;
        RECT 32.600 85.270 38.975 85.570 ;
        RECT 32.600 84.400 36.600 85.270 ;
        RECT 38.645 85.255 38.975 85.270 ;
        RECT 118.685 85.570 119.015 85.585 ;
        RECT 128.600 85.570 132.600 86.630 ;
        RECT 118.685 85.270 132.600 85.570 ;
        RECT 118.685 85.255 119.015 85.270 ;
        RECT 128.600 84.400 132.600 85.270 ;
        RECT 32.600 83.700 132.600 84.400 ;
        RECT 32.600 82.850 36.600 83.700 ;
        RECT 38.185 82.850 38.515 82.865 ;
        RECT 32.600 82.550 38.515 82.850 ;
        RECT 32.600 81.490 36.600 82.550 ;
        RECT 38.185 82.535 38.515 82.550 ;
        RECT 126.045 82.850 126.375 82.865 ;
        RECT 128.600 82.850 132.600 83.700 ;
        RECT 126.045 82.550 132.600 82.850 ;
        RECT 126.045 82.535 126.375 82.550 ;
        RECT 54.285 81.490 54.615 81.505 ;
        RECT 32.600 81.190 54.615 81.490 ;
        RECT 32.600 80.130 36.600 81.190 ;
        RECT 54.285 81.175 54.615 81.190 ;
        RECT 128.600 80.145 132.600 82.550 ;
        RECT 48.765 80.130 49.095 80.145 ;
        RECT 32.600 79.830 49.095 80.130 ;
        RECT 32.600 78.875 36.600 79.830 ;
        RECT 48.765 79.815 49.095 79.830 ;
        RECT 128.345 79.815 132.600 80.145 ;
        RECT 128.600 78.875 132.600 79.815 ;
        RECT 32.600 77.900 132.600 78.875 ;
        RECT 32.600 77.410 36.600 77.900 ;
        RECT 39.105 77.410 39.435 77.425 ;
        RECT 32.600 77.110 39.435 77.410 ;
        RECT 32.600 76.050 36.600 77.110 ;
        RECT 39.105 77.095 39.435 77.110 ;
        RECT 46.925 76.050 47.255 76.065 ;
        RECT 32.600 75.750 47.255 76.050 ;
        RECT 32.600 74.690 36.600 75.750 ;
        RECT 46.925 75.735 47.255 75.750 ;
        RECT 121.905 76.050 122.235 76.065 ;
        RECT 128.600 76.050 132.600 77.900 ;
        RECT 121.905 75.750 132.600 76.050 ;
        RECT 121.905 75.735 122.235 75.750 ;
        RECT 128.600 74.900 132.600 75.750 ;
        RECT 40.945 74.690 41.275 74.705 ;
        RECT 32.600 74.390 41.275 74.690 ;
        RECT 32.600 73.375 36.600 74.390 ;
        RECT 40.945 74.375 41.275 74.390 ;
        RECT 127.795 74.100 132.600 74.900 ;
        RECT 128.600 73.375 132.600 74.100 ;
        RECT 32.600 72.400 132.600 73.375 ;
        RECT 32.600 71.400 36.600 72.400 ;
        RECT 128.600 71.400 132.600 72.400 ;
        RECT 29.280 66.940 135.760 68.540 ;
        RECT 4.000 63.740 138.960 65.340 ;
        RECT 4.000 46.370 6.000 63.740 ;
        RECT 22.500 53.400 23.300 53.500 ;
        RECT 104.000 53.400 104.900 53.600 ;
        RECT 22.500 52.900 104.900 53.400 ;
        RECT 22.500 52.800 23.300 52.900 ;
        RECT 104.000 52.710 104.900 52.900 ;
        RECT 15.900 48.600 17.000 48.710 ;
        RECT 126.990 48.600 127.800 48.710 ;
        RECT 15.900 48.000 127.810 48.600 ;
        RECT 15.900 47.900 17.000 48.000 ;
        RECT 126.990 47.810 127.800 48.000 ;
      LAYER met4 ;
        RECT 20.100 173.710 144.830 174.210 ;
        RECT 20.100 167.510 20.600 173.710 ;
        RECT 20.000 166.600 20.700 167.510 ;
        RECT 22.400 164.000 23.500 164.800 ;
        RECT 16.000 159.590 17.000 160.400 ;
        RECT 16.200 48.700 16.800 159.590 ;
        RECT 22.735 53.600 23.145 164.000 ;
        RECT 26.080 63.740 27.680 172.810 ;
        RECT 29.280 66.940 30.880 169.610 ;
        RECT 33.250 70.700 36.040 94.450 ;
        RECT 22.400 52.700 23.400 53.600 ;
        RECT 16.000 47.900 16.900 48.700 ;
        RECT 33.600 27.860 35.700 70.700 ;
        RECT 39.580 66.940 41.180 169.610 ;
        RECT 42.080 63.740 43.680 172.810 ;
        RECT 44.580 66.940 46.180 169.610 ;
        RECT 47.080 63.740 48.680 172.810 ;
        RECT 49.580 66.940 51.180 169.610 ;
        RECT 52.080 63.740 53.680 172.810 ;
        RECT 54.580 66.940 56.180 169.610 ;
        RECT 57.080 63.740 58.680 172.810 ;
        RECT 59.580 66.940 61.180 169.610 ;
        RECT 62.080 63.740 63.680 172.810 ;
        RECT 64.580 66.940 66.180 169.610 ;
        RECT 67.080 63.740 68.680 172.810 ;
        RECT 69.580 66.940 71.180 169.610 ;
        RECT 72.080 63.740 73.680 172.810 ;
        RECT 74.580 66.940 76.180 169.610 ;
        RECT 77.080 63.740 78.680 172.810 ;
        RECT 79.580 66.940 81.180 169.610 ;
        RECT 82.080 63.740 83.680 172.810 ;
        RECT 84.580 66.940 86.180 169.610 ;
        RECT 87.080 63.740 88.680 172.810 ;
        RECT 89.580 66.940 91.180 169.610 ;
        RECT 92.080 63.740 93.680 172.810 ;
        RECT 94.580 66.940 96.180 169.610 ;
        RECT 97.080 63.740 98.680 172.810 ;
        RECT 99.580 66.940 101.180 169.610 ;
        RECT 102.080 63.740 103.680 172.810 ;
        RECT 104.580 66.940 106.180 169.610 ;
        RECT 107.080 63.740 108.680 172.810 ;
        RECT 109.580 66.940 111.180 169.610 ;
        RECT 112.080 63.740 113.680 172.810 ;
        RECT 114.580 66.940 116.180 169.610 ;
        RECT 117.080 63.740 118.680 172.810 ;
        RECT 119.580 66.940 121.180 169.610 ;
        RECT 122.080 63.740 123.680 172.810 ;
        RECT 124.580 66.940 126.180 169.610 ;
        RECT 134.160 66.940 135.760 169.610 ;
        RECT 137.360 63.740 138.960 172.810 ;
        RECT 97.290 61.340 98.600 61.600 ;
        RECT 144.330 61.340 144.830 173.710 ;
        RECT 97.290 60.840 144.830 61.340 ;
        RECT 97.290 60.570 98.600 60.840 ;
        RECT 33.600 26.960 79.110 27.860 ;
        RECT 78.210 1.000 79.110 26.960 ;
        RECT 97.530 1.000 98.430 60.570 ;
        RECT 103.890 53.560 104.900 53.800 ;
        RECT 103.890 52.660 117.750 53.560 ;
        RECT 103.890 52.400 104.900 52.660 ;
        RECT 116.850 1.000 117.750 52.660 ;
        RECT 126.890 48.840 127.810 49.000 ;
        RECT 126.890 47.940 137.070 48.840 ;
        RECT 126.890 47.720 127.810 47.940 ;
        RECT 136.170 1.000 137.070 47.940 ;
  END
END tt_um_STDCELL_LDO
END LIBRARY

